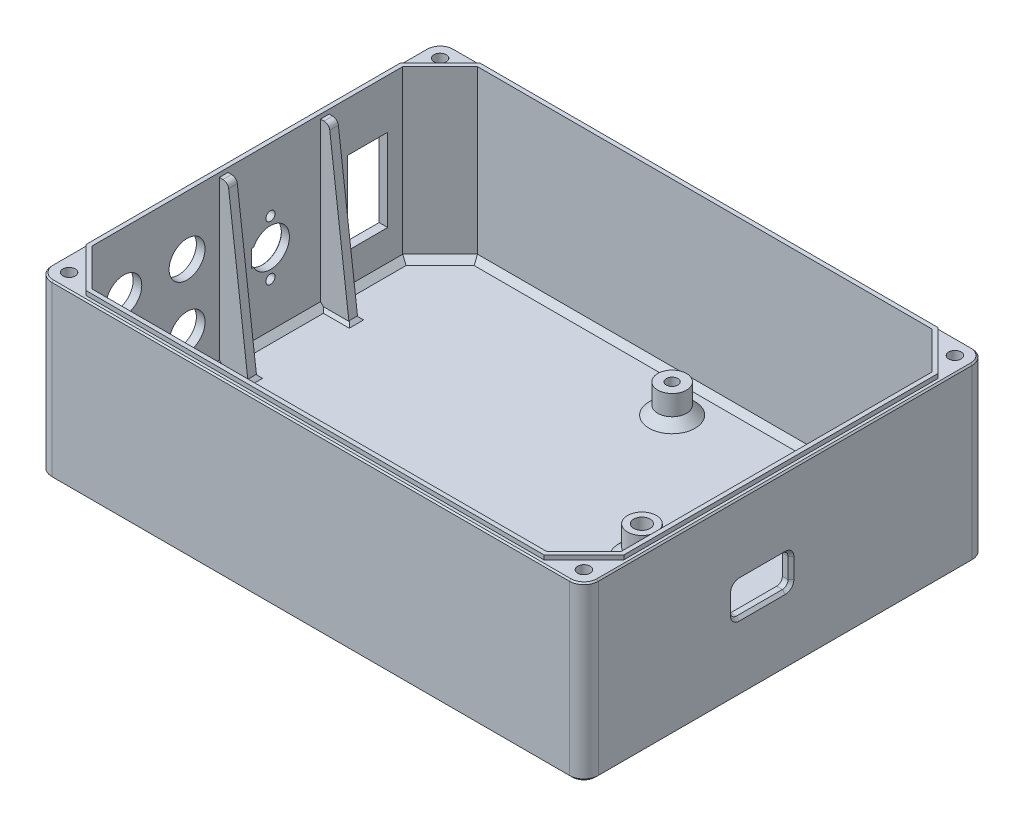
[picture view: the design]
ISO-10303-21;
HEADER;
FILE_DESCRIPTION(('STEP AP214'),'2;1');
FILE_NAME('part.step','',(''),(''),'','','');
FILE_SCHEMA(('AUTOMOTIVE_DESIGN { 1 0 10303 214 1 1 1 1 }'));
ENDSEC;
DATA;
#1=APPLICATION_CONTEXT('core data for automotive mechanical design processes');
#2=APPLICATION_PROTOCOL_DEFINITION('international standard','automotive_design',2000,#1);
#3=PRODUCT_CONTEXT('',#1,'mechanical');
#4=PRODUCT('Part','Part','',(#3));
#5=PRODUCT_RELATED_PRODUCT_CATEGORY('part','',(#4));
#6=PRODUCT_DEFINITION_FORMATION('','',#4);
#7=PRODUCT_DEFINITION_CONTEXT('part definition',#1,'design');
#8=PRODUCT_DEFINITION('design','',#6,#7);
#9=PRODUCT_DEFINITION_SHAPE('','',#8);
#10=(LENGTH_UNIT() NAMED_UNIT(*) SI_UNIT(.MILLI.,.METRE.));
#11=(NAMED_UNIT(*) PLANE_ANGLE_UNIT() SI_UNIT($,.RADIAN.));
#12=(NAMED_UNIT(*) SI_UNIT($,.STERADIAN.) SOLID_ANGLE_UNIT());
#13=UNCERTAINTY_MEASURE_WITH_UNIT(LENGTH_MEASURE(1.E-05),#10,'distance_accuracy_value','');
#14=(GEOMETRIC_REPRESENTATION_CONTEXT(3) GLOBAL_UNCERTAINTY_ASSIGNED_CONTEXT((#13)) GLOBAL_UNIT_ASSIGNED_CONTEXT((#10,
#11,#12)) REPRESENTATION_CONTEXT('',''));
#15=CARTESIAN_POINT('',(0.,0.,0.));
#16=DIRECTION('',(0.,0.,1.));
#17=DIRECTION('',(1.,0.,0.));
#18=AXIS2_PLACEMENT_3D('',#15,#16,#17);
#19=CARTESIAN_POINT('',(0.,60.,0.));
#20=DIRECTION('',(0.,1.,0.));
#21=DIRECTION('',(0.,0.,1.));
#22=AXIS2_PLACEMENT_3D('',#19,#20,#21);
#23=PLANE('',#22);
#24=DIRECTION('',(-1.,0.,0.));
#25=VECTOR('',#24,1.);
#26=CARTESIAN_POINT('',(-82.,60.,-28.4080157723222));
#27=LINE('',#26,#25);
#28=CARTESIAN_POINT('',(-90.7694110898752,60.,-28.4080157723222));
#29=VERTEX_POINT('',#28);
#30=CARTESIAN_POINT('',(-92.,60.,-28.4080157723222));
#31=VERTEX_POINT('',#30);
#32=EDGE_CURVE('E831',#29,#31,#27,.T.);
#33=ORIENTED_EDGE('',*,*,#32,.T.);
#34=DIRECTION('',(0.,0.,1.));
#35=VECTOR('',#34,1.);
#36=CARTESIAN_POINT('',(-92.,60.,-54.));
#37=LINE('',#36,#35);
#38=CARTESIAN_POINT('',(-92.,60.,-25.4080157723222));
#39=VERTEX_POINT('',#38);
#40=EDGE_CURVE('E731',#31,#39,#37,.T.);
#41=ORIENTED_EDGE('',*,*,#40,.T.);
#42=DIRECTION('',(-1.,0.,0.));
#43=VECTOR('',#42,1.);
#44=CARTESIAN_POINT('',(-82.,60.,-25.4080157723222));
#45=LINE('',#44,#43);
#46=CARTESIAN_POINT('',(-90.7694110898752,60.,-25.4080157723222));
#47=VERTEX_POINT('',#46);
#48=EDGE_CURVE('E839',#47,#39,#45,.T.);
#49=ORIENTED_EDGE('',*,*,#48,.F.);
#50=DIRECTION('',(0.,0.,1.));
#51=VECTOR('',#50,1.);
#52=CARTESIAN_POINT('',(-90.7694110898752,60.,-28.4080157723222));
#53=LINE('',#52,#51);
#54=EDGE_CURVE('E1308',#47,#29,#53,.F.);
#55=ORIENTED_EDGE('',*,*,#54,.T.);
#56=EDGE_LOOP('',(#33,#41,#49,#55));
#57=FACE_BOUND('',#56,.T.);
#58=ADVANCED_FACE('F162',(#57),#23,.T.);
#59=DIRECTION('',(-1.,0.,0.));
#60=VECTOR('',#59,1.);
#61=CARTESIAN_POINT('',(-82.,60.,6.74685594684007));
#62=LINE('',#61,#60);
#63=CARTESIAN_POINT('',(-90.7694110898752,60.,6.74685594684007));
#64=VERTEX_POINT('',#63);
#65=CARTESIAN_POINT('',(-92.,60.,6.74685594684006));
#66=VERTEX_POINT('',#65);
#67=EDGE_CURVE('E819',#64,#66,#62,.T.);
#68=ORIENTED_EDGE('',*,*,#67,.T.);
#69=CARTESIAN_POINT('',(-92.,60.,9.74685594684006));
#70=VERTEX_POINT('',#69);
#71=EDGE_CURVE('E736',#66,#70,#37,.T.);
#72=ORIENTED_EDGE('',*,*,#71,.T.);
#73=DIRECTION('',(-1.,0.,0.));
#74=VECTOR('',#73,1.);
#75=CARTESIAN_POINT('',(-82.,60.,9.74685594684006));
#76=LINE('',#75,#74);
#77=CARTESIAN_POINT('',(-90.7694110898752,60.,9.74685594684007));
#78=VERTEX_POINT('',#77);
#79=EDGE_CURVE('E850',#78,#70,#76,.T.);
#80=ORIENTED_EDGE('',*,*,#79,.F.);
#81=DIRECTION('',(0.,0.,1.));
#82=VECTOR('',#81,1.);
#83=CARTESIAN_POINT('',(-90.7694110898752,60.,6.74685594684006));
#84=LINE('',#83,#82);
#85=EDGE_CURVE('E1304',#78,#64,#84,.F.);
#86=ORIENTED_EDGE('',*,*,#85,.T.);
#87=EDGE_LOOP('',(#68,#72,#80,#86));
#88=FACE_BOUND('',#87,.T.);
#89=ADVANCED_FACE('F1625',(#88),#23,.T.);
#90=CARTESIAN_POINT('',(-92.,60.,-70.));
#91=DIRECTION('',(1.,0.,0.));
#92=DIRECTION('',(0.,0.,-1.));
#93=AXIS2_PLACEMENT_3D('',#90,#91,#92);
#94=PLANE('',#93);
#95=DIRECTION('',(0.,-1.,0.));
#96=VECTOR('',#95,1.);
#97=CARTESIAN_POINT('',(-92.,60.,-34.7737095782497));
#98=LINE('',#97,#96);
#99=CARTESIAN_POINT('',(-92.,44.35,-34.7737095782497));
#100=VERTEX_POINT('',#99);
#101=CARTESIAN_POINT('',(-92.,15.65,-34.7737095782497));
#102=VERTEX_POINT('',#101);
#103=EDGE_CURVE('E950',#100,#102,#98,.T.);
#104=ORIENTED_EDGE('',*,*,#103,.F.);
#105=DIRECTION('',(0.,0.,1.));
#106=VECTOR('',#105,1.);
#107=CARTESIAN_POINT('',(-92.,44.35,-70.));
#108=LINE('',#107,#106);
#109=CARTESIAN_POINT('',(-92.,44.35,-48.7737095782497));
#110=VERTEX_POINT('',#109);
#111=EDGE_CURVE('E937',#110,#100,#108,.T.);
#112=ORIENTED_EDGE('',*,*,#111,.F.);
#113=DIRECTION('',(0.,1.,0.));
#114=VECTOR('',#113,1.);
#115=CARTESIAN_POINT('',(-92.,60.,-48.7737095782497));
#116=LINE('',#115,#114);
#117=CARTESIAN_POINT('',(-92.,15.65,-48.7737095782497));
#118=VERTEX_POINT('',#117);
#119=EDGE_CURVE('E945',#118,#110,#116,.T.);
#120=ORIENTED_EDGE('',*,*,#119,.F.);
#121=DIRECTION('',(0.,0.,-1.));
#122=VECTOR('',#121,1.);
#123=CARTESIAN_POINT('',(-92.,15.65,-70.));
#124=LINE('',#123,#122);
#125=EDGE_CURVE('E944',#102,#118,#124,.T.);
#126=ORIENTED_EDGE('',*,*,#125,.F.);
#127=EDGE_LOOP('',(#104,#112,#120,#126));
#128=FACE_BOUND('',#127,.T.);
#129=DIRECTION('',(0.,-1.,0.));
#130=VECTOR('',#129,1.);
#131=CARTESIAN_POINT('',(-92.,60.,-54.));
#132=LINE('',#131,#130);
#133=CARTESIAN_POINT('',(-92.,61.5,-54.));
#134=VERTEX_POINT('',#133);
#135=CARTESIAN_POINT('',(-92.,4.99999999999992,-54.));
#136=VERTEX_POINT('',#135);
#137=EDGE_CURVE('E698',#134,#136,#132,.T.);
#138=ORIENTED_EDGE('',*,*,#137,.F.);
#139=DIRECTION('',(0.,0.,1.));
#140=VECTOR('',#139,1.);
#141=CARTESIAN_POINT('',(-92.,61.5,-54.));
#142=LINE('',#141,#140);
#143=CARTESIAN_POINT('',(-92.,61.5,54.));
#144=VERTEX_POINT('',#143);
#145=EDGE_CURVE('E712',#134,#144,#142,.T.);
#146=ORIENTED_EDGE('',*,*,#145,.T.);
#147=DIRECTION('',(0.,-1.,0.));
#148=VECTOR('',#147,1.);
#149=CARTESIAN_POINT('',(-92.,60.,54.));
#150=LINE('',#149,#148);
#151=CARTESIAN_POINT('',(-92.,4.99999999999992,54.));
#152=VERTEX_POINT('',#151);
#153=EDGE_CURVE('E1052',#144,#152,#150,.T.);
#154=ORIENTED_EDGE('',*,*,#153,.T.);
#155=DIRECTION('',(0.,0.,-1.));
#156=VECTOR('',#155,1.);
#157=CARTESIAN_POINT('',(-92.,4.99999999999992,-54.));
#158=LINE('',#157,#156);
#159=CARTESIAN_POINT('',(-92.,4.99999999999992,34.0694365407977));
#160=VERTEX_POINT('',#159);
#161=EDGE_CURVE('E1155',#152,#160,#158,.T.);
#162=ORIENTED_EDGE('',*,*,#161,.T.);
#163=DIRECTION('',(0.,-1.,0.));
#164=VECTOR('',#163,1.);
#165=CARTESIAN_POINT('',(-92.,3.,34.0694365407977));
#166=LINE('',#165,#164);
#167=CARTESIAN_POINT('',(-92.,15.6591352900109,34.0694365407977));
#168=VERTEX_POINT('',#167);
#169=EDGE_CURVE('E817',#168,#160,#166,.T.);
#170=ORIENTED_EDGE('',*,*,#169,.F.);
#171=DIRECTION('',(0.,0.,1.));
#172=VECTOR('',#171,1.);
#173=CARTESIAN_POINT('',(-92.,15.6591352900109,34.0694365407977));
#174=LINE('',#173,#172);
#175=CARTESIAN_POINT('',(-92.,15.6591352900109,31.0694365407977));
#176=VERTEX_POINT('',#175);
#177=EDGE_CURVE('E823',#176,#168,#174,.T.);
#178=ORIENTED_EDGE('',*,*,#177,.F.);
#179=DIRECTION('',(0.,1.,0.));
#180=VECTOR('',#179,1.);
#181=CARTESIAN_POINT('',(-92.,3.,31.0694365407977));
#182=LINE('',#181,#180);
#183=CARTESIAN_POINT('',(-92.,4.99999999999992,31.0694365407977));
#184=VERTEX_POINT('',#183);
#185=EDGE_CURVE('E822',#184,#176,#182,.T.);
#186=ORIENTED_EDGE('',*,*,#185,.F.);
#187=CARTESIAN_POINT('',(-92.,4.99999999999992,9.74685594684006));
#188=VERTEX_POINT('',#187);
#189=EDGE_CURVE('E1151',#184,#188,#158,.T.);
#190=ORIENTED_EDGE('',*,*,#189,.T.);
#191=DIRECTION('',(0.,-1.,0.));
#192=VECTOR('',#191,1.);
#193=CARTESIAN_POINT('',(-92.,60.,9.74685594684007));
#194=LINE('',#193,#192);
#195=EDGE_CURVE('E836',#70,#188,#194,.T.);
#196=ORIENTED_EDGE('',*,*,#195,.F.);
#197=ORIENTED_EDGE('',*,*,#71,.F.);
#198=DIRECTION('',(0.,1.,0.));
#199=VECTOR('',#198,1.);
#200=CARTESIAN_POINT('',(-92.,60.,6.74685594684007));
#201=LINE('',#200,#199);
#202=CARTESIAN_POINT('',(-92.,4.99999999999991,6.74685594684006));
#203=VERTEX_POINT('',#202);
#204=EDGE_CURVE('E848',#203,#66,#201,.T.);
#205=ORIENTED_EDGE('',*,*,#204,.F.);
#206=CARTESIAN_POINT('',(-92.,4.99999999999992,-25.4080157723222));
#207=VERTEX_POINT('',#206);
#208=EDGE_CURVE('E3165',#203,#207,#158,.T.);
#209=ORIENTED_EDGE('',*,*,#208,.T.);
#210=DIRECTION('',(0.,-1.,0.));
#211=VECTOR('',#210,1.);
#212=CARTESIAN_POINT('',(-92.,3.,-25.4080157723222));
#213=LINE('',#212,#211);
#214=EDGE_CURVE('E825',#39,#207,#213,.T.);
#215=ORIENTED_EDGE('',*,*,#214,.F.);
#216=ORIENTED_EDGE('',*,*,#40,.F.);
#217=DIRECTION('',(0.,1.,0.));
#218=VECTOR('',#217,1.);
#219=CARTESIAN_POINT('',(-92.,3.,-28.4080157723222));
#220=LINE('',#219,#218);
#221=CARTESIAN_POINT('',(-92.,4.99999999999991,-28.4080157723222));
#222=VERTEX_POINT('',#221);
#223=EDGE_CURVE('E837',#222,#31,#220,.T.);
#224=ORIENTED_EDGE('',*,*,#223,.F.);
#225=EDGE_CURVE('E1152',#222,#136,#158,.T.);
#226=ORIENTED_EDGE('',*,*,#225,.T.);
#227=EDGE_LOOP('',(#138,#146,#154,#162,#170,#178,#186,#190,#196,#197,#205,#209,#215,#216,#224,#226));
#228=FACE_BOUND('',#227,.T.);
#229=CARTESIAN_POINT('',(-92.,30.,-7.99999999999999));
#230=DIRECTION('',(1.,0.,0.));
#231=DIRECTION('',(0.,0.,-1.));
#232=AXIS2_PLACEMENT_3D('',#229,#230,#231);
#233=CIRCLE('',#232,6.6);
#234=CARTESIAN_POINT('',(-92.,27.,-2.12122461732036));
#235=VERTEX_POINT('',#234);
#236=CARTESIAN_POINT('',(-92.,33.,-2.12122461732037));
#237=VERTEX_POINT('',#236);
#238=EDGE_CURVE('E929',#235,#237,#233,.T.);
#239=ORIENTED_EDGE('',*,*,#238,.F.);
#240=DIRECTION('',(0.,0.,-1.));
#241=VECTOR('',#240,1.);
#242=CARTESIAN_POINT('',(-92.,27.,-70.));
#243=LINE('',#242,#241);
#244=CARTESIAN_POINT('',(-92.,27.,-1.4));
#245=VERTEX_POINT('',#244);
#246=EDGE_CURVE('E925',#245,#235,#243,.T.);
#247=ORIENTED_EDGE('',*,*,#246,.F.);
#248=DIRECTION('',(0.,-1.,0.));
#249=VECTOR('',#248,1.);
#250=CARTESIAN_POINT('',(-92.,60.,-1.4));
#251=LINE('',#250,#249);
#252=CARTESIAN_POINT('',(-92.,33.,-1.39999999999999));
#253=VERTEX_POINT('',#252);
#254=EDGE_CURVE('E921',#253,#245,#251,.T.);
#255=ORIENTED_EDGE('',*,*,#254,.F.);
#256=DIRECTION('',(0.,0.,1.));
#257=VECTOR('',#256,1.);
#258=CARTESIAN_POINT('',(-92.,33.,-70.));
#259=LINE('',#258,#257);
#260=EDGE_CURVE('E930',#237,#253,#259,.T.);
#261=ORIENTED_EDGE('',*,*,#260,.F.);
#262=EDGE_LOOP('',(#239,#247,#255,#261));
#263=FACE_BOUND('',#262,.T.);
#264=CARTESIAN_POINT('',(-92.,39.5,-7.99999999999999));
#265=DIRECTION('',(1.,0.,0.));
#266=DIRECTION('',(0.,0.,-1.));
#267=AXIS2_PLACEMENT_3D('',#264,#265,#266);
#268=CIRCLE('',#267,1.6);
#269=CARTESIAN_POINT('',(-92.,39.5,-9.59999999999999));
#270=VERTEX_POINT('',#269);
#271=EDGE_CURVE('E935',#270,#270,#268,.T.);
#272=ORIENTED_EDGE('',*,*,#271,.F.);
#273=EDGE_LOOP('',(#272));
#274=FACE_BOUND('',#273,.T.);
#275=CARTESIAN_POINT('',(-92.,20.5,-7.99999999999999));
#276=DIRECTION('',(1.,0.,0.));
#277=DIRECTION('',(0.,0.,-1.));
#278=AXIS2_PLACEMENT_3D('',#275,#276,#277);
#279=CIRCLE('',#278,1.6);
#280=CARTESIAN_POINT('',(-92.,20.5,-9.59999999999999));
#281=VERTEX_POINT('',#280);
#282=EDGE_CURVE('E940',#281,#281,#279,.T.);
#283=ORIENTED_EDGE('',*,*,#282,.F.);
#284=EDGE_LOOP('',(#283));
#285=FACE_BOUND('',#284,.T.);
#286=CARTESIAN_POINT('',(-92.,41.,43.));
#287=DIRECTION('',(1.,0.,0.));
#288=DIRECTION('',(0.,0.,-1.));
#289=AXIS2_PLACEMENT_3D('',#286,#287,#288);
#290=CIRCLE('',#289,6.25000000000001);
#291=CARTESIAN_POINT('',(-92.,41.,36.75));
#292=VERTEX_POINT('',#291);
#293=EDGE_CURVE('E933',#292,#292,#290,.T.);
#294=ORIENTED_EDGE('',*,*,#293,.F.);
#295=EDGE_LOOP('',(#294));
#296=FACE_BOUND('',#295,.T.);
#297=CARTESIAN_POINT('',(-92.,41.,21.));
#298=DIRECTION('',(1.,0.,0.));
#299=DIRECTION('',(0.,0.,-1.));
#300=AXIS2_PLACEMENT_3D('',#297,#298,#299);
#301=CIRCLE('',#300,6.25);
#302=CARTESIAN_POINT('',(-92.,41.,14.75));
#303=VERTEX_POINT('',#302);
#304=EDGE_CURVE('E920',#303,#303,#301,.T.);
#305=ORIENTED_EDGE('',*,*,#304,.F.);
#306=EDGE_LOOP('',(#305));
#307=FACE_BOUND('',#306,.T.);
#308=CARTESIAN_POINT('',(-92.,19.,21.));
#309=DIRECTION('',(1.,0.,0.));
#310=DIRECTION('',(0.,0.,-1.));
#311=AXIS2_PLACEMENT_3D('',#308,#309,#310);
#312=CIRCLE('',#311,6.25);
#313=CARTESIAN_POINT('',(-92.,19.,14.75));
#314=VERTEX_POINT('',#313);
#315=EDGE_CURVE('E918',#314,#314,#312,.T.);
#316=ORIENTED_EDGE('',*,*,#315,.F.);
#317=EDGE_LOOP('',(#316));
#318=FACE_BOUND('',#317,.T.);
#319=CARTESIAN_POINT('',(-92.,19.,43.));
#320=DIRECTION('',(1.,0.,0.));
#321=DIRECTION('',(0.,0.,-1.));
#322=AXIS2_PLACEMENT_3D('',#319,#320,#321);
#323=CIRCLE('',#322,6.25000000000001);
#324=CARTESIAN_POINT('',(-92.,19.,36.75));
#325=VERTEX_POINT('',#324);
#326=EDGE_CURVE('E869',#325,#325,#323,.T.);
#327=ORIENTED_EDGE('',*,*,#326,.F.);
#328=EDGE_LOOP('',(#327));
#329=FACE_BOUND('',#328,.T.);
#330=ADVANCED_FACE('F1629',(#128,#228,#263,#274,#285,#296,#307,#318,#329),#94,.T.);
#331=CARTESIAN_POINT('',(0.,3.,0.));
#332=DIRECTION('',(0.,1.,0.));
#333=DIRECTION('',(0.,0.,1.));
#334=AXIS2_PLACEMENT_3D('',#331,#332,#333);
#335=PLANE('',#334);
#336=CARTESIAN_POINT('',(76.2703566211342,3.,55.5833883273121));
#337=DIRECTION('',(0.,1.,0.));
#338=DIRECTION('',(0.,0.,1.));
#339=AXIS2_PLACEMENT_3D('',#336,#337,#338);
#340=CIRCLE('',#339,7.99999999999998);
#341=CARTESIAN_POINT('',(76.2703566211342,3.,63.5833883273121));
#342=VERTEX_POINT('',#341);
#343=EDGE_CURVE('E1273',#342,#342,#340,.F.);
#344=ORIENTED_EDGE('',*,*,#343,.T.);
#345=EDGE_LOOP('',(#344));
#346=FACE_BOUND('',#345,.T.);
#347=CARTESIAN_POINT('',(1.27035662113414,3.,55.5833883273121));
#348=DIRECTION('',(0.,1.,0.));
#349=DIRECTION('',(0.,0.,1.));
#350=AXIS2_PLACEMENT_3D('',#347,#348,#349);
#351=CIRCLE('',#350,7.99999999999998);
#352=CARTESIAN_POINT('',(1.27035662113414,3.,63.5833883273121));
#353=VERTEX_POINT('',#352);
#354=EDGE_CURVE('E1275',#353,#353,#351,.F.);
#355=ORIENTED_EDGE('',*,*,#354,.T.);
#356=EDGE_LOOP('',(#355));
#357=FACE_BOUND('',#356,.T.);
#358=CARTESIAN_POINT('',(76.2703566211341,3.,-54.4166116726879));
#359=DIRECTION('',(0.,1.,0.));
#360=DIRECTION('',(0.,0.,1.));
#361=AXIS2_PLACEMENT_3D('',#358,#359,#360);
#362=CIRCLE('',#361,7.99999999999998);
#363=CARTESIAN_POINT('',(76.2703566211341,3.,-46.4166116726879));
#364=VERTEX_POINT('',#363);
#365=EDGE_CURVE('E1270',#364,#364,#362,.F.);
#366=ORIENTED_EDGE('',*,*,#365,.T.);
#367=EDGE_LOOP('',(#366));
#368=FACE_BOUND('',#367,.T.);
#369=CARTESIAN_POINT('',(38.7703566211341,3.,-6.41661167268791));
#370=DIRECTION('',(0.,1.,0.));
#371=DIRECTION('',(0.,0.,1.));
#372=AXIS2_PLACEMENT_3D('',#369,#370,#371);
#373=CIRCLE('',#372,7.99999999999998);
#374=CARTESIAN_POINT('',(38.7703566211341,3.,1.58338832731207));
#375=VERTEX_POINT('',#374);
#376=EDGE_CURVE('E1268',#375,#375,#373,.F.);
#377=ORIENTED_EDGE('',*,*,#376,.T.);
#378=EDGE_LOOP('',(#377));
#379=FACE_BOUND('',#378,.T.);
#380=CARTESIAN_POINT('',(1.27035662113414,3.,-54.4166116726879));
#381=DIRECTION('',(0.,1.,0.));
#382=DIRECTION('',(0.,0.,1.));
#383=AXIS2_PLACEMENT_3D('',#380,#381,#382);
#384=CIRCLE('',#383,7.99999999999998);
#385=CARTESIAN_POINT('',(1.27035662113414,3.,-46.4166116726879));
#386=VERTEX_POINT('',#385);
#387=EDGE_CURVE('E1265',#386,#386,#384,.F.);
#388=ORIENTED_EDGE('',*,*,#387,.T.);
#389=EDGE_LOOP('',(#388));
#390=FACE_BOUND('',#389,.T.);
#391=DIRECTION('',(0.,0.,1.));
#392=VECTOR('',#391,1.);
#393=CARTESIAN_POINT('',(-90.,3.,54.));
#394=LINE('',#393,#392);
#395=CARTESIAN_POINT('',(-90.,3.,-53.1715728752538));
#396=VERTEX_POINT('',#395);
#397=CARTESIAN_POINT('',(-90.,3.,-29.4080157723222));
#398=VERTEX_POINT('',#397);
#399=EDGE_CURVE('E1142',#396,#398,#394,.T.);
#400=ORIENTED_EDGE('',*,*,#399,.T.);
#401=DIRECTION('',(1.,0.,0.));
#402=VECTOR('',#401,1.);
#403=CARTESIAN_POINT('',(0.,3.,-29.4080157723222));
#404=LINE('',#403,#402);
#405=CARTESIAN_POINT('',(-81.,3.,-29.4080157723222));
#406=VERTEX_POINT('',#405);
#407=EDGE_CURVE('E1338',#398,#406,#404,.T.);
#408=ORIENTED_EDGE('',*,*,#407,.T.);
#409=DIRECTION('',(0.,0.,1.));
#410=VECTOR('',#409,1.);
#411=CARTESIAN_POINT('',(-81.,3.,0.));
#412=LINE('',#411,#410);
#413=CARTESIAN_POINT('',(-81.,3.,-24.4080157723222));
#414=VERTEX_POINT('',#413);
#415=EDGE_CURVE('E1336',#406,#414,#412,.T.);
#416=ORIENTED_EDGE('',*,*,#415,.T.);
#417=DIRECTION('',(-1.,0.,0.));
#418=VECTOR('',#417,1.);
#419=CARTESIAN_POINT('',(0.,3.,-24.4080157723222));
#420=LINE('',#419,#418);
#421=CARTESIAN_POINT('',(-90.,3.,-24.4080157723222));
#422=VERTEX_POINT('',#421);
#423=EDGE_CURVE('E1333',#414,#422,#420,.T.);
#424=ORIENTED_EDGE('',*,*,#423,.T.);
#425=CARTESIAN_POINT('',(-90.,3.,5.74685594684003));
#426=VERTEX_POINT('',#425);
#427=EDGE_CURVE('E1150',#422,#426,#394,.T.);
#428=ORIENTED_EDGE('',*,*,#427,.T.);
#429=DIRECTION('',(1.,0.,0.));
#430=VECTOR('',#429,1.);
#431=CARTESIAN_POINT('',(0.,3.,5.74685594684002));
#432=LINE('',#431,#430);
#433=CARTESIAN_POINT('',(-81.,3.,5.74685594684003));
#434=VERTEX_POINT('',#433);
#435=EDGE_CURVE('E1329',#426,#434,#432,.T.);
#436=ORIENTED_EDGE('',*,*,#435,.T.);
#437=DIRECTION('',(0.,0.,1.));
#438=VECTOR('',#437,1.);
#439=CARTESIAN_POINT('',(-81.,3.,0.));
#440=LINE('',#439,#438);
#441=CARTESIAN_POINT('',(-81.,3.,10.7468559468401));
#442=VERTEX_POINT('',#441);
#443=EDGE_CURVE('E1327',#434,#442,#440,.T.);
#444=ORIENTED_EDGE('',*,*,#443,.T.);
#445=DIRECTION('',(-1.,0.,0.));
#446=VECTOR('',#445,1.);
#447=CARTESIAN_POINT('',(0.,3.,10.7468559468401));
#448=LINE('',#447,#446);
#449=CARTESIAN_POINT('',(-90.,3.,10.7468559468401));
#450=VERTEX_POINT('',#449);
#451=EDGE_CURVE('E1335',#442,#450,#448,.T.);
#452=ORIENTED_EDGE('',*,*,#451,.T.);
#453=CARTESIAN_POINT('',(-90.,3.,30.0694365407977));
#454=VERTEX_POINT('',#453);
#455=EDGE_CURVE('E1149',#450,#454,#394,.T.);
#456=ORIENTED_EDGE('',*,*,#455,.T.);
#457=DIRECTION('',(1.,0.,0.));
#458=VECTOR('',#457,1.);
#459=CARTESIAN_POINT('',(0.,3.,30.0694365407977));
#460=LINE('',#459,#458);
#461=CARTESIAN_POINT('',(-81.,3.,30.0694365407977));
#462=VERTEX_POINT('',#461);
#463=EDGE_CURVE('E1326',#454,#462,#460,.T.);
#464=ORIENTED_EDGE('',*,*,#463,.T.);
#465=DIRECTION('',(0.,0.,1.));
#466=VECTOR('',#465,1.);
#467=CARTESIAN_POINT('',(-81.,3.,0.));
#468=LINE('',#467,#466);
#469=CARTESIAN_POINT('',(-81.,3.,35.0694365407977));
#470=VERTEX_POINT('',#469);
#471=EDGE_CURVE('E1322',#462,#470,#468,.T.);
#472=ORIENTED_EDGE('',*,*,#471,.T.);
#473=DIRECTION('',(-1.,0.,0.));
#474=VECTOR('',#473,1.);
#475=CARTESIAN_POINT('',(0.,3.,35.0694365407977));
#476=LINE('',#475,#474);
#477=CARTESIAN_POINT('',(-90.,3.,35.0694365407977));
#478=VERTEX_POINT('',#477);
#479=EDGE_CURVE('E1325',#470,#478,#476,.T.);
#480=ORIENTED_EDGE('',*,*,#479,.T.);
#481=CARTESIAN_POINT('',(-90.,3.,53.1715728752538));
#482=VERTEX_POINT('',#481);
#483=EDGE_CURVE('E1144',#478,#482,#394,.T.);
#484=ORIENTED_EDGE('',*,*,#483,.T.);
#485=DIRECTION('',(0.707106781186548,0.,0.707106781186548));
#486=VECTOR('',#485,1.);
#487=CARTESIAN_POINT('',(-71.5857864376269,3.,71.5857864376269));
#488=LINE('',#487,#486);
#489=CARTESIAN_POINT('',(-78.1715728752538,3.,65.));
#490=VERTEX_POINT('',#489);
#491=EDGE_CURVE('E1147',#482,#490,#488,.T.);
#492=ORIENTED_EDGE('',*,*,#491,.T.);
#493=DIRECTION('',(1.,0.,0.));
#494=VECTOR('',#493,1.);
#495=CARTESIAN_POINT('',(79.,3.,65.));
#496=LINE('',#495,#494);
#497=CARTESIAN_POINT('',(78.1715728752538,3.,65.));
#498=VERTEX_POINT('',#497);
#499=EDGE_CURVE('E1134',#490,#498,#496,.T.);
#500=ORIENTED_EDGE('',*,*,#499,.T.);
#501=DIRECTION('',(0.707106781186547,0.,-0.707106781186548));
#502=VECTOR('',#501,1.);
#503=CARTESIAN_POINT('',(71.585786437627,3.,71.5857864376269));
#504=LINE('',#503,#502);
#505=CARTESIAN_POINT('',(90.0000000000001,3.,53.1715728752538));
#506=VERTEX_POINT('',#505);
#507=EDGE_CURVE('E1135',#498,#506,#504,.T.);
#508=ORIENTED_EDGE('',*,*,#507,.T.);
#509=DIRECTION('',(0.,0.,-1.));
#510=VECTOR('',#509,1.);
#511=CARTESIAN_POINT('',(90.,3.,-54.));
#512=LINE('',#511,#510);
#513=CARTESIAN_POINT('',(90.,3.,-53.1715728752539));
#514=VERTEX_POINT('',#513);
#515=EDGE_CURVE('E1126',#506,#514,#512,.T.);
#516=ORIENTED_EDGE('',*,*,#515,.T.);
#517=DIRECTION('',(-0.707106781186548,0.,-0.707106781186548));
#518=VECTOR('',#517,1.);
#519=CARTESIAN_POINT('',(71.585786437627,3.,-71.585786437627));
#520=LINE('',#519,#518);
#521=CARTESIAN_POINT('',(78.1715728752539,3.,-65.));
#522=VERTEX_POINT('',#521);
#523=EDGE_CURVE('E1139',#514,#522,#520,.T.);
#524=ORIENTED_EDGE('',*,*,#523,.T.);
#525=DIRECTION('',(-1.,0.,0.));
#526=VECTOR('',#525,1.);
#527=CARTESIAN_POINT('',(-79.0000000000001,3.,-65.));
#528=LINE('',#527,#526);
#529=CARTESIAN_POINT('',(-78.1715728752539,3.,-65.));
#530=VERTEX_POINT('',#529);
#531=EDGE_CURVE('E1140',#522,#530,#528,.T.);
#532=ORIENTED_EDGE('',*,*,#531,.T.);
#533=DIRECTION('',(-0.707106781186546,0.,0.707106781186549));
#534=VECTOR('',#533,1.);
#535=CARTESIAN_POINT('',(-71.5857864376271,3.,-71.5857864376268));
#536=LINE('',#535,#534);
#537=EDGE_CURVE('E1137',#530,#396,#536,.T.);
#538=ORIENTED_EDGE('',*,*,#537,.T.);
#539=EDGE_LOOP('',(#400,#408,#416,#424,#428,#436,#444,#452,#456,#464,#472,#480,#484,#492,#500,
#508,#516,#524,#532,#538));
#540=FACE_BOUND('',#539,.T.);
#541=ADVANCED_FACE('F1789',(#346,#357,#368,#379,#390,#540),#335,.T.);
#542=CARTESIAN_POINT('',(-90.,3.,0.));
#543=DIRECTION('',(0.707106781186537,0.707106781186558,0.));
#544=DIRECTION('',(0.,0.,-1.));
#545=AXIS2_PLACEMENT_3D('',#542,#543,#544);
#546=PLANE('',#545);
#547=ORIENTED_EDGE('',*,*,#483,.F.);
#548=DIRECTION('',(0.577350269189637,-0.57735026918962,0.577350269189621));
#549=VECTOR('',#548,1.);
#550=CARTESIAN_POINT('',(-59.9999999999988,-27.0000000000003,65.069436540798));
#551=LINE('',#550,#549);
#552=CARTESIAN_POINT('',(-91.,4.,34.0694365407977));
#553=VERTEX_POINT('',#552);
#554=EDGE_CURVE('E1363',#478,#553,#551,.F.);
#555=ORIENTED_EDGE('',*,*,#554,.T.);
#556=DIRECTION('',(-0.707106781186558,0.707106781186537,0.));
#557=VECTOR('',#556,1.);
#558=CARTESIAN_POINT('',(-90.,3.,34.0694365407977));
#559=LINE('',#558,#557);
#560=EDGE_CURVE('E1260',#160,#553,#559,.F.);
#561=ORIENTED_EDGE('',*,*,#560,.F.);
#562=ORIENTED_EDGE('',*,*,#161,.F.);
#563=DIRECTION('',(-0.678598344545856,0.678598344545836,0.281084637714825));
#564=VECTOR('',#563,1.);
#565=CARTESIAN_POINT('',(-92.,4.99999999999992,54.));
#566=LINE('',#565,#564);
#567=EDGE_CURVE('E1000',#482,#152,#566,.T.);
#568=ORIENTED_EDGE('',*,*,#567,.F.);
#569=EDGE_LOOP('',(#547,#555,#561,#562,#568));
#570=FACE_BOUND('',#569,.T.);
#571=ADVANCED_FACE('F1794',(#570),#546,.T.);
#572=ORIENTED_EDGE('',*,*,#455,.F.);
#573=DIRECTION('',(0.577350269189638,-0.577350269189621,0.577350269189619));
#574=VECTOR('',#573,1.);
#575=CARTESIAN_POINT('',(-59.9999999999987,-27.0000000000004,40.7468559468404));
#576=LINE('',#575,#574);
#577=CARTESIAN_POINT('',(-91.0000000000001,4.00000000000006,9.74685594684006));
#578=VERTEX_POINT('',#577);
#579=EDGE_CURVE('E1352',#450,#578,#576,.F.);
#580=ORIENTED_EDGE('',*,*,#579,.T.);
#581=DIRECTION('',(-0.707106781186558,0.707106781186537,0.));
#582=VECTOR('',#581,1.);
#583=CARTESIAN_POINT('',(-90.,3.,9.74685594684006));
#584=LINE('',#583,#582);
#585=EDGE_CURVE('E1250',#188,#578,#584,.F.);
#586=ORIENTED_EDGE('',*,*,#585,.F.);
#587=ORIENTED_EDGE('',*,*,#189,.F.);
#588=DIRECTION('',(0.707106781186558,-0.707106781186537,0.));
#589=VECTOR('',#588,1.);
#590=CARTESIAN_POINT('',(-90.,3.,31.0694365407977));
#591=LINE('',#590,#589);
#592=CARTESIAN_POINT('',(-91.0000000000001,4.00000000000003,31.0694365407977));
#593=VERTEX_POINT('',#592);
#594=EDGE_CURVE('E1254',#593,#184,#591,.F.);
#595=ORIENTED_EDGE('',*,*,#594,.F.);
#596=DIRECTION('',(-0.577350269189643,0.577350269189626,0.577350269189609));
#597=VECTOR('',#596,1.);
#598=CARTESIAN_POINT('',(-87.9999999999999,0.999999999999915,28.0694365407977));
#599=LINE('',#598,#597);
#600=EDGE_CURVE('E1346',#593,#454,#599,.F.);
#601=ORIENTED_EDGE('',*,*,#600,.T.);
#602=EDGE_LOOP('',(#572,#580,#586,#587,#595,#601));
#603=FACE_BOUND('',#602,.T.);
#604=ADVANCED_FACE('F1799',(#603),#546,.T.);
#605=ORIENTED_EDGE('',*,*,#427,.F.);
#606=DIRECTION('',(0.577350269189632,-0.577350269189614,0.577350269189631));
#607=VECTOR('',#606,1.);
#608=CARTESIAN_POINT('',(-59.9999999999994,-26.9999999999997,5.59198422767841));
#609=LINE('',#608,#607);
#610=CARTESIAN_POINT('',(-91.,4.,-25.4080157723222));
#611=VERTEX_POINT('',#610);
#612=EDGE_CURVE('E1341',#422,#611,#609,.F.);
#613=ORIENTED_EDGE('',*,*,#612,.T.);
#614=DIRECTION('',(-0.707106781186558,0.707106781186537,0.));
#615=VECTOR('',#614,1.);
#616=CARTESIAN_POINT('',(-90.,3.,-25.4080157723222));
#617=LINE('',#616,#615);
#618=EDGE_CURVE('E1255',#207,#611,#617,.F.);
#619=ORIENTED_EDGE('',*,*,#618,.F.);
#620=ORIENTED_EDGE('',*,*,#208,.F.);
#621=DIRECTION('',(0.707106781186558,-0.707106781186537,0.));
#622=VECTOR('',#621,1.);
#623=CARTESIAN_POINT('',(-90.,3.,6.74685594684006));
#624=LINE('',#623,#622);
#625=CARTESIAN_POINT('',(-91.0000000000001,4.00000000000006,6.74685594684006));
#626=VERTEX_POINT('',#625);
#627=EDGE_CURVE('E1223',#626,#203,#624,.F.);
#628=ORIENTED_EDGE('',*,*,#627,.F.);
#629=DIRECTION('',(-0.577350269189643,0.577350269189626,0.577350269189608));
#630=VECTOR('',#629,1.);
#631=CARTESIAN_POINT('',(-87.9999999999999,0.999999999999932,3.74685594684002));
#632=LINE('',#631,#630);
#633=EDGE_CURVE('E1342',#626,#426,#632,.F.);
#634=ORIENTED_EDGE('',*,*,#633,.T.);
#635=EDGE_LOOP('',(#605,#613,#619,#620,#628,#634));
#636=FACE_BOUND('',#635,.T.);
#637=ADVANCED_FACE('F2279',(#636),#546,.T.);
#638=DIRECTION('',(0.707106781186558,-0.707106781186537,0.));
#639=VECTOR('',#638,1.);
#640=CARTESIAN_POINT('',(-90.,3.,-28.4080157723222));
#641=LINE('',#640,#639);
#642=CARTESIAN_POINT('',(-91.0000000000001,4.00000000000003,-28.4080157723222));
#643=VERTEX_POINT('',#642);
#644=EDGE_CURVE('E1249',#643,#222,#641,.F.);
#645=ORIENTED_EDGE('',*,*,#644,.F.);
#646=DIRECTION('',(-0.577350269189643,0.577350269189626,0.577350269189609));
#647=VECTOR('',#646,1.);
#648=CARTESIAN_POINT('',(-87.9999999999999,0.999999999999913,-31.4080157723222));
#649=LINE('',#648,#647);
#650=EDGE_CURVE('E1319',#643,#398,#649,.F.);
#651=ORIENTED_EDGE('',*,*,#650,.T.);
#652=ORIENTED_EDGE('',*,*,#399,.F.);
#653=DIRECTION('',(-0.678598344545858,0.678598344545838,-0.281084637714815));
#654=VECTOR('',#653,1.);
#655=CARTESIAN_POINT('',(-79.8578643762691,-7.14213562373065,-48.9705627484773));
#656=LINE('',#655,#654);
#657=EDGE_CURVE('E1171',#396,#136,#656,.T.);
#658=ORIENTED_EDGE('',*,*,#657,.T.);
#659=ORIENTED_EDGE('',*,*,#225,.F.);
#660=EDGE_LOOP('',(#645,#651,#652,#658,#659));
#661=FACE_BOUND('',#660,.T.);
#662=ADVANCED_FACE('F1778',(#661),#546,.T.);
#663=CARTESIAN_POINT('',(92.,60.,-70.));
#664=DIRECTION('',(-1.,0.,0.));
#665=DIRECTION('',(0.,0.,1.));
#666=AXIS2_PLACEMENT_3D('',#663,#664,#665);
#667=PLANE('',#666);
#668=DIRECTION('',(0.,-1.,0.));
#669=VECTOR('',#668,1.);
#670=CARTESIAN_POINT('',(92.,60.,-54.));
#671=LINE('',#670,#669);
#672=CARTESIAN_POINT('',(92.,61.5,-54.));
#673=VERTEX_POINT('',#672);
#674=CARTESIAN_POINT('',(92.,4.99999999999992,-54.));
#675=VERTEX_POINT('',#674);
#676=EDGE_CURVE('E1049',#673,#675,#671,.T.);
#677=ORIENTED_EDGE('',*,*,#676,.T.);
#678=DIRECTION('',(0.,0.,1.));
#679=VECTOR('',#678,1.);
#680=CARTESIAN_POINT('',(92.,4.99999999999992,54.));
#681=LINE('',#680,#679);
#682=CARTESIAN_POINT('',(92.,4.99999999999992,54.));
#683=VERTEX_POINT('',#682);
#684=EDGE_CURVE('E1162',#675,#683,#681,.T.);
#685=ORIENTED_EDGE('',*,*,#684,.T.);
#686=DIRECTION('',(0.,-1.,0.));
#687=VECTOR('',#686,1.);
#688=CARTESIAN_POINT('',(92.,60.,54.));
#689=LINE('',#688,#687);
#690=CARTESIAN_POINT('',(92.,61.5,54.));
#691=VERTEX_POINT('',#690);
#692=EDGE_CURVE('E1058',#691,#683,#689,.T.);
#693=ORIENTED_EDGE('',*,*,#692,.F.);
#694=DIRECTION('',(0.,0.,-1.));
#695=VECTOR('',#694,1.);
#696=CARTESIAN_POINT('',(92.,61.5,54.));
#697=LINE('',#696,#695);
#698=EDGE_CURVE('E727',#691,#673,#697,.T.);
#699=ORIENTED_EDGE('',*,*,#698,.T.);
#700=EDGE_LOOP('',(#677,#685,#693,#699));
#701=FACE_BOUND('',#700,.T.);
#702=DIRECTION('',(0.,0.,1.));
#703=VECTOR('',#702,1.);
#704=CARTESIAN_POINT('',(92.,35.,-70.));
#705=LINE('',#704,#703);
#706=CARTESIAN_POINT('',(92.,35.,-0.0168663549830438));
#707=VERTEX_POINT('',#706);
#708=CARTESIAN_POINT('',(92.,35.,15.9831336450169));
#709=VERTEX_POINT('',#708);
#710=EDGE_CURVE('E993',#707,#709,#705,.T.);
#711=ORIENTED_EDGE('',*,*,#710,.T.);
#712=CARTESIAN_POINT('',(92.,33.,15.9831336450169));
#713=DIRECTION('',(-1.,0.,0.));
#714=DIRECTION('',(0.,0.,1.));
#715=AXIS2_PLACEMENT_3D('',#712,#713,#714);
#716=CIRCLE('',#715,2.);
#717=CARTESIAN_POINT('',(92.,33.,17.9831336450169));
#718=VERTEX_POINT('',#717);
#719=EDGE_CURVE('E995',#709,#718,#716,.F.);
#720=ORIENTED_EDGE('',*,*,#719,.T.);
#721=DIRECTION('',(0.,-1.,0.));
#722=VECTOR('',#721,1.);
#723=CARTESIAN_POINT('',(92.,60.0000000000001,17.9831336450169));
#724=LINE('',#723,#722);
#725=CARTESIAN_POINT('',(92.,26.,17.9831336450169));
#726=VERTEX_POINT('',#725);
#727=EDGE_CURVE('E974',#718,#726,#724,.T.);
#728=ORIENTED_EDGE('',*,*,#727,.T.);
#729=CARTESIAN_POINT('',(92.,26.,15.9831336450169));
#730=DIRECTION('',(-1.,0.,0.));
#731=DIRECTION('',(0.,0.,1.));
#732=AXIS2_PLACEMENT_3D('',#729,#730,#731);
#733=CIRCLE('',#732,2.00000000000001);
#734=CARTESIAN_POINT('',(92.,24.,15.9831336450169));
#735=VERTEX_POINT('',#734);
#736=EDGE_CURVE('E977',#726,#735,#733,.F.);
#737=ORIENTED_EDGE('',*,*,#736,.T.);
#738=DIRECTION('',(0.,0.,-1.));
#739=VECTOR('',#738,1.);
#740=CARTESIAN_POINT('',(92.,24.,-70.));
#741=LINE('',#740,#739);
#742=CARTESIAN_POINT('',(92.,24.,-0.0168663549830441));
#743=VERTEX_POINT('',#742);
#744=EDGE_CURVE('E979',#735,#743,#741,.T.);
#745=ORIENTED_EDGE('',*,*,#744,.T.);
#746=CARTESIAN_POINT('',(92.,26.,-0.0168663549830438));
#747=DIRECTION('',(-1.,0.,0.));
#748=DIRECTION('',(0.,0.,1.));
#749=AXIS2_PLACEMENT_3D('',#746,#747,#748);
#750=CIRCLE('',#749,2.);
#751=CARTESIAN_POINT('',(92.,26.,-2.01686635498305));
#752=VERTEX_POINT('',#751);
#753=EDGE_CURVE('E985',#743,#752,#750,.F.);
#754=ORIENTED_EDGE('',*,*,#753,.T.);
#755=DIRECTION('',(0.,1.,0.));
#756=VECTOR('',#755,1.);
#757=CARTESIAN_POINT('',(92.,60.,-2.01686635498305));
#758=LINE('',#757,#756);
#759=CARTESIAN_POINT('',(92.,33.,-2.01686635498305));
#760=VERTEX_POINT('',#759);
#761=EDGE_CURVE('E983',#752,#760,#758,.T.);
#762=ORIENTED_EDGE('',*,*,#761,.T.);
#763=CARTESIAN_POINT('',(92.,33.,-0.0168663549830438));
#764=DIRECTION('',(-1.,0.,0.));
#765=DIRECTION('',(0.,0.,1.));
#766=AXIS2_PLACEMENT_3D('',#763,#764,#765);
#767=CIRCLE('',#766,2.);
#768=EDGE_CURVE('E990',#760,#707,#767,.F.);
#769=ORIENTED_EDGE('',*,*,#768,.T.);
#770=EDGE_LOOP('',(#711,#720,#728,#737,#745,#754,#762,#769));
#771=FACE_BOUND('',#770,.T.);
#772=ADVANCED_FACE('F1774',(#701,#771),#667,.T.);
#773=CARTESIAN_POINT('',(95.,60.,-70.));
#774=DIRECTION('',(-1.,0.,0.));
#775=DIRECTION('',(0.,0.,1.));
#776=AXIS2_PLACEMENT_3D('',#773,#774,#775);
#777=PLANE('',#776);
#778=CARTESIAN_POINT('',(95.,26.,15.9831336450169));
#779=DIRECTION('',(-1.,0.,0.));
#780=DIRECTION('',(0.,0.,1.));
#781=AXIS2_PLACEMENT_3D('',#778,#779,#780);
#782=CIRCLE('',#781,3.00000000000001);
#783=CARTESIAN_POINT('',(95.,23.,15.9831336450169));
#784=VERTEX_POINT('',#783);
#785=CARTESIAN_POINT('',(95.,26.,18.983133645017));
#786=VERTEX_POINT('',#785);
#787=EDGE_CURVE('E1414',#784,#786,#782,.T.);
#788=ORIENTED_EDGE('',*,*,#787,.T.);
#789=DIRECTION('',(0.,1.,0.));
#790=VECTOR('',#789,1.);
#791=CARTESIAN_POINT('',(95.,33.,18.9831336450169));
#792=LINE('',#791,#790);
#793=CARTESIAN_POINT('',(95.,33.,18.9831336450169));
#794=VERTEX_POINT('',#793);
#795=EDGE_CURVE('E1412',#786,#794,#792,.T.);
#796=ORIENTED_EDGE('',*,*,#795,.T.);
#797=CARTESIAN_POINT('',(95.,33.,15.9831336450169));
#798=DIRECTION('',(-1.,0.,0.));
#799=DIRECTION('',(0.,0.,1.));
#800=AXIS2_PLACEMENT_3D('',#797,#798,#799);
#801=CIRCLE('',#800,3.);
#802=CARTESIAN_POINT('',(95.,36.,15.9831336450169));
#803=VERTEX_POINT('',#802);
#804=EDGE_CURVE('E1415',#794,#803,#801,.T.);
#805=ORIENTED_EDGE('',*,*,#804,.T.);
#806=DIRECTION('',(0.,0.,-1.));
#807=VECTOR('',#806,1.);
#808=CARTESIAN_POINT('',(95.,36.,-0.0168663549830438));
#809=LINE('',#808,#807);
#810=CARTESIAN_POINT('',(95.,36.,-0.016866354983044));
#811=VERTEX_POINT('',#810);
#812=EDGE_CURVE('E1406',#803,#811,#809,.T.);
#813=ORIENTED_EDGE('',*,*,#812,.T.);
#814=CARTESIAN_POINT('',(95.,33.,-0.0168663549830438));
#815=DIRECTION('',(-1.,0.,0.));
#816=DIRECTION('',(0.,0.,1.));
#817=AXIS2_PLACEMENT_3D('',#814,#815,#816);
#818=CIRCLE('',#817,3.);
#819=CARTESIAN_POINT('',(95.,33.,-3.01686635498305));
#820=VERTEX_POINT('',#819);
#821=EDGE_CURVE('E1404',#811,#820,#818,.T.);
#822=ORIENTED_EDGE('',*,*,#821,.T.);
#823=DIRECTION('',(0.,-1.,0.));
#824=VECTOR('',#823,1.);
#825=CARTESIAN_POINT('',(95.,26.,-3.01686635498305));
#826=LINE('',#825,#824);
#827=CARTESIAN_POINT('',(95.,26.,-3.01686635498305));
#828=VERTEX_POINT('',#827);
#829=EDGE_CURVE('E1381',#820,#828,#826,.T.);
#830=ORIENTED_EDGE('',*,*,#829,.T.);
#831=CARTESIAN_POINT('',(95.,26.,-0.0168663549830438));
#832=DIRECTION('',(-1.,0.,0.));
#833=DIRECTION('',(0.,0.,1.));
#834=AXIS2_PLACEMENT_3D('',#831,#832,#833);
#835=CIRCLE('',#834,3.);
#836=CARTESIAN_POINT('',(95.,23.,-0.0168663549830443));
#837=VERTEX_POINT('',#836);
#838=EDGE_CURVE('E1402',#828,#837,#835,.T.);
#839=ORIENTED_EDGE('',*,*,#838,.T.);
#840=DIRECTION('',(0.,0.,1.));
#841=VECTOR('',#840,1.);
#842=CARTESIAN_POINT('',(95.,23.,15.9831336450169));
#843=LINE('',#842,#841);
#844=EDGE_CURVE('E1410',#837,#784,#843,.T.);
#845=ORIENTED_EDGE('',*,*,#844,.T.);
#846=EDGE_LOOP('',(#788,#796,#805,#813,#822,#830,#839,#845));
#847=FACE_BOUND('',#846,.T.);
#848=DIRECTION('',(0.,-1.,0.));
#849=VECTOR('',#848,1.);
#850=CARTESIAN_POINT('',(95.,60.,-65.));
#851=LINE('',#850,#849);
#852=CARTESIAN_POINT('',(95.,1.,-65.));
#853=VERTEX_POINT('',#852);
#854=CARTESIAN_POINT('',(95.,59.5,-65.));
#855=VERTEX_POINT('',#854);
#856=EDGE_CURVE('E1106',#853,#855,#851,.F.);
#857=ORIENTED_EDGE('',*,*,#856,.T.);
#858=DIRECTION('',(0.,0.,1.));
#859=VECTOR('',#858,1.);
#860=CARTESIAN_POINT('',(95.,59.5,65.));
#861=LINE('',#860,#859);
#862=CARTESIAN_POINT('',(95.,59.5,65.));
#863=VERTEX_POINT('',#862);
#864=EDGE_CURVE('E1527',#855,#863,#861,.T.);
#865=ORIENTED_EDGE('',*,*,#864,.T.);
#866=DIRECTION('',(0.,-1.,0.));
#867=VECTOR('',#866,1.);
#868=CARTESIAN_POINT('',(95.,60.,65.));
#869=LINE('',#868,#867);
#870=CARTESIAN_POINT('',(95.,1.,65.));
#871=VERTEX_POINT('',#870);
#872=EDGE_CURVE('E1110',#863,#871,#869,.T.);
#873=ORIENTED_EDGE('',*,*,#872,.T.);
#874=DIRECTION('',(0.,0.,-1.));
#875=VECTOR('',#874,1.);
#876=CARTESIAN_POINT('',(95.,1.,-70.));
#877=LINE('',#876,#875);
#878=EDGE_CURVE('E1212',#871,#853,#877,.T.);
#879=ORIENTED_EDGE('',*,*,#878,.T.);
#880=EDGE_LOOP('',(#857,#865,#873,#879));
#881=FACE_BOUND('',#880,.T.);
#882=ADVANCED_FACE('F1777',(#847,#881),#777,.F.);
#883=CARTESIAN_POINT('',(-95.,60.,-67.));
#884=DIRECTION('',(0.,0.,1.));
#885=DIRECTION('',(1.,0.,0.));
#886=AXIS2_PLACEMENT_3D('',#883,#884,#885);
#887=PLANE('',#886);
#888=DIRECTION('',(0.,-1.,0.));
#889=VECTOR('',#888,1.);
#890=CARTESIAN_POINT('',(-79.0000000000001,60.,-67.));
#891=LINE('',#890,#889);
#892=CARTESIAN_POINT('',(-79.0000000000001,61.5,-67.));
#893=VERTEX_POINT('',#892);
#894=CARTESIAN_POINT('',(-79.0000000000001,4.99999999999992,-67.));
#895=VERTEX_POINT('',#894);
#896=EDGE_CURVE('E690',#893,#895,#891,.T.);
#897=ORIENTED_EDGE('',*,*,#896,.T.);
#898=DIRECTION('',(1.,0.,0.));
#899=VECTOR('',#898,1.);
#900=CARTESIAN_POINT('',(79.,4.99999999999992,-67.));
#901=LINE('',#900,#899);
#902=CARTESIAN_POINT('',(79.,4.99999999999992,-67.));
#903=VERTEX_POINT('',#902);
#904=EDGE_CURVE('E1157',#895,#903,#901,.T.);
#905=ORIENTED_EDGE('',*,*,#904,.T.);
#906=DIRECTION('',(0.,-1.,0.));
#907=VECTOR('',#906,1.);
#908=CARTESIAN_POINT('',(79.,60.,-67.));
#909=LINE('',#908,#907);
#910=CARTESIAN_POINT('',(79.,61.5,-67.));
#911=VERTEX_POINT('',#910);
#912=EDGE_CURVE('E708',#911,#903,#909,.T.);
#913=ORIENTED_EDGE('',*,*,#912,.F.);
#914=DIRECTION('',(-1.,0.,0.));
#915=VECTOR('',#914,1.);
#916=CARTESIAN_POINT('',(79.,61.5,-67.));
#917=LINE('',#916,#915);
#918=EDGE_CURVE('E703',#911,#893,#917,.T.);
#919=ORIENTED_EDGE('',*,*,#918,.T.);
#920=EDGE_LOOP('',(#897,#905,#913,#919));
#921=FACE_BOUND('',#920,.T.);
#922=ADVANCED_FACE('F704',(#921),#887,.T.);
#923=CARTESIAN_POINT('',(-95.,60.,67.));
#924=DIRECTION('',(0.,0.,-1.));
#925=DIRECTION('',(-1.,0.,0.));
#926=AXIS2_PLACEMENT_3D('',#923,#924,#925);
#927=PLANE('',#926);
#928=DIRECTION('',(0.,-1.,0.));
#929=VECTOR('',#928,1.);
#930=CARTESIAN_POINT('',(79.,60.,67.));
#931=LINE('',#930,#929);
#932=CARTESIAN_POINT('',(79.,61.5,67.));
#933=VERTEX_POINT('',#932);
#934=CARTESIAN_POINT('',(79.,4.99999999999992,67.));
#935=VERTEX_POINT('',#934);
#936=EDGE_CURVE('E696',#933,#935,#931,.T.);
#937=ORIENTED_EDGE('',*,*,#936,.T.);
#938=DIRECTION('',(-1.,0.,0.));
#939=VECTOR('',#938,1.);
#940=CARTESIAN_POINT('',(-79.,4.99999999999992,67.));
#941=LINE('',#940,#939);
#942=CARTESIAN_POINT('',(-79.,4.99999999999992,67.));
#943=VERTEX_POINT('',#942);
#944=EDGE_CURVE('E1163',#935,#943,#941,.T.);
#945=ORIENTED_EDGE('',*,*,#944,.T.);
#946=DIRECTION('',(0.,-1.,0.));
#947=VECTOR('',#946,1.);
#948=CARTESIAN_POINT('',(-79.,60.,67.));
#949=LINE('',#948,#947);
#950=CARTESIAN_POINT('',(-79.,61.5,67.));
#951=VERTEX_POINT('',#950);
#952=EDGE_CURVE('E1050',#951,#943,#949,.T.);
#953=ORIENTED_EDGE('',*,*,#952,.F.);
#954=DIRECTION('',(1.,0.,0.));
#955=VECTOR('',#954,1.);
#956=CARTESIAN_POINT('',(79.,61.5,67.));
#957=LINE('',#956,#955);
#958=EDGE_CURVE('E725',#951,#933,#957,.T.);
#959=ORIENTED_EDGE('',*,*,#958,.T.);
#960=EDGE_LOOP('',(#937,#945,#953,#959));
#961=FACE_BOUND('',#960,.T.);
#962=ADVANCED_FACE('F1784',(#961),#927,.T.);
#963=CARTESIAN_POINT('',(-95.,60.,-70.));
#964=DIRECTION('',(0.,0.,1.));
#965=DIRECTION('',(1.,0.,0.));
#966=AXIS2_PLACEMENT_3D('',#963,#964,#965);
#967=PLANE('',#966);
#968=DIRECTION('',(0.,-1.,0.));
#969=VECTOR('',#968,1.);
#970=CARTESIAN_POINT('',(-90.,60.,-70.));
#971=LINE('',#970,#969);
#972=CARTESIAN_POINT('',(-90.,1.,-70.));
#973=VERTEX_POINT('',#972);
#974=CARTESIAN_POINT('',(-90.,59.5,-70.));
#975=VERTEX_POINT('',#974);
#976=EDGE_CURVE('E1103',#973,#975,#971,.F.);
#977=ORIENTED_EDGE('',*,*,#976,.T.);
#978=DIRECTION('',(1.,0.,0.));
#979=VECTOR('',#978,1.);
#980=CARTESIAN_POINT('',(90.,59.5,-70.));
#981=LINE('',#980,#979);
#982=CARTESIAN_POINT('',(90.,59.5,-70.));
#983=VERTEX_POINT('',#982);
#984=EDGE_CURVE('E1519',#975,#983,#981,.T.);
#985=ORIENTED_EDGE('',*,*,#984,.T.);
#986=DIRECTION('',(0.,-1.,0.));
#987=VECTOR('',#986,1.);
#988=CARTESIAN_POINT('',(90.,60.,-70.));
#989=LINE('',#988,#987);
#990=CARTESIAN_POINT('',(90.,1.,-70.));
#991=VERTEX_POINT('',#990);
#992=EDGE_CURVE('E1105',#983,#991,#989,.T.);
#993=ORIENTED_EDGE('',*,*,#992,.T.);
#994=DIRECTION('',(-1.,0.,0.));
#995=VECTOR('',#994,1.);
#996=CARTESIAN_POINT('',(-95.,1.,-70.));
#997=LINE('',#996,#995);
#998=EDGE_CURVE('E1170',#991,#973,#997,.T.);
#999=ORIENTED_EDGE('',*,*,#998,.T.);
#1000=EDGE_LOOP('',(#977,#985,#993,#999));
#1001=FACE_BOUND('',#1000,.T.);
#1002=ADVANCED_FACE('F1788',(#1001),#967,.F.);
#1003=CARTESIAN_POINT('',(-95.,60.,-70.));
#1004=DIRECTION('',(1.,0.,0.));
#1005=DIRECTION('',(0.,0.,-1.));
#1006=AXIS2_PLACEMENT_3D('',#1003,#1004,#1005);
#1007=PLANE('',#1006);
#1008=DIRECTION('',(0.,0.,-1.));
#1009=VECTOR('',#1008,1.);
#1010=CARTESIAN_POINT('',(-95.,44.35,-48.7737095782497));
#1011=LINE('',#1010,#1009);
#1012=CARTESIAN_POINT('',(-95.,44.35,-34.7737095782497));
#1013=VERTEX_POINT('',#1012);
#1014=CARTESIAN_POINT('',(-95.,44.35,-48.7737095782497));
#1015=VERTEX_POINT('',#1014);
#1016=EDGE_CURVE('E857',#1013,#1015,#1011,.T.);
#1017=ORIENTED_EDGE('',*,*,#1016,.F.);
#1018=DIRECTION('',(0.,1.,0.));
#1019=VECTOR('',#1018,1.);
#1020=CARTESIAN_POINT('',(-95.,44.35,-34.7737095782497));
#1021=LINE('',#1020,#1019);
#1022=CARTESIAN_POINT('',(-95.,15.65,-34.7737095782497));
#1023=VERTEX_POINT('',#1022);
#1024=EDGE_CURVE('E851',#1023,#1013,#1021,.T.);
#1025=ORIENTED_EDGE('',*,*,#1024,.F.);
#1026=DIRECTION('',(0.,0.,1.));
#1027=VECTOR('',#1026,1.);
#1028=CARTESIAN_POINT('',(-95.,15.65,-48.7737095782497));
#1029=LINE('',#1028,#1027);
#1030=CARTESIAN_POINT('',(-95.,15.65,-48.7737095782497));
#1031=VERTEX_POINT('',#1030);
#1032=EDGE_CURVE('E864',#1031,#1023,#1029,.T.);
#1033=ORIENTED_EDGE('',*,*,#1032,.F.);
#1034=DIRECTION('',(0.,-1.,0.));
#1035=VECTOR('',#1034,1.);
#1036=CARTESIAN_POINT('',(-95.,44.35,-48.7737095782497));
#1037=LINE('',#1036,#1035);
#1038=EDGE_CURVE('E863',#1015,#1031,#1037,.T.);
#1039=ORIENTED_EDGE('',*,*,#1038,.F.);
#1040=EDGE_LOOP('',(#1017,#1025,#1033,#1039));
#1041=FACE_BOUND('',#1040,.T.);
#1042=CARTESIAN_POINT('',(-95.,20.5,-7.99999999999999));
#1043=DIRECTION('',(-1.,0.,0.));
#1044=DIRECTION('',(0.,0.,1.));
#1045=AXIS2_PLACEMENT_3D('',#1042,#1043,#1044);
#1046=CIRCLE('',#1045,1.6);
#1047=CARTESIAN_POINT('',(-95.,20.5,-6.39999999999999));
#1048=VERTEX_POINT('',#1047);
#1049=EDGE_CURVE('E881',#1048,#1048,#1046,.T.);
#1050=ORIENTED_EDGE('',*,*,#1049,.F.);
#1051=EDGE_LOOP('',(#1050));
#1052=FACE_BOUND('',#1051,.T.);
#1053=CARTESIAN_POINT('',(-95.,39.5,-7.99999999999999));
#1054=DIRECTION('',(-1.,0.,0.));
#1055=DIRECTION('',(0.,0.,1.));
#1056=AXIS2_PLACEMENT_3D('',#1053,#1054,#1055);
#1057=CIRCLE('',#1056,1.6);
#1058=CARTESIAN_POINT('',(-95.,39.5,-6.39999999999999));
#1059=VERTEX_POINT('',#1058);
#1060=EDGE_CURVE('E882',#1059,#1059,#1057,.T.);
#1061=ORIENTED_EDGE('',*,*,#1060,.F.);
#1062=EDGE_LOOP('',(#1061));
#1063=FACE_BOUND('',#1062,.T.);
#1064=CARTESIAN_POINT('',(-95.,41.,43.));
#1065=DIRECTION('',(-1.,0.,0.));
#1066=DIRECTION('',(0.,0.,1.));
#1067=AXIS2_PLACEMENT_3D('',#1064,#1065,#1066);
#1068=CIRCLE('',#1067,6.25000000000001);
#1069=CARTESIAN_POINT('',(-95.,41.,49.25));
#1070=VERTEX_POINT('',#1069);
#1071=EDGE_CURVE('E880',#1070,#1070,#1068,.T.);
#1072=ORIENTED_EDGE('',*,*,#1071,.F.);
#1073=EDGE_LOOP('',(#1072));
#1074=FACE_BOUND('',#1073,.T.);
#1075=DIRECTION('',(0.,0.,1.));
#1076=VECTOR('',#1075,1.);
#1077=CARTESIAN_POINT('',(-95.,27.,-2.12122461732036));
#1078=LINE('',#1077,#1076);
#1079=CARTESIAN_POINT('',(-95.,27.,-1.89754147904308));
#1080=VERTEX_POINT('',#1079);
#1081=CARTESIAN_POINT('',(-95.,27.,-1.39999999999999));
#1082=VERTEX_POINT('',#1081);
#1083=EDGE_CURVE('E856',#1080,#1082,#1078,.T.);
#1084=ORIENTED_EDGE('',*,*,#1083,.F.);
#1085=CARTESIAN_POINT('',(-95.,30.,-7.99999999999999));
#1086=DIRECTION('',(1.,0.,0.));
#1087=DIRECTION('',(0.,0.,-1.));
#1088=AXIS2_PLACEMENT_3D('',#1085,#1086,#1087);
#1089=CIRCLE('',#1088,6.79999999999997);
#1090=CARTESIAN_POINT('',(-95.,33.,-1.89754147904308));
#1091=VERTEX_POINT('',#1090);
#1092=EDGE_CURVE('E1470',#1080,#1091,#1089,.T.);
#1093=ORIENTED_EDGE('',*,*,#1092,.T.);
#1094=DIRECTION('',(0.,0.,-1.));
#1095=VECTOR('',#1094,1.);
#1096=CARTESIAN_POINT('',(-95.,33.,-2.12122461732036));
#1097=LINE('',#1096,#1095);
#1098=CARTESIAN_POINT('',(-95.,33.,-1.39999999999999));
#1099=VERTEX_POINT('',#1098);
#1100=EDGE_CURVE('E900',#1099,#1091,#1097,.T.);
#1101=ORIENTED_EDGE('',*,*,#1100,.F.);
#1102=DIRECTION('',(0.,1.,0.));
#1103=VECTOR('',#1102,1.);
#1104=CARTESIAN_POINT('',(-95.,33.,-1.39999999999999));
#1105=LINE('',#1104,#1103);
#1106=EDGE_CURVE('E906',#1082,#1099,#1105,.T.);
#1107=ORIENTED_EDGE('',*,*,#1106,.F.);
#1108=EDGE_LOOP('',(#1084,#1093,#1101,#1107));
#1109=FACE_BOUND('',#1108,.T.);
#1110=CARTESIAN_POINT('',(-95.,41.,21.));
#1111=DIRECTION('',(-1.,0.,0.));
#1112=DIRECTION('',(0.,0.,1.));
#1113=AXIS2_PLACEMENT_3D('',#1110,#1111,#1112);
#1114=CIRCLE('',#1113,6.25);
#1115=CARTESIAN_POINT('',(-95.,41.,27.25));
#1116=VERTEX_POINT('',#1115);
#1117=EDGE_CURVE('E893',#1116,#1116,#1114,.T.);
#1118=ORIENTED_EDGE('',*,*,#1117,.F.);
#1119=EDGE_LOOP('',(#1118));
#1120=FACE_BOUND('',#1119,.T.);
#1121=CARTESIAN_POINT('',(-95.,19.,21.));
#1122=DIRECTION('',(-1.,0.,0.));
#1123=DIRECTION('',(0.,0.,1.));
#1124=AXIS2_PLACEMENT_3D('',#1121,#1122,#1123);
#1125=CIRCLE('',#1124,6.25);
#1126=CARTESIAN_POINT('',(-95.,19.,27.25));
#1127=VERTEX_POINT('',#1126);
#1128=EDGE_CURVE('E890',#1127,#1127,#1125,.T.);
#1129=ORIENTED_EDGE('',*,*,#1128,.F.);
#1130=EDGE_LOOP('',(#1129));
#1131=FACE_BOUND('',#1130,.T.);
#1132=CARTESIAN_POINT('',(-95.,19.,43.));
#1133=DIRECTION('',(-1.,0.,0.));
#1134=DIRECTION('',(0.,0.,1.));
#1135=AXIS2_PLACEMENT_3D('',#1132,#1133,#1134);
#1136=CIRCLE('',#1135,6.25000000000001);
#1137=CARTESIAN_POINT('',(-95.,19.,49.25));
#1138=VERTEX_POINT('',#1137);
#1139=EDGE_CURVE('E879',#1138,#1138,#1136,.T.);
#1140=ORIENTED_EDGE('',*,*,#1139,.F.);
#1141=EDGE_LOOP('',(#1140));
#1142=FACE_BOUND('',#1141,.T.);
#1143=DIRECTION('',(0.,-1.,0.));
#1144=VECTOR('',#1143,1.);
#1145=CARTESIAN_POINT('',(-95.,60.,65.));
#1146=LINE('',#1145,#1144);
#1147=CARTESIAN_POINT('',(-95.,1.,65.));
#1148=VERTEX_POINT('',#1147);
#1149=CARTESIAN_POINT('',(-95.,59.5,65.));
#1150=VERTEX_POINT('',#1149);
#1151=EDGE_CURVE('E1097',#1148,#1150,#1146,.F.);
#1152=ORIENTED_EDGE('',*,*,#1151,.T.);
#1153=DIRECTION('',(0.,0.,-1.));
#1154=VECTOR('',#1153,1.);
#1155=CARTESIAN_POINT('',(-95.,59.5,-65.));
#1156=LINE('',#1155,#1154);
#1157=CARTESIAN_POINT('',(-95.,59.5,-65.));
#1158=VERTEX_POINT('',#1157);
#1159=EDGE_CURVE('E1521',#1150,#1158,#1156,.T.);
#1160=ORIENTED_EDGE('',*,*,#1159,.T.);
#1161=DIRECTION('',(0.,-1.,0.));
#1162=VECTOR('',#1161,1.);
#1163=CARTESIAN_POINT('',(-95.,60.,-65.));
#1164=LINE('',#1163,#1162);
#1165=CARTESIAN_POINT('',(-95.,1.,-65.));
#1166=VERTEX_POINT('',#1165);
#1167=EDGE_CURVE('E1100',#1158,#1166,#1164,.T.);
#1168=ORIENTED_EDGE('',*,*,#1167,.T.);
#1169=DIRECTION('',(0.,0.,1.));
#1170=VECTOR('',#1169,1.);
#1171=CARTESIAN_POINT('',(-95.,1.,-70.));
#1172=LINE('',#1171,#1170);
#1173=EDGE_CURVE('E1215',#1166,#1148,#1172,.T.);
#1174=ORIENTED_EDGE('',*,*,#1173,.T.);
#1175=EDGE_LOOP('',(#1152,#1160,#1168,#1174));
#1176=FACE_BOUND('',#1175,.T.);
#1177=ADVANCED_FACE('F1567',(#1041,#1052,#1063,#1074,#1109,#1120,#1131,#1142,#1176),#1007,.F.);
#1178=CARTESIAN_POINT('',(-95.,60.,70.));
#1179=DIRECTION('',(0.,0.,-1.));
#1180=DIRECTION('',(-1.,0.,0.));
#1181=AXIS2_PLACEMENT_3D('',#1178,#1179,#1180);
#1182=PLANE('',#1181);
#1183=DIRECTION('',(0.,-1.,0.));
#1184=VECTOR('',#1183,1.);
#1185=CARTESIAN_POINT('',(90.,60.,70.));
#1186=LINE('',#1185,#1184);
#1187=CARTESIAN_POINT('',(90.,1.,70.));
#1188=VERTEX_POINT('',#1187);
#1189=CARTESIAN_POINT('',(90.,59.5,70.));
#1190=VERTEX_POINT('',#1189);
#1191=EDGE_CURVE('E1093',#1188,#1190,#1186,.F.);
#1192=ORIENTED_EDGE('',*,*,#1191,.T.);
#1193=DIRECTION('',(-1.,0.,0.));
#1194=VECTOR('',#1193,1.);
#1195=CARTESIAN_POINT('',(-90.,59.5,70.));
#1196=LINE('',#1195,#1194);
#1197=CARTESIAN_POINT('',(-90.,59.5,70.));
#1198=VERTEX_POINT('',#1197);
#1199=EDGE_CURVE('E13',#1190,#1198,#1196,.T.);
#1200=ORIENTED_EDGE('',*,*,#1199,.T.);
#1201=DIRECTION('',(0.,-1.,0.));
#1202=VECTOR('',#1201,1.);
#1203=CARTESIAN_POINT('',(-90.,60.,70.));
#1204=LINE('',#1203,#1202);
#1205=CARTESIAN_POINT('',(-90.,1.,70.));
#1206=VERTEX_POINT('',#1205);
#1207=EDGE_CURVE('E1094',#1198,#1206,#1204,.T.);
#1208=ORIENTED_EDGE('',*,*,#1207,.T.);
#1209=DIRECTION('',(1.,0.,0.));
#1210=VECTOR('',#1209,1.);
#1211=CARTESIAN_POINT('',(-95.,1.,70.));
#1212=LINE('',#1211,#1210);
#1213=EDGE_CURVE('E1224',#1206,#1188,#1212,.T.);
#1214=ORIENTED_EDGE('',*,*,#1213,.T.);
#1215=EDGE_LOOP('',(#1192,#1200,#1208,#1214));
#1216=FACE_BOUND('',#1215,.T.);
#1217=ADVANCED_FACE('F1633',(#1216),#1182,.F.);
#1218=CARTESIAN_POINT('',(90.,60.,-65.));
#1219=DIRECTION('',(0.,1.,0.));
#1220=DIRECTION('',(0.,0.,1.));
#1221=AXIS2_PLACEMENT_3D('',#1218,#1219,#1220);
#1222=CIRCLE('',#1221,4.5);
#1223=CARTESIAN_POINT('',(94.5,60.,-65.));
#1224=VERTEX_POINT('',#1223);
#1225=CARTESIAN_POINT('',(90.,60.,-69.5));
#1226=VERTEX_POINT('',#1225);
#1227=EDGE_CURVE('E1508',#1224,#1226,#1222,.T.);
#1228=ORIENTED_EDGE('',*,*,#1227,.T.);
#1229=DIRECTION('',(-1.,0.,0.));
#1230=VECTOR('',#1229,1.);
#1231=CARTESIAN_POINT('',(-90.,60.,-69.5));
#1232=LINE('',#1231,#1230);
#1233=CARTESIAN_POINT('',(-90.,60.,-69.5));
#1234=VERTEX_POINT('',#1233);
#1235=EDGE_CURVE('E1513',#1226,#1234,#1232,.T.);
#1236=ORIENTED_EDGE('',*,*,#1235,.T.);
#1237=CARTESIAN_POINT('',(-90.,60.,-65.));
#1238=DIRECTION('',(0.,1.,0.));
#1239=DIRECTION('',(0.,0.,1.));
#1240=AXIS2_PLACEMENT_3D('',#1237,#1238,#1239);
#1241=CIRCLE('',#1240,4.5);
#1242=CARTESIAN_POINT('',(-94.5,60.,-65.));
#1243=VERTEX_POINT('',#1242);
#1244=EDGE_CURVE('E1511',#1234,#1243,#1241,.T.);
#1245=ORIENTED_EDGE('',*,*,#1244,.T.);
#1246=DIRECTION('',(0.,0.,1.));
#1247=VECTOR('',#1246,1.);
#1248=CARTESIAN_POINT('',(-94.5,60.,65.));
#1249=LINE('',#1248,#1247);
#1250=CARTESIAN_POINT('',(-94.5,60.,65.));
#1251=VERTEX_POINT('',#1250);
#1252=EDGE_CURVE('E1506',#1243,#1251,#1249,.T.);
#1253=ORIENTED_EDGE('',*,*,#1252,.T.);
#1254=CARTESIAN_POINT('',(-90.,60.,65.));
#1255=DIRECTION('',(0.,1.,0.));
#1256=DIRECTION('',(0.,0.,1.));
#1257=AXIS2_PLACEMENT_3D('',#1254,#1255,#1256);
#1258=CIRCLE('',#1257,4.5);
#1259=CARTESIAN_POINT('',(-90.,60.,69.5));
#1260=VERTEX_POINT('',#1259);
#1261=EDGE_CURVE('E1504',#1251,#1260,#1258,.T.);
#1262=ORIENTED_EDGE('',*,*,#1261,.T.);
#1263=DIRECTION('',(1.,0.,0.));
#1264=VECTOR('',#1263,1.);
#1265=CARTESIAN_POINT('',(90.,60.,69.5));
#1266=LINE('',#1265,#1264);
#1267=CARTESIAN_POINT('',(90.,60.,69.5));
#1268=VERTEX_POINT('',#1267);
#1269=EDGE_CURVE('E1498',#1260,#1268,#1266,.T.);
#1270=ORIENTED_EDGE('',*,*,#1269,.T.);
#1271=CARTESIAN_POINT('',(90.,60.,65.));
#1272=DIRECTION('',(0.,1.,0.));
#1273=DIRECTION('',(0.,0.,1.));
#1274=AXIS2_PLACEMENT_3D('',#1271,#1272,#1273);
#1275=CIRCLE('',#1274,4.5);
#1276=CARTESIAN_POINT('',(94.5,60.,65.));
#1277=VERTEX_POINT('',#1276);
#1278=EDGE_CURVE('E1505',#1268,#1277,#1275,.T.);
#1279=ORIENTED_EDGE('',*,*,#1278,.T.);
#1280=DIRECTION('',(0.,0.,-1.));
#1281=VECTOR('',#1280,1.);
#1282=CARTESIAN_POINT('',(94.5,60.,-65.));
#1283=LINE('',#1282,#1281);
#1284=EDGE_CURVE('E1507',#1277,#1224,#1283,.T.);
#1285=ORIENTED_EDGE('',*,*,#1284,.T.);
#1286=EDGE_LOOP('',(#1228,#1236,#1245,#1253,#1262,#1270,#1279,#1285));
#1287=FACE_BOUND('',#1286,.T.);
#1288=DIRECTION('',(-0.707106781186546,0.,0.707106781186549));
#1289=VECTOR('',#1288,1.);
#1290=CARTESIAN_POINT('',(-93.5,60.,-54.6213203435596));
#1291=LINE('',#1290,#1289);
#1292=CARTESIAN_POINT('',(-79.6213203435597,60.,-68.5));
#1293=VERTEX_POINT('',#1292);
#1294=CARTESIAN_POINT('',(-93.5,60.,-54.6213203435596));
#1295=VERTEX_POINT('',#1294);
#1296=EDGE_CURVE('E734',#1293,#1295,#1291,.T.);
#1297=ORIENTED_EDGE('',*,*,#1296,.F.);
#1298=DIRECTION('',(-1.,0.,0.));
#1299=VECTOR('',#1298,1.);
#1300=CARTESIAN_POINT('',(79.6213203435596,60.,-68.5));
#1301=LINE('',#1300,#1299);
#1302=CARTESIAN_POINT('',(79.6213203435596,60.,-68.5));
#1303=VERTEX_POINT('',#1302);
#1304=EDGE_CURVE('E744',#1303,#1293,#1301,.T.);
#1305=ORIENTED_EDGE('',*,*,#1304,.F.);
#1306=DIRECTION('',(-0.707106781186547,0.,-0.707106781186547));
#1307=VECTOR('',#1306,1.);
#1308=CARTESIAN_POINT('',(79.6213203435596,60.,-68.5));
#1309=LINE('',#1308,#1307);
#1310=CARTESIAN_POINT('',(93.5,60.,-54.6213203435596));
#1311=VERTEX_POINT('',#1310);
#1312=EDGE_CURVE('E771',#1311,#1303,#1309,.T.);
#1313=ORIENTED_EDGE('',*,*,#1312,.F.);
#1314=DIRECTION('',(0.,0.,-1.));
#1315=VECTOR('',#1314,1.);
#1316=CARTESIAN_POINT('',(93.5,60.,54.6213203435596));
#1317=LINE('',#1316,#1315);
#1318=CARTESIAN_POINT('',(93.5,60.,54.6213203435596));
#1319=VERTEX_POINT('',#1318);
#1320=EDGE_CURVE('E772',#1319,#1311,#1317,.T.);
#1321=ORIENTED_EDGE('',*,*,#1320,.F.);
#1322=DIRECTION('',(0.707106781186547,0.,-0.707106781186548));
#1323=VECTOR('',#1322,1.);
#1324=CARTESIAN_POINT('',(93.5,60.,54.6213203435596));
#1325=LINE('',#1324,#1323);
#1326=CARTESIAN_POINT('',(79.6213203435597,60.,68.5));
#1327=VERTEX_POINT('',#1326);
#1328=EDGE_CURVE('E767',#1327,#1319,#1325,.T.);
#1329=ORIENTED_EDGE('',*,*,#1328,.F.);
#1330=DIRECTION('',(1.,0.,0.));
#1331=VECTOR('',#1330,1.);
#1332=CARTESIAN_POINT('',(79.6213203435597,60.,68.5));
#1333=LINE('',#1332,#1331);
#1334=CARTESIAN_POINT('',(-79.6213203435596,60.,68.5));
#1335=VERTEX_POINT('',#1334);
#1336=EDGE_CURVE('E762',#1335,#1327,#1333,.T.);
#1337=ORIENTED_EDGE('',*,*,#1336,.F.);
#1338=DIRECTION('',(0.707106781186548,0.,0.707106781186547));
#1339=VECTOR('',#1338,1.);
#1340=CARTESIAN_POINT('',(-79.6213203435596,60.,68.5));
#1341=LINE('',#1340,#1339);
#1342=CARTESIAN_POINT('',(-93.5,60.,54.6213203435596));
#1343=VERTEX_POINT('',#1342);
#1344=EDGE_CURVE('E761',#1343,#1335,#1341,.T.);
#1345=ORIENTED_EDGE('',*,*,#1344,.F.);
#1346=DIRECTION('',(0.,0.,1.));
#1347=VECTOR('',#1346,1.);
#1348=CARTESIAN_POINT('',(-93.5,60.,-54.6213203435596));
#1349=LINE('',#1348,#1347);
#1350=EDGE_CURVE('E759',#1295,#1343,#1349,.T.);
#1351=ORIENTED_EDGE('',*,*,#1350,.F.);
#1352=EDGE_LOOP('',(#1297,#1305,#1313,#1321,#1329,#1337,#1345,#1351));
#1353=FACE_BOUND('',#1352,.T.);
#1354=CARTESIAN_POINT('',(-89.5177669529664,60.,-64.5177669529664));
#1355=DIRECTION('',(0.,-1.,0.));
#1356=DIRECTION('',(0.,0.,-1.));
#1357=AXIS2_PLACEMENT_3D('',#1354,#1355,#1356);
#1358=CIRCLE('',#1357,2.15);
#1359=CARTESIAN_POINT('',(-89.5177669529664,60.,-66.6677669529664));
#1360=VERTEX_POINT('',#1359);
#1361=EDGE_CURVE('E1014',#1360,#1360,#1358,.T.);
#1362=ORIENTED_EDGE('',*,*,#1361,.T.);
#1363=EDGE_LOOP('',(#1362));
#1364=FACE_BOUND('',#1363,.T.);
#1365=CARTESIAN_POINT('',(89.5177669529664,60.,-64.5177669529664));
#1366=DIRECTION('',(0.,-1.,0.));
#1367=DIRECTION('',(0.,0.,-1.));
#1368=AXIS2_PLACEMENT_3D('',#1365,#1366,#1367);
#1369=CIRCLE('',#1368,2.15);
#1370=CARTESIAN_POINT('',(89.5177669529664,60.,-66.6677669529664));
#1371=VERTEX_POINT('',#1370);
#1372=EDGE_CURVE('E1006',#1371,#1371,#1369,.T.);
#1373=ORIENTED_EDGE('',*,*,#1372,.T.);
#1374=EDGE_LOOP('',(#1373));
#1375=FACE_BOUND('',#1374,.T.);
#1376=CARTESIAN_POINT('',(89.5177669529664,60.,64.5177669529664));
#1377=DIRECTION('',(0.,-1.,0.));
#1378=DIRECTION('',(0.,0.,-1.));
#1379=AXIS2_PLACEMENT_3D('',#1376,#1377,#1378);
#1380=CIRCLE('',#1379,2.15);
#1381=CARTESIAN_POINT('',(89.5177669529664,60.,62.3677669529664));
#1382=VERTEX_POINT('',#1381);
#1383=EDGE_CURVE('E1005',#1382,#1382,#1380,.T.);
#1384=ORIENTED_EDGE('',*,*,#1383,.T.);
#1385=EDGE_LOOP('',(#1384));
#1386=FACE_BOUND('',#1385,.T.);
#1387=CARTESIAN_POINT('',(-89.5177669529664,60.,64.5177669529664));
#1388=DIRECTION('',(0.,-1.,0.));
#1389=DIRECTION('',(0.,0.,-1.));
#1390=AXIS2_PLACEMENT_3D('',#1387,#1388,#1389);
#1391=CIRCLE('',#1390,2.15);
#1392=CARTESIAN_POINT('',(-89.5177669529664,60.,62.3677669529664));
#1393=VERTEX_POINT('',#1392);
#1394=EDGE_CURVE('E1018',#1393,#1393,#1391,.T.);
#1395=ORIENTED_EDGE('',*,*,#1394,.T.);
#1396=EDGE_LOOP('',(#1395));
#1397=FACE_BOUND('',#1396,.T.);
#1398=ADVANCED_FACE('F1624',(#1287,#1353,#1364,#1375,#1386,#1397),#23,.T.);
#1399=CARTESIAN_POINT('',(0.,0.,0.));
#1400=DIRECTION('',(0.,1.,0.));
#1401=DIRECTION('',(0.,0.,1.));
#1402=AXIS2_PLACEMENT_3D('',#1399,#1400,#1401);
#1403=PLANE('',#1402);
#1404=CARTESIAN_POINT('',(-90.,0.,-65.));
#1405=DIRECTION('',(0.,1.,0.));
#1406=DIRECTION('',(0.,0.,1.));
#1407=AXIS2_PLACEMENT_3D('',#1404,#1405,#1406);
#1408=CIRCLE('',#1407,4.);
#1409=CARTESIAN_POINT('',(-94.,0.,-65.));
#1410=VERTEX_POINT('',#1409);
#1411=CARTESIAN_POINT('',(-90.,0.,-69.));
#1412=VERTEX_POINT('',#1411);
#1413=EDGE_CURVE('E1205',#1410,#1412,#1408,.F.);
#1414=ORIENTED_EDGE('',*,*,#1413,.T.);
#1415=DIRECTION('',(1.,0.,0.));
#1416=VECTOR('',#1415,1.);
#1417=CARTESIAN_POINT('',(0.,0.,-69.));
#1418=LINE('',#1417,#1416);
#1419=CARTESIAN_POINT('',(90.,0.,-69.));
#1420=VERTEX_POINT('',#1419);
#1421=EDGE_CURVE('E1204',#1412,#1420,#1418,.T.);
#1422=ORIENTED_EDGE('',*,*,#1421,.T.);
#1423=CARTESIAN_POINT('',(90.,0.,-65.));
#1424=DIRECTION('',(0.,1.,0.));
#1425=DIRECTION('',(0.,0.,1.));
#1426=AXIS2_PLACEMENT_3D('',#1423,#1424,#1425);
#1427=CIRCLE('',#1426,4.);
#1428=CARTESIAN_POINT('',(94.,0.,-65.));
#1429=VERTEX_POINT('',#1428);
#1430=EDGE_CURVE('E1198',#1420,#1429,#1427,.F.);
#1431=ORIENTED_EDGE('',*,*,#1430,.T.);
#1432=DIRECTION('',(0.,0.,1.));
#1433=VECTOR('',#1432,1.);
#1434=CARTESIAN_POINT('',(94.,0.,0.));
#1435=LINE('',#1434,#1433);
#1436=CARTESIAN_POINT('',(94.,0.,65.));
#1437=VERTEX_POINT('',#1436);
#1438=EDGE_CURVE('E1197',#1429,#1437,#1435,.T.);
#1439=ORIENTED_EDGE('',*,*,#1438,.T.);
#1440=CARTESIAN_POINT('',(90.,0.,65.));
#1441=DIRECTION('',(0.,1.,0.));
#1442=DIRECTION('',(0.,0.,1.));
#1443=AXIS2_PLACEMENT_3D('',#1440,#1441,#1442);
#1444=CIRCLE('',#1443,4.);
#1445=CARTESIAN_POINT('',(90.,0.,69.));
#1446=VERTEX_POINT('',#1445);
#1447=EDGE_CURVE('E1194',#1437,#1446,#1444,.F.);
#1448=ORIENTED_EDGE('',*,*,#1447,.T.);
#1449=DIRECTION('',(-1.,0.,0.));
#1450=VECTOR('',#1449,1.);
#1451=CARTESIAN_POINT('',(0.,0.,69.));
#1452=LINE('',#1451,#1450);
#1453=CARTESIAN_POINT('',(-90.,0.,69.));
#1454=VERTEX_POINT('',#1453);
#1455=EDGE_CURVE('E1187',#1446,#1454,#1452,.T.);
#1456=ORIENTED_EDGE('',*,*,#1455,.T.);
#1457=CARTESIAN_POINT('',(-90.,0.,65.));
#1458=DIRECTION('',(0.,1.,0.));
#1459=DIRECTION('',(0.,0.,1.));
#1460=AXIS2_PLACEMENT_3D('',#1457,#1458,#1459);
#1461=CIRCLE('',#1460,4.);
#1462=CARTESIAN_POINT('',(-94.,0.,65.));
#1463=VERTEX_POINT('',#1462);
#1464=EDGE_CURVE('E1195',#1454,#1463,#1461,.F.);
#1465=ORIENTED_EDGE('',*,*,#1464,.T.);
#1466=DIRECTION('',(0.,0.,-1.));
#1467=VECTOR('',#1466,1.);
#1468=CARTESIAN_POINT('',(-94.,0.,0.));
#1469=LINE('',#1468,#1467);
#1470=EDGE_CURVE('E1199',#1463,#1410,#1469,.T.);
#1471=ORIENTED_EDGE('',*,*,#1470,.T.);
#1472=EDGE_LOOP('',(#1414,#1422,#1431,#1439,#1448,#1456,#1465,#1471));
#1473=FACE_BOUND('',#1472,.T.);
#1474=CARTESIAN_POINT('',(-89.5177669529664,0.,-64.5177669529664));
#1475=DIRECTION('',(0.,-1.,0.));
#1476=DIRECTION('',(0.,0.,-1.));
#1477=AXIS2_PLACEMENT_3D('',#1474,#1475,#1476);
#1478=CIRCLE('',#1477,3.8);
#1479=CARTESIAN_POINT('',(-89.5177669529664,0.,-68.3177669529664));
#1480=VERTEX_POINT('',#1479);
#1481=EDGE_CURVE('E1033',#1480,#1480,#1478,.T.);
#1482=ORIENTED_EDGE('',*,*,#1481,.F.);
#1483=EDGE_LOOP('',(#1482));
#1484=FACE_BOUND('',#1483,.T.);
#1485=CARTESIAN_POINT('',(-89.5177669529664,0.,64.5177669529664));
#1486=DIRECTION('',(0.,-1.,0.));
#1487=DIRECTION('',(0.,0.,-1.));
#1488=AXIS2_PLACEMENT_3D('',#1485,#1486,#1487);
#1489=CIRCLE('',#1488,3.8);
#1490=CARTESIAN_POINT('',(-89.5177669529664,0.,60.7177669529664));
#1491=VERTEX_POINT('',#1490);
#1492=EDGE_CURVE('E1027',#1491,#1491,#1489,.T.);
#1493=ORIENTED_EDGE('',*,*,#1492,.F.);
#1494=EDGE_LOOP('',(#1493));
#1495=FACE_BOUND('',#1494,.T.);
#1496=CARTESIAN_POINT('',(89.5177669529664,0.,64.5177669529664));
#1497=DIRECTION('',(0.,-1.,0.));
#1498=DIRECTION('',(0.,0.,-1.));
#1499=AXIS2_PLACEMENT_3D('',#1496,#1497,#1498);
#1500=CIRCLE('',#1499,3.8);
#1501=CARTESIAN_POINT('',(89.5177669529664,0.,60.7177669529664));
#1502=VERTEX_POINT('',#1501);
#1503=EDGE_CURVE('E1030',#1502,#1502,#1500,.T.);
#1504=ORIENTED_EDGE('',*,*,#1503,.F.);
#1505=EDGE_LOOP('',(#1504));
#1506=FACE_BOUND('',#1505,.T.);
#1507=CARTESIAN_POINT('',(89.5177669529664,0.,-64.5177669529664));
#1508=DIRECTION('',(0.,-1.,0.));
#1509=DIRECTION('',(0.,0.,-1.));
#1510=AXIS2_PLACEMENT_3D('',#1507,#1508,#1509);
#1511=CIRCLE('',#1510,3.8);
#1512=CARTESIAN_POINT('',(89.5177669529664,0.,-68.3177669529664));
#1513=VERTEX_POINT('',#1512);
#1514=EDGE_CURVE('E1032',#1513,#1513,#1511,.T.);
#1515=ORIENTED_EDGE('',*,*,#1514,.F.);
#1516=EDGE_LOOP('',(#1515));
#1517=FACE_BOUND('',#1516,.T.);
#1518=ADVANCED_FACE('F1581',(#1473,#1484,#1495,#1506,#1517),#1403,.F.);
#1519=CARTESIAN_POINT('',(-90.,60.,65.));
#1520=DIRECTION('',(0.,-1.,0.));
#1521=DIRECTION('',(0.,0.,-1.));
#1522=AXIS2_PLACEMENT_3D('',#1519,#1520,#1521);
#1523=CYLINDRICAL_SURFACE('',#1522,5.);
#1524=ORIENTED_EDGE('',*,*,#1207,.F.);
#1525=CARTESIAN_POINT('',(-90.,59.5,65.));
#1526=DIRECTION('',(0.,1.,0.));
#1527=DIRECTION('',(0.,0.,1.));
#1528=AXIS2_PLACEMENT_3D('',#1525,#1526,#1527);
#1529=CIRCLE('',#1528,5.);
#1530=EDGE_CURVE('E1528',#1198,#1150,#1529,.F.);
#1531=ORIENTED_EDGE('',*,*,#1530,.T.);
#1532=ORIENTED_EDGE('',*,*,#1151,.F.);
#1533=CARTESIAN_POINT('',(-90.,1.,65.));
#1534=DIRECTION('',(0.,1.,0.));
#1535=DIRECTION('',(0.,0.,1.));
#1536=AXIS2_PLACEMENT_3D('',#1533,#1534,#1535);
#1537=CIRCLE('',#1536,5.);
#1538=EDGE_CURVE('E1219',#1148,#1206,#1537,.T.);
#1539=ORIENTED_EDGE('',*,*,#1538,.T.);
#1540=EDGE_LOOP('',(#1524,#1531,#1532,#1539));
#1541=FACE_BOUND('',#1540,.T.);
#1542=ADVANCED_FACE('F1562',(#1541),#1523,.T.);
#1543=CARTESIAN_POINT('',(-90.,60.,-65.));
#1544=DIRECTION('',(0.,-1.,0.));
#1545=DIRECTION('',(0.,0.,-1.));
#1546=AXIS2_PLACEMENT_3D('',#1543,#1544,#1545);
#1547=CYLINDRICAL_SURFACE('',#1546,5.);
#1548=ORIENTED_EDGE('',*,*,#1167,.F.);
#1549=CARTESIAN_POINT('',(-90.,59.5,-65.));
#1550=DIRECTION('',(0.,1.,0.));
#1551=DIRECTION('',(0.,0.,1.));
#1552=AXIS2_PLACEMENT_3D('',#1549,#1550,#1551);
#1553=CIRCLE('',#1552,5.);
#1554=EDGE_CURVE('E1516',#1158,#975,#1553,.F.);
#1555=ORIENTED_EDGE('',*,*,#1554,.T.);
#1556=ORIENTED_EDGE('',*,*,#976,.F.);
#1557=CARTESIAN_POINT('',(-90.,1.,-65.));
#1558=DIRECTION('',(0.,1.,0.));
#1559=DIRECTION('',(0.,0.,1.));
#1560=AXIS2_PLACEMENT_3D('',#1557,#1558,#1559);
#1561=CIRCLE('',#1560,5.);
#1562=EDGE_CURVE('E1210',#973,#1166,#1561,.T.);
#1563=ORIENTED_EDGE('',*,*,#1562,.T.);
#1564=EDGE_LOOP('',(#1548,#1555,#1556,#1563));
#1565=FACE_BOUND('',#1564,.T.);
#1566=ADVANCED_FACE('F2868',(#1565),#1547,.T.);
#1567=CARTESIAN_POINT('',(90.,60.,-65.));
#1568=DIRECTION('',(0.,-1.,0.));
#1569=DIRECTION('',(0.,0.,-1.));
#1570=AXIS2_PLACEMENT_3D('',#1567,#1568,#1569);
#1571=CYLINDRICAL_SURFACE('',#1570,5.);
#1572=ORIENTED_EDGE('',*,*,#992,.F.);
#1573=CARTESIAN_POINT('',(90.,59.5,-65.));
#1574=DIRECTION('',(0.,1.,0.));
#1575=DIRECTION('',(0.,0.,1.));
#1576=AXIS2_PLACEMENT_3D('',#1573,#1574,#1575);
#1577=CIRCLE('',#1576,5.);
#1578=EDGE_CURVE('E1525',#983,#855,#1577,.F.);
#1579=ORIENTED_EDGE('',*,*,#1578,.T.);
#1580=ORIENTED_EDGE('',*,*,#856,.F.);
#1581=CARTESIAN_POINT('',(90.,1.,-65.));
#1582=DIRECTION('',(0.,1.,0.));
#1583=DIRECTION('',(0.,0.,1.));
#1584=AXIS2_PLACEMENT_3D('',#1581,#1582,#1583);
#1585=CIRCLE('',#1584,5.);
#1586=EDGE_CURVE('E1208',#853,#991,#1585,.T.);
#1587=ORIENTED_EDGE('',*,*,#1586,.T.);
#1588=EDGE_LOOP('',(#1572,#1579,#1580,#1587));
#1589=FACE_BOUND('',#1588,.T.);
#1590=ADVANCED_FACE('F2860',(#1589),#1571,.T.);
#1591=CARTESIAN_POINT('',(90.,60.,65.));
#1592=DIRECTION('',(0.,-1.,0.));
#1593=DIRECTION('',(0.,0.,-1.));
#1594=AXIS2_PLACEMENT_3D('',#1591,#1592,#1593);
#1595=CYLINDRICAL_SURFACE('',#1594,5.);
#1596=ORIENTED_EDGE('',*,*,#872,.F.);
#1597=CARTESIAN_POINT('',(90.,59.5,65.));
#1598=DIRECTION('',(0.,1.,0.));
#1599=DIRECTION('',(0.,0.,1.));
#1600=AXIS2_PLACEMENT_3D('',#1597,#1598,#1599);
#1601=CIRCLE('',#1600,5.);
#1602=EDGE_CURVE('E173',#863,#1190,#1601,.F.);
#1603=ORIENTED_EDGE('',*,*,#1602,.T.);
#1604=ORIENTED_EDGE('',*,*,#1191,.F.);
#1605=CARTESIAN_POINT('',(90.,1.,65.));
#1606=DIRECTION('',(0.,1.,0.));
#1607=DIRECTION('',(0.,0.,1.));
#1608=AXIS2_PLACEMENT_3D('',#1605,#1606,#1607);
#1609=CIRCLE('',#1608,5.);
#1610=EDGE_CURVE('E1216',#1188,#871,#1609,.T.);
#1611=ORIENTED_EDGE('',*,*,#1610,.T.);
#1612=EDGE_LOOP('',(#1596,#1603,#1604,#1611));
#1613=FACE_BOUND('',#1612,.T.);
#1614=ADVANCED_FACE('F1769',(#1613),#1595,.T.);
#1615=CARTESIAN_POINT('',(38.7703566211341,13.,-6.41661167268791));
#1616=DIRECTION('',(0.,1.,0.));
#1617=DIRECTION('',(0.,0.,1.));
#1618=AXIS2_PLACEMENT_3D('',#1615,#1616,#1617);
#1619=PLANE('',#1618);
#1620=CARTESIAN_POINT('',(38.7703566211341,13.,-6.41661167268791));
#1621=DIRECTION('',(0.,1.,0.));
#1622=DIRECTION('',(0.,0.,1.));
#1623=AXIS2_PLACEMENT_3D('',#1620,#1621,#1622);
#1624=CIRCLE('',#1623,5.);
#1625=CARTESIAN_POINT('',(38.7703566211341,13.,-1.41661167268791));
#1626=VERTEX_POINT('',#1625);
#1627=EDGE_CURVE('E1087',#1626,#1626,#1624,.T.);
#1628=ORIENTED_EDGE('',*,*,#1627,.T.);
#1629=EDGE_LOOP('',(#1628));
#1630=FACE_BOUND('',#1629,.T.);
#1631=CARTESIAN_POINT('',(38.7703566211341,13.,-6.41661167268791));
#1632=DIRECTION('',(0.,1.,0.));
#1633=DIRECTION('',(0.,0.,1.));
#1634=AXIS2_PLACEMENT_3D('',#1631,#1632,#1633);
#1635=CIRCLE('',#1634,2.85);
#1636=CARTESIAN_POINT('',(38.7703566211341,13.,-3.56661167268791));
#1637=VERTEX_POINT('',#1636);
#1638=EDGE_CURVE('E1072',#1637,#1637,#1635,.T.);
#1639=ORIENTED_EDGE('',*,*,#1638,.F.);
#1640=EDGE_LOOP('',(#1639));
#1641=FACE_BOUND('',#1640,.T.);
#1642=ADVANCED_FACE('F1770',(#1630,#1641),#1619,.T.);
#1643=CARTESIAN_POINT('',(38.7703566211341,13.,-6.41661167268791));
#1644=DIRECTION('',(0.,-1.,0.));
#1645=DIRECTION('',(0.,0.,-1.));
#1646=AXIS2_PLACEMENT_3D('',#1643,#1644,#1645);
#1647=CYLINDRICAL_SURFACE('',#1646,5.);
#1648=CARTESIAN_POINT('',(38.7703566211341,6.00000000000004,-6.41661167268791));
#1649=DIRECTION('',(0.,1.,0.));
#1650=DIRECTION('',(0.,0.,1.));
#1651=AXIS2_PLACEMENT_3D('',#1648,#1649,#1650);
#1652=CIRCLE('',#1651,5.);
#1653=CARTESIAN_POINT('',(38.7703566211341,6.00000000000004,-1.41661167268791));
#1654=VERTEX_POINT('',#1653);
#1655=EDGE_CURVE('E1284',#1654,#1654,#1652,.T.);
#1656=ORIENTED_EDGE('',*,*,#1655,.T.);
#1657=EDGE_LOOP('',(#1656));
#1658=FACE_BOUND('',#1657,.T.);
#1659=ORIENTED_EDGE('',*,*,#1627,.F.);
#1660=EDGE_LOOP('',(#1659));
#1661=FACE_BOUND('',#1660,.T.);
#1662=ADVANCED_FACE('F1762',(#1658,#1661),#1647,.T.);
#1663=CARTESIAN_POINT('',(38.7703566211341,13.,-6.41661167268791));
#1664=DIRECTION('',(0.,-1.,0.));
#1665=DIRECTION('',(0.,0.,-1.));
#1666=AXIS2_PLACEMENT_3D('',#1663,#1664,#1665);
#1667=CYLINDRICAL_SURFACE('',#1666,2.85);
#1668=ORIENTED_EDGE('',*,*,#1638,.T.);
#1669=EDGE_LOOP('',(#1668));
#1670=FACE_BOUND('',#1669,.T.);
#1671=CARTESIAN_POINT('',(38.7703566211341,3.,-6.41661167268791));
#1672=DIRECTION('',(0.,1.,0.));
#1673=DIRECTION('',(0.,0.,1.));
#1674=AXIS2_PLACEMENT_3D('',#1671,#1672,#1673);
#1675=CIRCLE('',#1674,2.85);
#1676=CARTESIAN_POINT('',(38.7703566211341,3.,-3.56661167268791));
#1677=VERTEX_POINT('',#1676);
#1678=EDGE_CURVE('E1111',#1677,#1677,#1675,.F.);
#1679=ORIENTED_EDGE('',*,*,#1678,.T.);
#1680=EDGE_LOOP('',(#1679));
#1681=FACE_BOUND('',#1680,.T.);
#1682=ADVANCED_FACE('F1765',(#1670,#1681),#1667,.F.);
#1683=ORIENTED_EDGE('',*,*,#1678,.F.);
#1684=EDGE_LOOP('',(#1683));
#1685=FACE_BOUND('',#1684,.T.);
#1686=ADVANCED_FACE('F1717',(#1685),#335,.T.);
#1687=CARTESIAN_POINT('',(1.27035662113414,13.,-54.4166116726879));
#1688=DIRECTION('',(0.,1.,0.));
#1689=DIRECTION('',(0.,0.,1.));
#1690=AXIS2_PLACEMENT_3D('',#1687,#1688,#1689);
#1691=PLANE('',#1690);
#1692=CARTESIAN_POINT('',(1.27035662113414,13.,-54.4166116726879));
#1693=DIRECTION('',(0.,1.,0.));
#1694=DIRECTION('',(0.,0.,1.));
#1695=AXIS2_PLACEMENT_3D('',#1692,#1693,#1694);
#1696=CIRCLE('',#1695,4.99999999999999);
#1697=CARTESIAN_POINT('',(1.27035662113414,13.,-49.4166116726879));
#1698=VERTEX_POINT('',#1697);
#1699=EDGE_CURVE('E1063',#1698,#1698,#1696,.T.);
#1700=ORIENTED_EDGE('',*,*,#1699,.T.);
#1701=EDGE_LOOP('',(#1700));
#1702=FACE_BOUND('',#1701,.T.);
#1703=CARTESIAN_POINT('',(1.27035662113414,13.,-54.4166116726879));
#1704=DIRECTION('',(0.,1.,0.));
#1705=DIRECTION('',(0.,0.,1.));
#1706=AXIS2_PLACEMENT_3D('',#1703,#1704,#1705);
#1707=CIRCLE('',#1706,2.);
#1708=CARTESIAN_POINT('',(1.27035662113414,13.,-52.4166116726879));
#1709=VERTEX_POINT('',#1708);
#1710=EDGE_CURVE('E1069',#1709,#1709,#1707,.T.);
#1711=ORIENTED_EDGE('',*,*,#1710,.F.);
#1712=EDGE_LOOP('',(#1711));
#1713=FACE_BOUND('',#1712,.T.);
#1714=ADVANCED_FACE('F1713',(#1702,#1713),#1691,.T.);
#1715=CARTESIAN_POINT('',(1.27035662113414,13.,-54.4166116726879));
#1716=DIRECTION('',(0.,-1.,0.));
#1717=DIRECTION('',(0.,0.,-1.));
#1718=AXIS2_PLACEMENT_3D('',#1715,#1716,#1717);
#1719=CYLINDRICAL_SURFACE('',#1718,4.99999999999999);
#1720=CARTESIAN_POINT('',(1.27035662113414,6.00000000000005,-54.4166116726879));
#1721=DIRECTION('',(0.,1.,0.));
#1722=DIRECTION('',(0.,0.,1.));
#1723=AXIS2_PLACEMENT_3D('',#1720,#1721,#1722);
#1724=CIRCLE('',#1723,4.99999999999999);
#1725=CARTESIAN_POINT('',(1.27035662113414,6.00000000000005,-49.4166116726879));
#1726=VERTEX_POINT('',#1725);
#1727=EDGE_CURVE('E1286',#1726,#1726,#1724,.T.);
#1728=ORIENTED_EDGE('',*,*,#1727,.T.);
#1729=EDGE_LOOP('',(#1728));
#1730=FACE_BOUND('',#1729,.T.);
#1731=ORIENTED_EDGE('',*,*,#1699,.F.);
#1732=EDGE_LOOP('',(#1731));
#1733=FACE_BOUND('',#1732,.T.);
#1734=ADVANCED_FACE('F1708',(#1730,#1733),#1719,.T.);
#1735=CARTESIAN_POINT('',(1.27035662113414,13.,-54.4166116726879));
#1736=DIRECTION('',(0.,-1.,0.));
#1737=DIRECTION('',(0.,0.,-1.));
#1738=AXIS2_PLACEMENT_3D('',#1735,#1736,#1737);
#1739=CYLINDRICAL_SURFACE('',#1738,2.);
#1740=ORIENTED_EDGE('',*,*,#1710,.T.);
#1741=EDGE_LOOP('',(#1740));
#1742=FACE_BOUND('',#1741,.T.);
#1743=CARTESIAN_POINT('',(1.27035662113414,3.,-54.4166116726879));
#1744=DIRECTION('',(0.,1.,0.));
#1745=DIRECTION('',(0.,0.,1.));
#1746=AXIS2_PLACEMENT_3D('',#1743,#1744,#1745);
#1747=CIRCLE('',#1746,2.);
#1748=CARTESIAN_POINT('',(1.27035662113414,3.,-52.4166116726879));
#1749=VERTEX_POINT('',#1748);
#1750=EDGE_CURVE('E1112',#1749,#1749,#1747,.F.);
#1751=ORIENTED_EDGE('',*,*,#1750,.T.);
#1752=EDGE_LOOP('',(#1751));
#1753=FACE_BOUND('',#1752,.T.);
#1754=ADVANCED_FACE('F1715',(#1742,#1753),#1739,.F.);
#1755=ORIENTED_EDGE('',*,*,#1750,.F.);
#1756=EDGE_LOOP('',(#1755));
#1757=FACE_BOUND('',#1756,.T.);
#1758=ADVANCED_FACE('F1725',(#1757),#335,.T.);
#1759=CARTESIAN_POINT('',(76.2703566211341,13.,-54.4166116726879));
#1760=DIRECTION('',(0.,1.,0.));
#1761=DIRECTION('',(0.,0.,1.));
#1762=AXIS2_PLACEMENT_3D('',#1759,#1760,#1761);
#1763=PLANE('',#1762);
#1764=CARTESIAN_POINT('',(76.2703566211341,13.,-54.4166116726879));
#1765=DIRECTION('',(0.,1.,0.));
#1766=DIRECTION('',(0.,0.,1.));
#1767=AXIS2_PLACEMENT_3D('',#1764,#1765,#1766);
#1768=CIRCLE('',#1767,4.99999999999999);
#1769=CARTESIAN_POINT('',(76.2703566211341,13.,-49.4166116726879));
#1770=VERTEX_POINT('',#1769);
#1771=EDGE_CURVE('E1075',#1770,#1770,#1768,.T.);
#1772=ORIENTED_EDGE('',*,*,#1771,.T.);
#1773=EDGE_LOOP('',(#1772));
#1774=FACE_BOUND('',#1773,.T.);
#1775=CARTESIAN_POINT('',(76.2703566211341,13.,-54.4166116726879));
#1776=DIRECTION('',(0.,1.,0.));
#1777=DIRECTION('',(0.,0.,1.));
#1778=AXIS2_PLACEMENT_3D('',#1775,#1776,#1777);
#1779=CIRCLE('',#1778,2.);
#1780=CARTESIAN_POINT('',(76.2703566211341,13.,-52.4166116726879));
#1781=VERTEX_POINT('',#1780);
#1782=EDGE_CURVE('E1067',#1781,#1781,#1779,.T.);
#1783=ORIENTED_EDGE('',*,*,#1782,.F.);
#1784=EDGE_LOOP('',(#1783));
#1785=FACE_BOUND('',#1784,.T.);
#1786=ADVANCED_FACE('F1728',(#1774,#1785),#1763,.T.);
#1787=CARTESIAN_POINT('',(76.2703566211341,13.,-54.4166116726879));
#1788=DIRECTION('',(0.,-1.,0.));
#1789=DIRECTION('',(0.,0.,-1.));
#1790=AXIS2_PLACEMENT_3D('',#1787,#1788,#1789);
#1791=CYLINDRICAL_SURFACE('',#1790,4.99999999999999);
#1792=CARTESIAN_POINT('',(76.2703566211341,6.00000000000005,-54.4166116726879));
#1793=DIRECTION('',(0.,1.,0.));
#1794=DIRECTION('',(0.,0.,1.));
#1795=AXIS2_PLACEMENT_3D('',#1792,#1793,#1794);
#1796=CIRCLE('',#1795,4.99999999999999);
#1797=CARTESIAN_POINT('',(76.2703566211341,6.00000000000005,-49.4166116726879));
#1798=VERTEX_POINT('',#1797);
#1799=EDGE_CURVE('E1282',#1798,#1798,#1796,.T.);
#1800=ORIENTED_EDGE('',*,*,#1799,.T.);
#1801=EDGE_LOOP('',(#1800));
#1802=FACE_BOUND('',#1801,.T.);
#1803=ORIENTED_EDGE('',*,*,#1771,.F.);
#1804=EDGE_LOOP('',(#1803));
#1805=FACE_BOUND('',#1804,.T.);
#1806=ADVANCED_FACE('F1721',(#1802,#1805),#1791,.T.);
#1807=CARTESIAN_POINT('',(76.2703566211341,13.,-54.4166116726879));
#1808=DIRECTION('',(0.,-1.,0.));
#1809=DIRECTION('',(0.,0.,-1.));
#1810=AXIS2_PLACEMENT_3D('',#1807,#1808,#1809);
#1811=CYLINDRICAL_SURFACE('',#1810,2.);
#1812=ORIENTED_EDGE('',*,*,#1782,.T.);
#1813=EDGE_LOOP('',(#1812));
#1814=FACE_BOUND('',#1813,.T.);
#1815=CARTESIAN_POINT('',(76.2703566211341,3.,-54.4166116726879));
#1816=DIRECTION('',(0.,1.,0.));
#1817=DIRECTION('',(0.,0.,1.));
#1818=AXIS2_PLACEMENT_3D('',#1815,#1816,#1817);
#1819=CIRCLE('',#1818,2.);
#1820=CARTESIAN_POINT('',(76.2703566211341,3.,-52.4166116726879));
#1821=VERTEX_POINT('',#1820);
#1822=EDGE_CURVE('E1117',#1821,#1821,#1819,.F.);
#1823=ORIENTED_EDGE('',*,*,#1822,.T.);
#1824=EDGE_LOOP('',(#1823));
#1825=FACE_BOUND('',#1824,.T.);
#1826=ADVANCED_FACE('F1730',(#1814,#1825),#1811,.F.);
#1827=ORIENTED_EDGE('',*,*,#1822,.F.);
#1828=EDGE_LOOP('',(#1827));
#1829=FACE_BOUND('',#1828,.T.);
#1830=ADVANCED_FACE('F1733',(#1829),#335,.T.);
#1831=CARTESIAN_POINT('',(76.2703566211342,13.,55.5833883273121));
#1832=DIRECTION('',(0.,1.,0.));
#1833=DIRECTION('',(0.,0.,1.));
#1834=AXIS2_PLACEMENT_3D('',#1831,#1832,#1833);
#1835=PLANE('',#1834);
#1836=CARTESIAN_POINT('',(76.2703566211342,13.,55.5833883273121));
#1837=DIRECTION('',(0.,1.,0.));
#1838=DIRECTION('',(0.,0.,1.));
#1839=AXIS2_PLACEMENT_3D('',#1836,#1837,#1838);
#1840=CIRCLE('',#1839,4.99999999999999);
#1841=CARTESIAN_POINT('',(76.2703566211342,13.,60.5833883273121));
#1842=VERTEX_POINT('',#1841);
#1843=EDGE_CURVE('E1078',#1842,#1842,#1840,.T.);
#1844=ORIENTED_EDGE('',*,*,#1843,.T.);
#1845=EDGE_LOOP('',(#1844));
#1846=FACE_BOUND('',#1845,.T.);
#1847=CARTESIAN_POINT('',(76.2703566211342,13.,55.5833883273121));
#1848=DIRECTION('',(0.,1.,0.));
#1849=DIRECTION('',(0.,0.,1.));
#1850=AXIS2_PLACEMENT_3D('',#1847,#1848,#1849);
#1851=CIRCLE('',#1850,2.);
#1852=CARTESIAN_POINT('',(76.2703566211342,13.,57.5833883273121));
#1853=VERTEX_POINT('',#1852);
#1854=EDGE_CURVE('E1073',#1853,#1853,#1851,.T.);
#1855=ORIENTED_EDGE('',*,*,#1854,.F.);
#1856=EDGE_LOOP('',(#1855));
#1857=FACE_BOUND('',#1856,.T.);
#1858=ADVANCED_FACE('F1743',(#1846,#1857),#1835,.T.);
#1859=CARTESIAN_POINT('',(76.2703566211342,13.,55.5833883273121));
#1860=DIRECTION('',(0.,-1.,0.));
#1861=DIRECTION('',(0.,0.,-1.));
#1862=AXIS2_PLACEMENT_3D('',#1859,#1860,#1861);
#1863=CYLINDRICAL_SURFACE('',#1862,4.99999999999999);
#1864=CARTESIAN_POINT('',(76.2703566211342,6.00000000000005,55.5833883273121));
#1865=DIRECTION('',(0.,1.,0.));
#1866=DIRECTION('',(0.,0.,1.));
#1867=AXIS2_PLACEMENT_3D('',#1864,#1865,#1866);
#1868=CIRCLE('',#1867,4.99999999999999);
#1869=CARTESIAN_POINT('',(76.2703566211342,6.00000000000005,60.5833883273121));
#1870=VERTEX_POINT('',#1869);
#1871=EDGE_CURVE('E1258',#1870,#1870,#1868,.T.);
#1872=ORIENTED_EDGE('',*,*,#1871,.T.);
#1873=EDGE_LOOP('',(#1872));
#1874=FACE_BOUND('',#1873,.T.);
#1875=ORIENTED_EDGE('',*,*,#1843,.F.);
#1876=EDGE_LOOP('',(#1875));
#1877=FACE_BOUND('',#1876,.T.);
#1878=ADVANCED_FACE('F1736',(#1874,#1877),#1863,.T.);
#1879=CARTESIAN_POINT('',(76.2703566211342,13.,55.5833883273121));
#1880=DIRECTION('',(0.,-1.,0.));
#1881=DIRECTION('',(0.,0.,-1.));
#1882=AXIS2_PLACEMENT_3D('',#1879,#1880,#1881);
#1883=CYLINDRICAL_SURFACE('',#1882,2.);
#1884=ORIENTED_EDGE('',*,*,#1854,.T.);
#1885=EDGE_LOOP('',(#1884));
#1886=FACE_BOUND('',#1885,.T.);
#1887=CARTESIAN_POINT('',(76.2703566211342,3.,55.5833883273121));
#1888=DIRECTION('',(0.,1.,0.));
#1889=DIRECTION('',(0.,0.,1.));
#1890=AXIS2_PLACEMENT_3D('',#1887,#1888,#1889);
#1891=CIRCLE('',#1890,2.);
#1892=CARTESIAN_POINT('',(76.2703566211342,3.,57.5833883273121));
#1893=VERTEX_POINT('',#1892);
#1894=EDGE_CURVE('E1122',#1893,#1893,#1891,.F.);
#1895=ORIENTED_EDGE('',*,*,#1894,.T.);
#1896=EDGE_LOOP('',(#1895));
#1897=FACE_BOUND('',#1896,.T.);
#1898=ADVANCED_FACE('F1737',(#1886,#1897),#1883,.F.);
#1899=ORIENTED_EDGE('',*,*,#1894,.F.);
#1900=EDGE_LOOP('',(#1899));
#1901=FACE_BOUND('',#1900,.T.);
#1902=ADVANCED_FACE('F1749',(#1901),#335,.T.);
#1903=CARTESIAN_POINT('',(1.27035662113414,13.,55.5833883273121));
#1904=DIRECTION('',(0.,1.,0.));
#1905=DIRECTION('',(0.,0.,1.));
#1906=AXIS2_PLACEMENT_3D('',#1903,#1904,#1905);
#1907=PLANE('',#1906);
#1908=CARTESIAN_POINT('',(1.27035662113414,13.,55.5833883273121));
#1909=DIRECTION('',(0.,1.,0.));
#1910=DIRECTION('',(0.,0.,1.));
#1911=AXIS2_PLACEMENT_3D('',#1908,#1909,#1910);
#1912=CIRCLE('',#1911,4.99999999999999);
#1913=CARTESIAN_POINT('',(1.27035662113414,13.,60.5833883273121));
#1914=VERTEX_POINT('',#1913);
#1915=EDGE_CURVE('E1065',#1914,#1914,#1912,.T.);
#1916=ORIENTED_EDGE('',*,*,#1915,.T.);
#1917=EDGE_LOOP('',(#1916));
#1918=FACE_BOUND('',#1917,.T.);
#1919=CARTESIAN_POINT('',(1.27035662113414,13.,55.5833883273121));
#1920=DIRECTION('',(0.,1.,0.));
#1921=DIRECTION('',(0.,0.,1.));
#1922=AXIS2_PLACEMENT_3D('',#1919,#1920,#1921);
#1923=CIRCLE('',#1922,2.);
#1924=CARTESIAN_POINT('',(1.27035662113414,13.,57.5833883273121));
#1925=VERTEX_POINT('',#1924);
#1926=EDGE_CURVE('E1083',#1925,#1925,#1923,.T.);
#1927=ORIENTED_EDGE('',*,*,#1926,.F.);
#1928=EDGE_LOOP('',(#1927));
#1929=FACE_BOUND('',#1928,.T.);
#1930=ADVANCED_FACE('F1754',(#1918,#1929),#1907,.T.);
#1931=CARTESIAN_POINT('',(1.27035662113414,13.,55.5833883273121));
#1932=DIRECTION('',(0.,-1.,0.));
#1933=DIRECTION('',(0.,0.,-1.));
#1934=AXIS2_PLACEMENT_3D('',#1931,#1932,#1933);
#1935=CYLINDRICAL_SURFACE('',#1934,4.99999999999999);
#1936=CARTESIAN_POINT('',(1.27035662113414,6.00000000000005,55.5833883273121));
#1937=DIRECTION('',(0.,1.,0.));
#1938=DIRECTION('',(0.,0.,1.));
#1939=AXIS2_PLACEMENT_3D('',#1936,#1937,#1938);
#1940=CIRCLE('',#1939,4.99999999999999);
#1941=CARTESIAN_POINT('',(1.27035662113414,6.00000000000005,60.5833883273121));
#1942=VERTEX_POINT('',#1941);
#1943=EDGE_CURVE('E1278',#1942,#1942,#1940,.T.);
#1944=ORIENTED_EDGE('',*,*,#1943,.T.);
#1945=EDGE_LOOP('',(#1944));
#1946=FACE_BOUND('',#1945,.T.);
#1947=ORIENTED_EDGE('',*,*,#1915,.F.);
#1948=EDGE_LOOP('',(#1947));
#1949=FACE_BOUND('',#1948,.T.);
#1950=ADVANCED_FACE('F1748',(#1946,#1949),#1935,.T.);
#1951=CARTESIAN_POINT('',(1.27035662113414,13.,55.5833883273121));
#1952=DIRECTION('',(0.,-1.,0.));
#1953=DIRECTION('',(0.,0.,-1.));
#1954=AXIS2_PLACEMENT_3D('',#1951,#1952,#1953);
#1955=CYLINDRICAL_SURFACE('',#1954,2.);
#1956=ORIENTED_EDGE('',*,*,#1926,.T.);
#1957=EDGE_LOOP('',(#1956));
#1958=FACE_BOUND('',#1957,.T.);
#1959=CARTESIAN_POINT('',(1.27035662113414,3.,55.5833883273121));
#1960=DIRECTION('',(0.,1.,0.));
#1961=DIRECTION('',(0.,0.,1.));
#1962=AXIS2_PLACEMENT_3D('',#1959,#1960,#1961);
#1963=CIRCLE('',#1962,2.);
#1964=CARTESIAN_POINT('',(1.27035662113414,3.,57.5833883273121));
#1965=VERTEX_POINT('',#1964);
#1966=EDGE_CURVE('E1121',#1965,#1965,#1963,.F.);
#1967=ORIENTED_EDGE('',*,*,#1966,.T.);
#1968=EDGE_LOOP('',(#1967));
#1969=FACE_BOUND('',#1968,.T.);
#1970=ADVANCED_FACE('F1753',(#1958,#1969),#1955,.F.);
#1971=ORIENTED_EDGE('',*,*,#1966,.F.);
#1972=EDGE_LOOP('',(#1971));
#1973=FACE_BOUND('',#1972,.T.);
#1974=ADVANCED_FACE('F1709',(#1973),#335,.T.);
#1975=CARTESIAN_POINT('',(79.,60.,67.));
#1976=DIRECTION('',(0.707106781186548,0.,0.707106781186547));
#1977=DIRECTION('',(0.707106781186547,0.,-0.707106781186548));
#1978=AXIS2_PLACEMENT_3D('',#1975,#1976,#1977);
#1979=PLANE('',#1978);
#1980=ORIENTED_EDGE('',*,*,#692,.T.);
#1981=DIRECTION('',(-0.707106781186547,0.,0.707106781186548));
#1982=VECTOR('',#1981,1.);
#1983=CARTESIAN_POINT('',(79.,4.99999999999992,67.));
#1984=LINE('',#1983,#1982);
#1985=EDGE_CURVE('E1161',#683,#935,#1984,.T.);
#1986=ORIENTED_EDGE('',*,*,#1985,.T.);
#1987=ORIENTED_EDGE('',*,*,#936,.F.);
#1988=DIRECTION('',(0.707106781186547,0.,-0.707106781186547));
#1989=VECTOR('',#1988,1.);
#1990=CARTESIAN_POINT('',(92.,61.5,54.));
#1991=LINE('',#1990,#1989);
#1992=EDGE_CURVE('E724',#933,#691,#1991,.T.);
#1993=ORIENTED_EDGE('',*,*,#1992,.T.);
#1994=EDGE_LOOP('',(#1980,#1986,#1987,#1993));
#1995=FACE_BOUND('',#1994,.T.);
#1996=ADVANCED_FACE('F1701',(#1995),#1979,.F.);
#1997=CARTESIAN_POINT('',(79.,60.,-67.));
#1998=DIRECTION('',(0.707106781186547,0.,-0.707106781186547));
#1999=DIRECTION('',(-0.707106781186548,0.,-0.707106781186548));
#2000=AXIS2_PLACEMENT_3D('',#1997,#1998,#1999);
#2001=PLANE('',#2000);
#2002=ORIENTED_EDGE('',*,*,#912,.T.);
#2003=DIRECTION('',(0.707106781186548,0.,0.707106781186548));
#2004=VECTOR('',#2003,1.);
#2005=CARTESIAN_POINT('',(79.,4.99999999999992,-67.));
#2006=LINE('',#2005,#2004);
#2007=EDGE_CURVE('E1160',#903,#675,#2006,.T.);
#2008=ORIENTED_EDGE('',*,*,#2007,.T.);
#2009=ORIENTED_EDGE('',*,*,#676,.F.);
#2010=DIRECTION('',(-0.707106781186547,0.,-0.707106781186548));
#2011=VECTOR('',#2010,1.);
#2012=CARTESIAN_POINT('',(79.,61.5,-67.));
#2013=LINE('',#2012,#2011);
#2014=EDGE_CURVE('E732',#673,#911,#2013,.T.);
#2015=ORIENTED_EDGE('',*,*,#2014,.T.);
#2016=EDGE_LOOP('',(#2002,#2008,#2009,#2015));
#2017=FACE_BOUND('',#2016,.T.);
#2018=ADVANCED_FACE('F1698',(#2017),#2001,.F.);
#2019=CARTESIAN_POINT('',(-79.0000000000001,60.,-67.));
#2020=DIRECTION('',(-0.707106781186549,0.,-0.707106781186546));
#2021=DIRECTION('',(-0.707106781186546,0.,0.707106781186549));
#2022=AXIS2_PLACEMENT_3D('',#2019,#2020,#2021);
#2023=PLANE('',#2022);
#2024=ORIENTED_EDGE('',*,*,#137,.T.);
#2025=DIRECTION('',(0.707106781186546,0.,-0.707106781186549));
#2026=VECTOR('',#2025,1.);
#2027=CARTESIAN_POINT('',(-79.0000000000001,4.99999999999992,-67.));
#2028=LINE('',#2027,#2026);
#2029=EDGE_CURVE('E697',#136,#895,#2028,.T.);
#2030=ORIENTED_EDGE('',*,*,#2029,.T.);
#2031=ORIENTED_EDGE('',*,*,#896,.F.);
#2032=DIRECTION('',(-0.707106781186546,0.,0.707106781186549));
#2033=VECTOR('',#2032,1.);
#2034=CARTESIAN_POINT('',(-92.,61.5,-54.));
#2035=LINE('',#2034,#2033);
#2036=EDGE_CURVE('E692',#893,#134,#2035,.T.);
#2037=ORIENTED_EDGE('',*,*,#2036,.T.);
#2038=EDGE_LOOP('',(#2024,#2030,#2031,#2037));
#2039=FACE_BOUND('',#2038,.T.);
#2040=ADVANCED_FACE('F693',(#2039),#2023,.F.);
#2041=CARTESIAN_POINT('',(-92.,60.,54.));
#2042=DIRECTION('',(-0.707106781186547,0.,0.707106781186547));
#2043=DIRECTION('',(0.707106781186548,0.,0.707106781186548));
#2044=AXIS2_PLACEMENT_3D('',#2041,#2042,#2043);
#2045=PLANE('',#2044);
#2046=ORIENTED_EDGE('',*,*,#952,.T.);
#2047=DIRECTION('',(-0.707106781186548,0.,-0.707106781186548));
#2048=VECTOR('',#2047,1.);
#2049=CARTESIAN_POINT('',(-92.,4.99999999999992,54.));
#2050=LINE('',#2049,#2048);
#2051=EDGE_CURVE('E1130',#943,#152,#2050,.T.);
#2052=ORIENTED_EDGE('',*,*,#2051,.T.);
#2053=ORIENTED_EDGE('',*,*,#153,.F.);
#2054=DIRECTION('',(0.707106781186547,0.,0.707106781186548));
#2055=VECTOR('',#2054,1.);
#2056=CARTESIAN_POINT('',(-79.,61.5,67.));
#2057=LINE('',#2056,#2055);
#2058=EDGE_CURVE('E720',#144,#951,#2057,.T.);
#2059=ORIENTED_EDGE('',*,*,#2058,.T.);
#2060=EDGE_LOOP('',(#2046,#2052,#2053,#2059));
#2061=FACE_BOUND('',#2060,.T.);
#2062=ADVANCED_FACE('F1692',(#2061),#2045,.F.);
#2063=CARTESIAN_POINT('',(0.,45.5,0.));
#2064=DIRECTION('',(0.,1.,0.));
#2065=DIRECTION('',(0.,0.,1.));
#2066=AXIS2_PLACEMENT_3D('',#2063,#2064,#2065);
#2067=PLANE('',#2066);
#2068=CARTESIAN_POINT('',(89.5177669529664,45.5,-64.5177669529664));
#2069=DIRECTION('',(0.,-1.,0.));
#2070=DIRECTION('',(0.,0.,-1.));
#2071=AXIS2_PLACEMENT_3D('',#2068,#2069,#2070);
#2072=CIRCLE('',#2071,2.15);
#2073=CARTESIAN_POINT('',(89.5177669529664,45.5,-66.6677669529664));
#2074=VERTEX_POINT('',#2073);
#2075=EDGE_CURVE('E1001',#2074,#2074,#2072,.T.);
#2076=ORIENTED_EDGE('',*,*,#2075,.F.);
#2077=EDGE_LOOP('',(#2076));
#2078=FACE_BOUND('',#2077,.T.);
#2079=CARTESIAN_POINT('',(89.5177669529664,45.5,-64.5177669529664));
#2080=DIRECTION('',(0.,1.,0.));
#2081=DIRECTION('',(0.,0.,1.));
#2082=AXIS2_PLACEMENT_3D('',#2079,#2080,#2081);
#2083=CIRCLE('',#2082,3.8);
#2084=CARTESIAN_POINT('',(89.5177669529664,45.5,-60.7177669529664));
#2085=VERTEX_POINT('',#2084);
#2086=EDGE_CURVE('E1045',#2085,#2085,#2083,.F.);
#2087=ORIENTED_EDGE('',*,*,#2086,.T.);
#2088=EDGE_LOOP('',(#2087));
#2089=FACE_BOUND('',#2088,.T.);
#2090=ADVANCED_FACE('F1687',(#2078,#2089),#2067,.F.);
#2091=CARTESIAN_POINT('',(89.5177669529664,70.7480230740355,-64.5177669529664));
#2092=DIRECTION('',(0.,-1.,0.));
#2093=DIRECTION('',(0.,0.,-1.));
#2094=AXIS2_PLACEMENT_3D('',#2091,#2092,#2093);
#2095=CYLINDRICAL_SURFACE('',#2094,3.8);
#2096=ORIENTED_EDGE('',*,*,#1514,.T.);
#2097=EDGE_LOOP('',(#2096));
#2098=FACE_BOUND('',#2097,.T.);
#2099=ORIENTED_EDGE('',*,*,#2086,.F.);
#2100=EDGE_LOOP('',(#2099));
#2101=FACE_BOUND('',#2100,.T.);
#2102=ADVANCED_FACE('F1688',(#2098,#2101),#2095,.F.);
#2103=CARTESIAN_POINT('',(0.,45.5,0.));
#2104=DIRECTION('',(0.,1.,0.));
#2105=DIRECTION('',(0.,0.,1.));
#2106=AXIS2_PLACEMENT_3D('',#2103,#2104,#2105);
#2107=PLANE('',#2106);
#2108=CARTESIAN_POINT('',(89.5177669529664,45.5,64.5177669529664));
#2109=DIRECTION('',(0.,-1.,0.));
#2110=DIRECTION('',(0.,0.,-1.));
#2111=AXIS2_PLACEMENT_3D('',#2108,#2109,#2110);
#2112=CIRCLE('',#2111,2.15);
#2113=CARTESIAN_POINT('',(89.5177669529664,45.5,62.3677669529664));
#2114=VERTEX_POINT('',#2113);
#2115=EDGE_CURVE('E999',#2114,#2114,#2112,.T.);
#2116=ORIENTED_EDGE('',*,*,#2115,.F.);
#2117=EDGE_LOOP('',(#2116));
#2118=FACE_BOUND('',#2117,.T.);
#2119=CARTESIAN_POINT('',(89.5177669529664,45.5,64.5177669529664));
#2120=DIRECTION('',(0.,1.,0.));
#2121=DIRECTION('',(0.,0.,1.));
#2122=AXIS2_PLACEMENT_3D('',#2119,#2120,#2121);
#2123=CIRCLE('',#2122,3.8);
#2124=CARTESIAN_POINT('',(89.5177669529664,45.5,68.3177669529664));
#2125=VERTEX_POINT('',#2124);
#2126=EDGE_CURVE('E1022',#2125,#2125,#2123,.F.);
#2127=ORIENTED_EDGE('',*,*,#2126,.T.);
#2128=EDGE_LOOP('',(#2127));
#2129=FACE_BOUND('',#2128,.T.);
#2130=ADVANCED_FACE('F1689',(#2118,#2129),#2107,.F.);
#2131=CARTESIAN_POINT('',(89.5177669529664,70.7480230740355,64.5177669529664));
#2132=DIRECTION('',(0.,-1.,0.));
#2133=DIRECTION('',(0.,0.,-1.));
#2134=AXIS2_PLACEMENT_3D('',#2131,#2132,#2133);
#2135=CYLINDRICAL_SURFACE('',#2134,3.8);
#2136=ORIENTED_EDGE('',*,*,#1503,.T.);
#2137=EDGE_LOOP('',(#2136));
#2138=FACE_BOUND('',#2137,.T.);
#2139=ORIENTED_EDGE('',*,*,#2126,.F.);
#2140=EDGE_LOOP('',(#2139));
#2141=FACE_BOUND('',#2140,.T.);
#2142=ADVANCED_FACE('F1669',(#2138,#2141),#2135,.F.);
#2143=CARTESIAN_POINT('',(0.,45.5,0.));
#2144=DIRECTION('',(0.,1.,0.));
#2145=DIRECTION('',(0.,0.,1.));
#2146=AXIS2_PLACEMENT_3D('',#2143,#2144,#2145);
#2147=PLANE('',#2146);
#2148=CARTESIAN_POINT('',(-89.5177669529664,45.5,64.5177669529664));
#2149=DIRECTION('',(0.,-1.,0.));
#2150=DIRECTION('',(0.,0.,-1.));
#2151=AXIS2_PLACEMENT_3D('',#2148,#2149,#2150);
#2152=CIRCLE('',#2151,2.15);
#2153=CARTESIAN_POINT('',(-89.5177669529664,45.5,62.3677669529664));
#2154=VERTEX_POINT('',#2153);
#2155=EDGE_CURVE('E1002',#2154,#2154,#2152,.T.);
#2156=ORIENTED_EDGE('',*,*,#2155,.F.);
#2157=EDGE_LOOP('',(#2156));
#2158=FACE_BOUND('',#2157,.T.);
#2159=CARTESIAN_POINT('',(-89.5177669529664,45.5,64.5177669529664));
#2160=DIRECTION('',(0.,1.,0.));
#2161=DIRECTION('',(0.,0.,1.));
#2162=AXIS2_PLACEMENT_3D('',#2159,#2160,#2161);
#2163=CIRCLE('',#2162,3.8);
#2164=CARTESIAN_POINT('',(-89.5177669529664,45.5,68.3177669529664));
#2165=VERTEX_POINT('',#2164);
#2166=EDGE_CURVE('E1035',#2165,#2165,#2163,.F.);
#2167=ORIENTED_EDGE('',*,*,#2166,.T.);
#2168=EDGE_LOOP('',(#2167));
#2169=FACE_BOUND('',#2168,.T.);
#2170=ADVANCED_FACE('F1665',(#2158,#2169),#2147,.F.);
#2171=CARTESIAN_POINT('',(-89.5177669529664,70.7480230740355,64.5177669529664));
#2172=DIRECTION('',(0.,-1.,0.));
#2173=DIRECTION('',(0.,0.,-1.));
#2174=AXIS2_PLACEMENT_3D('',#2171,#2172,#2173);
#2175=CYLINDRICAL_SURFACE('',#2174,3.8);
#2176=ORIENTED_EDGE('',*,*,#1492,.T.);
#2177=EDGE_LOOP('',(#2176));
#2178=FACE_BOUND('',#2177,.T.);
#2179=ORIENTED_EDGE('',*,*,#2166,.F.);
#2180=EDGE_LOOP('',(#2179));
#2181=FACE_BOUND('',#2180,.T.);
#2182=ADVANCED_FACE('F1668',(#2178,#2181),#2175,.F.);
#2183=CARTESIAN_POINT('',(0.,45.5,0.));
#2184=DIRECTION('',(0.,1.,0.));
#2185=DIRECTION('',(0.,0.,1.));
#2186=AXIS2_PLACEMENT_3D('',#2183,#2184,#2185);
#2187=PLANE('',#2186);
#2188=CARTESIAN_POINT('',(-89.5177669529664,45.5,-64.5177669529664));
#2189=DIRECTION('',(0.,-1.,0.));
#2190=DIRECTION('',(0.,0.,-1.));
#2191=AXIS2_PLACEMENT_3D('',#2188,#2189,#2190);
#2192=CIRCLE('',#2191,2.15);
#2193=CARTESIAN_POINT('',(-89.5177669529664,45.5,-66.6677669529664));
#2194=VERTEX_POINT('',#2193);
#2195=EDGE_CURVE('E1013',#2194,#2194,#2192,.T.);
#2196=ORIENTED_EDGE('',*,*,#2195,.F.);
#2197=EDGE_LOOP('',(#2196));
#2198=FACE_BOUND('',#2197,.T.);
#2199=CARTESIAN_POINT('',(-89.5177669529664,45.5,-64.5177669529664));
#2200=DIRECTION('',(0.,1.,0.));
#2201=DIRECTION('',(0.,0.,1.));
#2202=AXIS2_PLACEMENT_3D('',#2199,#2200,#2201);
#2203=CIRCLE('',#2202,3.8);
#2204=CARTESIAN_POINT('',(-89.5177669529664,45.5,-60.7177669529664));
#2205=VERTEX_POINT('',#2204);
#2206=EDGE_CURVE('E1021',#2205,#2205,#2203,.F.);
#2207=ORIENTED_EDGE('',*,*,#2206,.T.);
#2208=EDGE_LOOP('',(#2207));
#2209=FACE_BOUND('',#2208,.T.);
#2210=ADVANCED_FACE('F1675',(#2198,#2209),#2187,.F.);
#2211=CARTESIAN_POINT('',(-89.5177669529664,70.7480230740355,-64.5177669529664));
#2212=DIRECTION('',(0.,-1.,0.));
#2213=DIRECTION('',(0.,0.,-1.));
#2214=AXIS2_PLACEMENT_3D('',#2211,#2212,#2213);
#2215=CYLINDRICAL_SURFACE('',#2214,3.8);
#2216=ORIENTED_EDGE('',*,*,#1481,.T.);
#2217=EDGE_LOOP('',(#2216));
#2218=FACE_BOUND('',#2217,.T.);
#2219=ORIENTED_EDGE('',*,*,#2206,.F.);
#2220=EDGE_LOOP('',(#2219));
#2221=FACE_BOUND('',#2220,.T.);
#2222=ADVANCED_FACE('F1659',(#2218,#2221),#2215,.F.);
#2223=CARTESIAN_POINT('',(-89.5177669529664,60.,64.5177669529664));
#2224=DIRECTION('',(0.,-1.,0.));
#2225=DIRECTION('',(0.,0.,-1.));
#2226=AXIS2_PLACEMENT_3D('',#2223,#2224,#2225);
#2227=CYLINDRICAL_SURFACE('',#2226,2.15);
#2228=ORIENTED_EDGE('',*,*,#1394,.F.);
#2229=EDGE_LOOP('',(#2228));
#2230=FACE_BOUND('',#2229,.T.);
#2231=ORIENTED_EDGE('',*,*,#2155,.T.);
#2232=EDGE_LOOP('',(#2231));
#2233=FACE_BOUND('',#2232,.T.);
#2234=ADVANCED_FACE('F1651',(#2230,#2233),#2227,.F.);
#2235=CARTESIAN_POINT('',(89.5177669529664,60.,64.5177669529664));
#2236=DIRECTION('',(0.,-1.,0.));
#2237=DIRECTION('',(0.,0.,-1.));
#2238=AXIS2_PLACEMENT_3D('',#2235,#2236,#2237);
#2239=CYLINDRICAL_SURFACE('',#2238,2.15);
#2240=ORIENTED_EDGE('',*,*,#1383,.F.);
#2241=EDGE_LOOP('',(#2240));
#2242=FACE_BOUND('',#2241,.T.);
#2243=ORIENTED_EDGE('',*,*,#2115,.T.);
#2244=EDGE_LOOP('',(#2243));
#2245=FACE_BOUND('',#2244,.T.);
#2246=ADVANCED_FACE('F1656',(#2242,#2245),#2239,.F.);
#2247=CARTESIAN_POINT('',(89.5177669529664,60.,-64.5177669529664));
#2248=DIRECTION('',(0.,-1.,0.));
#2249=DIRECTION('',(0.,0.,-1.));
#2250=AXIS2_PLACEMENT_3D('',#2247,#2248,#2249);
#2251=CYLINDRICAL_SURFACE('',#2250,2.15);
#2252=ORIENTED_EDGE('',*,*,#1372,.F.);
#2253=EDGE_LOOP('',(#2252));
#2254=FACE_BOUND('',#2253,.T.);
#2255=ORIENTED_EDGE('',*,*,#2075,.T.);
#2256=EDGE_LOOP('',(#2255));
#2257=FACE_BOUND('',#2256,.T.);
#2258=ADVANCED_FACE('F1899',(#2254,#2257),#2251,.F.);
#2259=CARTESIAN_POINT('',(-89.5177669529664,60.,-64.5177669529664));
#2260=DIRECTION('',(0.,-1.,0.));
#2261=DIRECTION('',(0.,0.,-1.));
#2262=AXIS2_PLACEMENT_3D('',#2259,#2260,#2261);
#2263=CYLINDRICAL_SURFACE('',#2262,2.15);
#2264=ORIENTED_EDGE('',*,*,#1361,.F.);
#2265=EDGE_LOOP('',(#2264));
#2266=FACE_BOUND('',#2265,.T.);
#2267=ORIENTED_EDGE('',*,*,#2195,.T.);
#2268=EDGE_LOOP('',(#2267));
#2269=FACE_BOUND('',#2268,.T.);
#2270=ADVANCED_FACE('F1906',(#2266,#2269),#2263,.F.);
#2271=CARTESIAN_POINT('',(79.,4.99999999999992,-67.));
#2272=DIRECTION('',(0.499999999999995,-0.707106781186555,-0.499999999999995));
#2273=DIRECTION('',(0.707106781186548,0.,0.707106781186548));
#2274=AXIS2_PLACEMENT_3D('',#2271,#2272,#2273);
#2275=PLANE('',#2274);
#2276=DIRECTION('',(0.281084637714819,0.678598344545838,-0.678598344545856));
#2277=VECTOR('',#2276,1.);
#2278=CARTESIAN_POINT('',(71.9953484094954,-11.9107248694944,-50.0892751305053));
#2279=LINE('',#2278,#2277);
#2280=EDGE_CURVE('E1184',#522,#903,#2279,.T.);
#2281=ORIENTED_EDGE('',*,*,#2280,.F.);
#2282=ORIENTED_EDGE('',*,*,#523,.F.);
#2283=DIRECTION('',(0.678598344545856,0.678598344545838,-0.281084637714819));
#2284=VECTOR('',#2283,1.);
#2285=CARTESIAN_POINT('',(88.4932221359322,1.49322213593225,-52.5474450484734));
#2286=LINE('',#2285,#2284);
#2287=EDGE_CURVE('E1020',#675,#514,#2286,.F.);
#2288=ORIENTED_EDGE('',*,*,#2287,.F.);
#2289=ORIENTED_EDGE('',*,*,#2007,.F.);
#2290=EDGE_LOOP('',(#2281,#2282,#2288,#2289));
#2291=FACE_BOUND('',#2290,.T.);
#2292=ADVANCED_FACE('F1918',(#2291),#2275,.F.);
#2293=CARTESIAN_POINT('',(90.,3.,0.));
#2294=DIRECTION('',(-0.707106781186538,0.707106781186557,0.));
#2295=DIRECTION('',(0.,0.,1.));
#2296=AXIS2_PLACEMENT_3D('',#2293,#2294,#2295);
#2297=PLANE('',#2296);
#2298=ORIENTED_EDGE('',*,*,#2287,.T.);
#2299=ORIENTED_EDGE('',*,*,#515,.F.);
#2300=DIRECTION('',(-0.678598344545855,-0.678598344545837,-0.281084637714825));
#2301=VECTOR('',#2300,1.);
#2302=CARTESIAN_POINT('',(88.4932221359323,1.49322213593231,52.5474450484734));
#2303=LINE('',#2302,#2301);
#2304=EDGE_CURVE('E1179',#683,#506,#2303,.T.);
#2305=ORIENTED_EDGE('',*,*,#2304,.F.);
#2306=ORIENTED_EDGE('',*,*,#684,.F.);
#2307=EDGE_LOOP('',(#2298,#2299,#2305,#2306));
#2308=FACE_BOUND('',#2307,.T.);
#2309=ADVANCED_FACE('F1927',(#2308),#2297,.T.);
#2310=CARTESIAN_POINT('',(0.,3.,-65.));
#2311=DIRECTION('',(0.,0.707106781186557,0.707106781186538));
#2312=DIRECTION('',(1.,0.,0.));
#2313=AXIS2_PLACEMENT_3D('',#2310,#2311,#2312);
#2314=PLANE('',#2313);
#2315=ORIENTED_EDGE('',*,*,#2280,.T.);
#2316=ORIENTED_EDGE('',*,*,#904,.F.);
#2317=DIRECTION('',(-0.28108463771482,0.678598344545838,-0.678598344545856));
#2318=VECTOR('',#2317,1.);
#2319=CARTESIAN_POINT('',(-79.0000000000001,4.99999999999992,-67.));
#2320=LINE('',#2319,#2318);
#2321=EDGE_CURVE('E1180',#530,#895,#2320,.T.);
#2322=ORIENTED_EDGE('',*,*,#2321,.F.);
#2323=ORIENTED_EDGE('',*,*,#531,.F.);
#2324=EDGE_LOOP('',(#2315,#2316,#2322,#2323));
#2325=FACE_BOUND('',#2324,.T.);
#2326=ADVANCED_FACE('F1940',(#2325),#2314,.T.);
#2327=CARTESIAN_POINT('',(79.,4.99999999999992,67.));
#2328=DIRECTION('',(0.499999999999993,-0.707106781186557,0.499999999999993));
#2329=DIRECTION('',(-0.707106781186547,0.,0.707106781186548));
#2330=AXIS2_PLACEMENT_3D('',#2327,#2328,#2329);
#2331=PLANE('',#2330);
#2332=ORIENTED_EDGE('',*,*,#2304,.T.);
#2333=ORIENTED_EDGE('',*,*,#507,.F.);
#2334=DIRECTION('',(-0.281084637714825,-0.678598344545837,-0.678598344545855));
#2335=VECTOR('',#2334,1.);
#2336=CARTESIAN_POINT('',(71.9953484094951,-11.9107248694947,50.089275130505));
#2337=LINE('',#2336,#2335);
#2338=EDGE_CURVE('E1172',#935,#498,#2337,.T.);
#2339=ORIENTED_EDGE('',*,*,#2338,.F.);
#2340=ORIENTED_EDGE('',*,*,#1985,.F.);
#2341=EDGE_LOOP('',(#2332,#2333,#2339,#2340));
#2342=FACE_BOUND('',#2341,.T.);
#2343=ADVANCED_FACE('F1949',(#2342),#2331,.F.);
#2344=CARTESIAN_POINT('',(-79.0000000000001,4.99999999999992,-67.));
#2345=DIRECTION('',(-0.499999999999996,-0.707106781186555,-0.499999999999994));
#2346=DIRECTION('',(0.707106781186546,0.,-0.707106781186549));
#2347=AXIS2_PLACEMENT_3D('',#2344,#2345,#2346);
#2348=PLANE('',#2347);
#2349=ORIENTED_EDGE('',*,*,#2321,.T.);
#2350=ORIENTED_EDGE('',*,*,#2029,.F.);
#2351=ORIENTED_EDGE('',*,*,#657,.F.);
#2352=ORIENTED_EDGE('',*,*,#537,.F.);
#2353=EDGE_LOOP('',(#2349,#2350,#2351,#2352));
#2354=FACE_BOUND('',#2353,.T.);
#2355=ADVANCED_FACE('F1964',(#2354),#2348,.F.);
#2356=CARTESIAN_POINT('',(0.,3.,65.));
#2357=DIRECTION('',(0.,0.707106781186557,-0.707106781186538));
#2358=DIRECTION('',(-1.,0.,0.));
#2359=AXIS2_PLACEMENT_3D('',#2356,#2357,#2358);
#2360=PLANE('',#2359);
#2361=ORIENTED_EDGE('',*,*,#2338,.T.);
#2362=ORIENTED_EDGE('',*,*,#499,.F.);
#2363=DIRECTION('',(0.281084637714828,-0.678598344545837,-0.678598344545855));
#2364=VECTOR('',#2363,1.);
#2365=CARTESIAN_POINT('',(-77.5474450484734,1.49322213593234,63.4932221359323));
#2366=LINE('',#2365,#2364);
#2367=EDGE_CURVE('E1167',#943,#490,#2366,.T.);
#2368=ORIENTED_EDGE('',*,*,#2367,.F.);
#2369=ORIENTED_EDGE('',*,*,#944,.F.);
#2370=EDGE_LOOP('',(#2361,#2362,#2368,#2369));
#2371=FACE_BOUND('',#2370,.T.);
#2372=ADVANCED_FACE('F1972',(#2371),#2360,.T.);
#2373=CARTESIAN_POINT('',(-92.,4.99999999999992,54.));
#2374=DIRECTION('',(-0.499999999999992,-0.707106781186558,0.499999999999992));
#2375=DIRECTION('',(-0.707106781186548,0.,-0.707106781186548));
#2376=AXIS2_PLACEMENT_3D('',#2373,#2374,#2375);
#2377=PLANE('',#2376);
#2378=ORIENTED_EDGE('',*,*,#2367,.T.);
#2379=ORIENTED_EDGE('',*,*,#491,.F.);
#2380=ORIENTED_EDGE('',*,*,#567,.T.);
#2381=ORIENTED_EDGE('',*,*,#2051,.F.);
#2382=EDGE_LOOP('',(#2378,#2379,#2380,#2381));
#2383=FACE_BOUND('',#2382,.T.);
#2384=ADVANCED_FACE('F1983',(#2383),#2377,.F.);
#2385=CARTESIAN_POINT('',(89.,33.,15.9831336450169));
#2386=DIRECTION('',(1.,0.,0.));
#2387=DIRECTION('',(0.,0.,-1.));
#2388=AXIS2_PLACEMENT_3D('',#2385,#2386,#2387);
#2389=CYLINDRICAL_SURFACE('',#2388,2.);
#2390=DIRECTION('',(1.,0.,0.));
#2391=VECTOR('',#2390,1.);
#2392=CARTESIAN_POINT('',(89.,35.,15.9831336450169));
#2393=LINE('',#2392,#2391);
#2394=CARTESIAN_POINT('',(94.,35.,15.9831336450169));
#2395=VERTEX_POINT('',#2394);
#2396=EDGE_CURVE('E966',#709,#2395,#2393,.T.);
#2397=ORIENTED_EDGE('',*,*,#2396,.T.);
#2398=CARTESIAN_POINT('',(94.,33.,15.9831336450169));
#2399=DIRECTION('',(-1.,0.,0.));
#2400=DIRECTION('',(0.,0.,1.));
#2401=AXIS2_PLACEMENT_3D('',#2398,#2399,#2400);
#2402=CIRCLE('',#2401,2.);
#2403=CARTESIAN_POINT('',(94.,33.,17.9831336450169));
#2404=VERTEX_POINT('',#2403);
#2405=EDGE_CURVE('E1422',#2395,#2404,#2402,.F.);
#2406=ORIENTED_EDGE('',*,*,#2405,.T.);
#2407=DIRECTION('',(1.,0.,0.));
#2408=VECTOR('',#2407,1.);
#2409=CARTESIAN_POINT('',(89.,33.,17.9831336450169));
#2410=LINE('',#2409,#2408);
#2411=EDGE_CURVE('E947',#718,#2404,#2410,.T.);
#2412=ORIENTED_EDGE('',*,*,#2411,.F.);
#2413=ORIENTED_EDGE('',*,*,#719,.F.);
#2414=EDGE_LOOP('',(#2397,#2406,#2412,#2413));
#2415=FACE_BOUND('',#2414,.T.);
#2416=ADVANCED_FACE('F1992',(#2415),#2389,.F.);
#2417=CARTESIAN_POINT('',(89.,35.,-0.0168663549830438));
#2418=DIRECTION('',(0.,-1.,0.));
#2419=DIRECTION('',(0.,0.,-1.));
#2420=AXIS2_PLACEMENT_3D('',#2417,#2418,#2419);
#2421=PLANE('',#2420);
#2422=DIRECTION('',(1.,0.,0.));
#2423=VECTOR('',#2422,1.);
#2424=CARTESIAN_POINT('',(89.,35.,-0.0168663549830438));
#2425=LINE('',#2424,#2423);
#2426=CARTESIAN_POINT('',(94.,35.,-0.0168663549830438));
#2427=VERTEX_POINT('',#2426);
#2428=EDGE_CURVE('E969',#707,#2427,#2425,.T.);
#2429=ORIENTED_EDGE('',*,*,#2428,.T.);
#2430=DIRECTION('',(0.,0.,1.));
#2431=VECTOR('',#2430,1.);
#2432=CARTESIAN_POINT('',(94.,35.,15.9831336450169));
#2433=LINE('',#2432,#2431);
#2434=EDGE_CURVE('E1423',#2427,#2395,#2433,.T.);
#2435=ORIENTED_EDGE('',*,*,#2434,.T.);
#2436=ORIENTED_EDGE('',*,*,#2396,.F.);
#2437=ORIENTED_EDGE('',*,*,#710,.F.);
#2438=EDGE_LOOP('',(#2429,#2435,#2436,#2437));
#2439=FACE_BOUND('',#2438,.T.);
#2440=ADVANCED_FACE('F2020',(#2439),#2421,.T.);
#2441=CARTESIAN_POINT('',(89.,33.,-0.0168663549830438));
#2442=DIRECTION('',(1.,0.,0.));
#2443=DIRECTION('',(0.,0.,-1.));
#2444=AXIS2_PLACEMENT_3D('',#2441,#2442,#2443);
#2445=CYLINDRICAL_SURFACE('',#2444,2.);
#2446=DIRECTION('',(1.,0.,0.));
#2447=VECTOR('',#2446,1.);
#2448=CARTESIAN_POINT('',(89.,33.,-2.01686635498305));
#2449=LINE('',#2448,#2447);
#2450=CARTESIAN_POINT('',(94.,33.,-2.01686635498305));
#2451=VERTEX_POINT('',#2450);
#2452=EDGE_CURVE('E963',#760,#2451,#2449,.T.);
#2453=ORIENTED_EDGE('',*,*,#2452,.T.);
#2454=CARTESIAN_POINT('',(94.,33.,-0.0168663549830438));
#2455=DIRECTION('',(-1.,0.,0.));
#2456=DIRECTION('',(0.,0.,1.));
#2457=AXIS2_PLACEMENT_3D('',#2454,#2455,#2456);
#2458=CIRCLE('',#2457,2.);
#2459=EDGE_CURVE('E1429',#2451,#2427,#2458,.F.);
#2460=ORIENTED_EDGE('',*,*,#2459,.T.);
#2461=ORIENTED_EDGE('',*,*,#2428,.F.);
#2462=ORIENTED_EDGE('',*,*,#768,.F.);
#2463=EDGE_LOOP('',(#2453,#2460,#2461,#2462));
#2464=FACE_BOUND('',#2463,.T.);
#2465=ADVANCED_FACE('F2026',(#2464),#2445,.F.);
#2466=CARTESIAN_POINT('',(89.,33.,-2.01686635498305));
#2467=DIRECTION('',(0.,0.,1.));
#2468=DIRECTION('',(1.,0.,0.));
#2469=AXIS2_PLACEMENT_3D('',#2466,#2467,#2468);
#2470=PLANE('',#2469);
#2471=DIRECTION('',(1.,0.,0.));
#2472=VECTOR('',#2471,1.);
#2473=CARTESIAN_POINT('',(89.,26.,-2.01686635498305));
#2474=LINE('',#2473,#2472);
#2475=CARTESIAN_POINT('',(94.,26.,-2.01686635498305));
#2476=VERTEX_POINT('',#2475);
#2477=EDGE_CURVE('E964',#752,#2476,#2474,.T.);
#2478=ORIENTED_EDGE('',*,*,#2477,.T.);
#2479=DIRECTION('',(0.,1.,0.));
#2480=VECTOR('',#2479,1.);
#2481=CARTESIAN_POINT('',(94.,33.,-2.01686635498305));
#2482=LINE('',#2481,#2480);
#2483=EDGE_CURVE('E1431',#2476,#2451,#2482,.T.);
#2484=ORIENTED_EDGE('',*,*,#2483,.T.);
#2485=ORIENTED_EDGE('',*,*,#2452,.F.);
#2486=ORIENTED_EDGE('',*,*,#761,.F.);
#2487=EDGE_LOOP('',(#2478,#2484,#2485,#2486));
#2488=FACE_BOUND('',#2487,.T.);
#2489=ADVANCED_FACE('F2037',(#2488),#2470,.T.);
#2490=CARTESIAN_POINT('',(89.,26.,-0.0168663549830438));
#2491=DIRECTION('',(1.,0.,0.));
#2492=DIRECTION('',(0.,0.,-1.));
#2493=AXIS2_PLACEMENT_3D('',#2490,#2491,#2492);
#2494=CYLINDRICAL_SURFACE('',#2493,2.);
#2495=DIRECTION('',(1.,0.,0.));
#2496=VECTOR('',#2495,1.);
#2497=CARTESIAN_POINT('',(89.,24.,-0.0168663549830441));
#2498=LINE('',#2497,#2496);
#2499=CARTESIAN_POINT('',(94.,24.,-0.0168663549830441));
#2500=VERTEX_POINT('',#2499);
#2501=EDGE_CURVE('E959',#743,#2500,#2498,.T.);
#2502=ORIENTED_EDGE('',*,*,#2501,.T.);
#2503=CARTESIAN_POINT('',(94.,26.,-0.0168663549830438));
#2504=DIRECTION('',(-1.,0.,0.));
#2505=DIRECTION('',(0.,0.,1.));
#2506=AXIS2_PLACEMENT_3D('',#2503,#2504,#2505);
#2507=CIRCLE('',#2506,2.);
#2508=EDGE_CURVE('E1432',#2500,#2476,#2507,.F.);
#2509=ORIENTED_EDGE('',*,*,#2508,.T.);
#2510=ORIENTED_EDGE('',*,*,#2477,.F.);
#2511=ORIENTED_EDGE('',*,*,#753,.F.);
#2512=EDGE_LOOP('',(#2502,#2509,#2510,#2511));
#2513=FACE_BOUND('',#2512,.T.);
#2514=ADVANCED_FACE('F2048',(#2513),#2494,.F.);
#2515=CARTESIAN_POINT('',(89.,24.,-0.0168663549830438));
#2516=DIRECTION('',(0.,1.,0.));
#2517=DIRECTION('',(0.,0.,1.));
#2518=AXIS2_PLACEMENT_3D('',#2515,#2516,#2517);
#2519=PLANE('',#2518);
#2520=DIRECTION('',(1.,0.,0.));
#2521=VECTOR('',#2520,1.);
#2522=CARTESIAN_POINT('',(89.,24.,15.9831336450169));
#2523=LINE('',#2522,#2521);
#2524=CARTESIAN_POINT('',(94.,24.,15.9831336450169));
#2525=VERTEX_POINT('',#2524);
#2526=EDGE_CURVE('E954',#735,#2525,#2523,.T.);
#2527=ORIENTED_EDGE('',*,*,#2526,.T.);
#2528=DIRECTION('',(0.,0.,-1.));
#2529=VECTOR('',#2528,1.);
#2530=CARTESIAN_POINT('',(94.,24.,-0.0168663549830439));
#2531=LINE('',#2530,#2529);
#2532=EDGE_CURVE('E1430',#2525,#2500,#2531,.T.);
#2533=ORIENTED_EDGE('',*,*,#2532,.T.);
#2534=ORIENTED_EDGE('',*,*,#2501,.F.);
#2535=ORIENTED_EDGE('',*,*,#744,.F.);
#2536=EDGE_LOOP('',(#2527,#2533,#2534,#2535));
#2537=FACE_BOUND('',#2536,.T.);
#2538=ADVANCED_FACE('F2059',(#2537),#2519,.T.);
#2539=CARTESIAN_POINT('',(89.,26.,15.9831336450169));
#2540=DIRECTION('',(1.,0.,0.));
#2541=DIRECTION('',(0.,0.,-1.));
#2542=AXIS2_PLACEMENT_3D('',#2539,#2540,#2541);
#2543=CYLINDRICAL_SURFACE('',#2542,2.00000000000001);
#2544=DIRECTION('',(1.,0.,0.));
#2545=VECTOR('',#2544,1.);
#2546=CARTESIAN_POINT('',(89.,26.,17.9831336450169));
#2547=LINE('',#2546,#2545);
#2548=CARTESIAN_POINT('',(94.,26.,17.9831336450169));
#2549=VERTEX_POINT('',#2548);
#2550=EDGE_CURVE('E955',#726,#2549,#2547,.T.);
#2551=ORIENTED_EDGE('',*,*,#2550,.T.);
#2552=CARTESIAN_POINT('',(94.,26.,15.9831336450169));
#2553=DIRECTION('',(-1.,0.,0.));
#2554=DIRECTION('',(0.,0.,1.));
#2555=AXIS2_PLACEMENT_3D('',#2552,#2553,#2554);
#2556=CIRCLE('',#2555,2.00000000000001);
#2557=EDGE_CURVE('E1424',#2549,#2525,#2556,.F.);
#2558=ORIENTED_EDGE('',*,*,#2557,.T.);
#2559=ORIENTED_EDGE('',*,*,#2526,.F.);
#2560=ORIENTED_EDGE('',*,*,#736,.F.);
#2561=EDGE_LOOP('',(#2551,#2558,#2559,#2560));
#2562=FACE_BOUND('',#2561,.T.);
#2563=ADVANCED_FACE('F2069',(#2562),#2543,.F.);
#2564=CARTESIAN_POINT('',(89.,33.,17.9831336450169));
#2565=DIRECTION('',(0.,0.,-1.));
#2566=DIRECTION('',(0.,1.,0.));
#2567=AXIS2_PLACEMENT_3D('',#2564,#2565,#2566);
#2568=PLANE('',#2567);
#2569=ORIENTED_EDGE('',*,*,#2411,.T.);
#2570=DIRECTION('',(0.,-1.,0.));
#2571=VECTOR('',#2570,1.);
#2572=CARTESIAN_POINT('',(94.,26.,17.983133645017));
#2573=LINE('',#2572,#2571);
#2574=EDGE_CURVE('E1417',#2404,#2549,#2573,.T.);
#2575=ORIENTED_EDGE('',*,*,#2574,.T.);
#2576=ORIENTED_EDGE('',*,*,#2550,.F.);
#2577=ORIENTED_EDGE('',*,*,#727,.F.);
#2578=EDGE_LOOP('',(#2569,#2575,#2576,#2577));
#2579=FACE_BOUND('',#2578,.T.);
#2580=ADVANCED_FACE('F2079',(#2579),#2568,.T.);
#2581=CARTESIAN_POINT('',(-89.,19.,43.));
#2582=DIRECTION('',(-1.,0.,0.));
#2583=DIRECTION('',(0.,0.,1.));
#2584=AXIS2_PLACEMENT_3D('',#2581,#2582,#2583);
#2585=CYLINDRICAL_SURFACE('',#2584,6.25000000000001);
#2586=ORIENTED_EDGE('',*,*,#326,.T.);
#2587=EDGE_LOOP('',(#2586));
#2588=FACE_BOUND('',#2587,.T.);
#2589=ORIENTED_EDGE('',*,*,#1139,.T.);
#2590=EDGE_LOOP('',(#2589));
#2591=FACE_BOUND('',#2590,.T.);
#2592=ADVANCED_FACE('F2087',(#2588,#2591),#2585,.F.);
#2593=CARTESIAN_POINT('',(-89.,19.,21.));
#2594=DIRECTION('',(-1.,0.,0.));
#2595=DIRECTION('',(0.,0.,1.));
#2596=AXIS2_PLACEMENT_3D('',#2593,#2594,#2595);
#2597=CYLINDRICAL_SURFACE('',#2596,6.25);
#2598=ORIENTED_EDGE('',*,*,#315,.T.);
#2599=EDGE_LOOP('',(#2598));
#2600=FACE_BOUND('',#2599,.T.);
#2601=ORIENTED_EDGE('',*,*,#1128,.T.);
#2602=EDGE_LOOP('',(#2601));
#2603=FACE_BOUND('',#2602,.T.);
#2604=ADVANCED_FACE('F2096',(#2600,#2603),#2597,.F.);
#2605=CARTESIAN_POINT('',(-89.,41.,21.));
#2606=DIRECTION('',(-1.,0.,0.));
#2607=DIRECTION('',(0.,0.,1.));
#2608=AXIS2_PLACEMENT_3D('',#2605,#2606,#2607);
#2609=CYLINDRICAL_SURFACE('',#2608,6.25);
#2610=ORIENTED_EDGE('',*,*,#304,.T.);
#2611=EDGE_LOOP('',(#2610));
#2612=FACE_BOUND('',#2611,.T.);
#2613=ORIENTED_EDGE('',*,*,#1117,.T.);
#2614=EDGE_LOOP('',(#2613));
#2615=FACE_BOUND('',#2614,.T.);
#2616=ADVANCED_FACE('F1494',(#2612,#2615),#2609,.F.);
#2617=CARTESIAN_POINT('',(-89.,30.,-7.99999999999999));
#2618=DIRECTION('',(-1.,0.,0.));
#2619=DIRECTION('',(0.,0.,1.));
#2620=AXIS2_PLACEMENT_3D('',#2617,#2618,#2619);
#2621=CYLINDRICAL_SURFACE('',#2620,6.6);
#2622=DIRECTION('',(-1.,0.,0.));
#2623=VECTOR('',#2622,1.);
#2624=CARTESIAN_POINT('',(-89.,33.,-2.12122461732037));
#2625=LINE('',#2624,#2623);
#2626=CARTESIAN_POINT('',(-94.8,33.,-2.12122461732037));
#2627=VERTEX_POINT('',#2626);
#2628=EDGE_CURVE('E903',#237,#2627,#2625,.T.);
#2629=ORIENTED_EDGE('',*,*,#2628,.T.);
#2630=CARTESIAN_POINT('',(-94.8,30.,-7.99999999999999));
#2631=DIRECTION('',(1.,0.,0.));
#2632=DIRECTION('',(0.,0.,-1.));
#2633=AXIS2_PLACEMENT_3D('',#2630,#2631,#2632);
#2634=CIRCLE('',#2633,6.6);
#2635=CARTESIAN_POINT('',(-94.8,27.,-2.12122461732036));
#2636=VERTEX_POINT('',#2635);
#2637=EDGE_CURVE('E1433',#2627,#2636,#2634,.F.);
#2638=ORIENTED_EDGE('',*,*,#2637,.T.);
#2639=DIRECTION('',(-1.,0.,0.));
#2640=VECTOR('',#2639,1.);
#2641=CARTESIAN_POINT('',(-89.,27.,-2.12122461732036));
#2642=LINE('',#2641,#2640);
#2643=EDGE_CURVE('E895',#235,#2636,#2642,.T.);
#2644=ORIENTED_EDGE('',*,*,#2643,.F.);
#2645=ORIENTED_EDGE('',*,*,#238,.T.);
#2646=EDGE_LOOP('',(#2629,#2638,#2644,#2645));
#2647=FACE_BOUND('',#2646,.T.);
#2648=ADVANCED_FACE('F1485',(#2647),#2621,.F.);
#2649=CARTESIAN_POINT('',(-89.,33.,-2.12122461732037));
#2650=DIRECTION('',(0.,1.,0.));
#2651=DIRECTION('',(0.,0.,1.));
#2652=AXIS2_PLACEMENT_3D('',#2649,#2650,#2651);
#2653=PLANE('',#2652);
#2654=ORIENTED_EDGE('',*,*,#1100,.T.);
#2655=CARTESIAN_POINT('',(-95.,33.,-1.89754147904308));
#2656=CARTESIAN_POINT('',(-94.9665973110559,33.,-1.93475998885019));
#2657=CARTESIAN_POINT('',(-94.933229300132,33.,-1.97200950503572));
#2658=CARTESIAN_POINT('',(-94.8665626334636,33.,-2.04657055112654));
#2659=CARTESIAN_POINT('',(-94.8332639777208,33.,-2.08388208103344));
#2660=CARTESIAN_POINT('',(-94.8,33.,-2.12122461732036));
#2661=B_SPLINE_CURVE_WITH_KNOTS('',3,(#2655,#2656,#2657,#2658,#2659,#2660),.UNSPECIFIED.,.F.,
.F.,(4,2,4),(0.,0.150028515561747,0.300057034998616),.UNSPECIFIED.);
#2662=EDGE_CURVE('E1495',#1091,#2627,#2661,.T.);
#2663=ORIENTED_EDGE('',*,*,#2662,.T.);
#2664=ORIENTED_EDGE('',*,*,#2628,.F.);
#2665=ORIENTED_EDGE('',*,*,#260,.T.);
#2666=DIRECTION('',(-1.,0.,0.));
#2667=VECTOR('',#2666,1.);
#2668=CARTESIAN_POINT('',(-89.,33.,-1.39999999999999));
#2669=LINE('',#2668,#2667);
#2670=EDGE_CURVE('E902',#253,#1099,#2669,.T.);
#2671=ORIENTED_EDGE('',*,*,#2670,.T.);
#2672=EDGE_LOOP('',(#2654,#2663,#2664,#2665,#2671));
#2673=FACE_BOUND('',#2672,.T.);
#2674=ADVANCED_FACE('F1489',(#2673),#2653,.F.);
#2675=CARTESIAN_POINT('',(-89.,33.,-1.39999999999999));
#2676=DIRECTION('',(0.,0.,1.));
#2677=DIRECTION('',(1.,0.,0.));
#2678=AXIS2_PLACEMENT_3D('',#2675,#2676,#2677);
#2679=PLANE('',#2678);
#2680=ORIENTED_EDGE('',*,*,#254,.T.);
#2681=DIRECTION('',(-1.,0.,0.));
#2682=VECTOR('',#2681,1.);
#2683=CARTESIAN_POINT('',(-89.,27.,-1.39999999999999));
#2684=LINE('',#2683,#2682);
#2685=EDGE_CURVE('E899',#245,#1082,#2684,.T.);
#2686=ORIENTED_EDGE('',*,*,#2685,.T.);
#2687=ORIENTED_EDGE('',*,*,#1106,.T.);
#2688=ORIENTED_EDGE('',*,*,#2670,.F.);
#2689=EDGE_LOOP('',(#2680,#2686,#2687,#2688));
#2690=FACE_BOUND('',#2689,.T.);
#2691=ADVANCED_FACE('F1479',(#2690),#2679,.F.);
#2692=CARTESIAN_POINT('',(-89.,27.,-2.12122461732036));
#2693=DIRECTION('',(0.,-1.,0.));
#2694=DIRECTION('',(0.,0.,-1.));
#2695=AXIS2_PLACEMENT_3D('',#2692,#2693,#2694);
#2696=PLANE('',#2695);
#2697=ORIENTED_EDGE('',*,*,#2643,.T.);
#2698=CARTESIAN_POINT('',(-94.8,27.,-2.12122461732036));
#2699=CARTESIAN_POINT('',(-94.8332639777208,27.,-2.08388208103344));
#2700=CARTESIAN_POINT('',(-94.8665626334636,27.,-2.04657055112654));
#2701=CARTESIAN_POINT('',(-94.933229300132,27.,-1.97200950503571));
#2702=CARTESIAN_POINT('',(-94.9665973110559,27.,-1.93475998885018));
#2703=CARTESIAN_POINT('',(-95.,27.,-1.89754147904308));
#2704=B_SPLINE_CURVE_WITH_KNOTS('',3,(#2698,#2699,#2700,#2701,#2702,#2703),.UNSPECIFIED.,.F.,
.F.,(4,2,4),(0.,0.15002851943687,0.30005703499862),.UNSPECIFIED.);
#2705=EDGE_CURVE('E1460',#2636,#1080,#2704,.T.);
#2706=ORIENTED_EDGE('',*,*,#2705,.T.);
#2707=ORIENTED_EDGE('',*,*,#1083,.T.);
#2708=ORIENTED_EDGE('',*,*,#2685,.F.);
#2709=ORIENTED_EDGE('',*,*,#246,.T.);
#2710=EDGE_LOOP('',(#2697,#2706,#2707,#2708,#2709));
#2711=FACE_BOUND('',#2710,.T.);
#2712=ADVANCED_FACE('F1472',(#2711),#2696,.F.);
#2713=CARTESIAN_POINT('',(-89.,41.,43.));
#2714=DIRECTION('',(-1.,0.,0.));
#2715=DIRECTION('',(0.,0.,1.));
#2716=AXIS2_PLACEMENT_3D('',#2713,#2714,#2715);
#2717=CYLINDRICAL_SURFACE('',#2716,6.25000000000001);
#2718=ORIENTED_EDGE('',*,*,#293,.T.);
#2719=EDGE_LOOP('',(#2718));
#2720=FACE_BOUND('',#2719,.T.);
#2721=ORIENTED_EDGE('',*,*,#1071,.T.);
#2722=EDGE_LOOP('',(#2721));
#2723=FACE_BOUND('',#2722,.T.);
#2724=ADVANCED_FACE('F1478',(#2720,#2723),#2717,.F.);
#2725=CARTESIAN_POINT('',(-89.,39.5,-7.99999999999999));
#2726=DIRECTION('',(-1.,0.,0.));
#2727=DIRECTION('',(0.,0.,1.));
#2728=AXIS2_PLACEMENT_3D('',#2725,#2726,#2727);
#2729=CYLINDRICAL_SURFACE('',#2728,1.6);
#2730=ORIENTED_EDGE('',*,*,#271,.T.);
#2731=EDGE_LOOP('',(#2730));
#2732=FACE_BOUND('',#2731,.T.);
#2733=ORIENTED_EDGE('',*,*,#1060,.T.);
#2734=EDGE_LOOP('',(#2733));
#2735=FACE_BOUND('',#2734,.T.);
#2736=ADVANCED_FACE('F2152',(#2732,#2735),#2729,.F.);
#2737=CARTESIAN_POINT('',(-89.,20.5,-7.99999999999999));
#2738=DIRECTION('',(-1.,0.,0.));
#2739=DIRECTION('',(0.,0.,1.));
#2740=AXIS2_PLACEMENT_3D('',#2737,#2738,#2739);
#2741=CYLINDRICAL_SURFACE('',#2740,1.6);
#2742=ORIENTED_EDGE('',*,*,#282,.T.);
#2743=EDGE_LOOP('',(#2742));
#2744=FACE_BOUND('',#2743,.T.);
#2745=ORIENTED_EDGE('',*,*,#1049,.T.);
#2746=EDGE_LOOP('',(#2745));
#2747=FACE_BOUND('',#2746,.T.);
#2748=ADVANCED_FACE('F2165',(#2744,#2747),#2741,.F.);
#2749=CARTESIAN_POINT('',(-89.,44.35,-34.7737095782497));
#2750=DIRECTION('',(0.,0.,1.));
#2751=DIRECTION('',(0.,-1.,0.));
#2752=AXIS2_PLACEMENT_3D('',#2749,#2750,#2751);
#2753=PLANE('',#2752);
#2754=ORIENTED_EDGE('',*,*,#103,.T.);
#2755=DIRECTION('',(-1.,0.,0.));
#2756=VECTOR('',#2755,1.);
#2757=CARTESIAN_POINT('',(-89.,15.65,-34.7737095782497));
#2758=LINE('',#2757,#2756);
#2759=EDGE_CURVE('E868',#102,#1023,#2758,.T.);
#2760=ORIENTED_EDGE('',*,*,#2759,.T.);
#2761=ORIENTED_EDGE('',*,*,#1024,.T.);
#2762=DIRECTION('',(-1.,0.,0.));
#2763=VECTOR('',#2762,1.);
#2764=CARTESIAN_POINT('',(-89.,44.35,-34.7737095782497));
#2765=LINE('',#2764,#2763);
#2766=EDGE_CURVE('E870',#100,#1013,#2765,.T.);
#2767=ORIENTED_EDGE('',*,*,#2766,.F.);
#2768=EDGE_LOOP('',(#2754,#2760,#2761,#2767));
#2769=FACE_BOUND('',#2768,.T.);
#2770=ADVANCED_FACE('F2174',(#2769),#2753,.F.);
#2771=CARTESIAN_POINT('',(-89.,15.65,-48.7737095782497));
#2772=DIRECTION('',(0.,-1.,0.));
#2773=DIRECTION('',(0.,0.,-1.));
#2774=AXIS2_PLACEMENT_3D('',#2771,#2772,#2773);
#2775=PLANE('',#2774);
#2776=ORIENTED_EDGE('',*,*,#125,.T.);
#2777=DIRECTION('',(-1.,0.,0.));
#2778=VECTOR('',#2777,1.);
#2779=CARTESIAN_POINT('',(-89.,15.65,-48.7737095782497));
#2780=LINE('',#2779,#2778);
#2781=EDGE_CURVE('E871',#118,#1031,#2780,.T.);
#2782=ORIENTED_EDGE('',*,*,#2781,.T.);
#2783=ORIENTED_EDGE('',*,*,#1032,.T.);
#2784=ORIENTED_EDGE('',*,*,#2759,.F.);
#2785=EDGE_LOOP('',(#2776,#2782,#2783,#2784));
#2786=FACE_BOUND('',#2785,.T.);
#2787=ADVANCED_FACE('F2181',(#2786),#2775,.F.);
#2788=CARTESIAN_POINT('',(-89.,44.35,-48.7737095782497));
#2789=DIRECTION('',(0.,0.,-1.));
#2790=DIRECTION('',(0.,1.,0.));
#2791=AXIS2_PLACEMENT_3D('',#2788,#2789,#2790);
#2792=PLANE('',#2791);
#2793=ORIENTED_EDGE('',*,*,#119,.T.);
#2794=DIRECTION('',(-1.,0.,0.));
#2795=VECTOR('',#2794,1.);
#2796=CARTESIAN_POINT('',(-89.,44.35,-48.7737095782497));
#2797=LINE('',#2796,#2795);
#2798=EDGE_CURVE('E873',#110,#1015,#2797,.T.);
#2799=ORIENTED_EDGE('',*,*,#2798,.T.);
#2800=ORIENTED_EDGE('',*,*,#1038,.T.);
#2801=ORIENTED_EDGE('',*,*,#2781,.F.);
#2802=EDGE_LOOP('',(#2793,#2799,#2800,#2801));
#2803=FACE_BOUND('',#2802,.T.);
#2804=ADVANCED_FACE('F2192',(#2803),#2792,.F.);
#2805=CARTESIAN_POINT('',(-89.,44.35,-48.7737095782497));
#2806=DIRECTION('',(0.,1.,0.));
#2807=DIRECTION('',(0.,0.,1.));
#2808=AXIS2_PLACEMENT_3D('',#2805,#2806,#2807);
#2809=PLANE('',#2808);
#2810=ORIENTED_EDGE('',*,*,#111,.T.);
#2811=ORIENTED_EDGE('',*,*,#2766,.T.);
#2812=ORIENTED_EDGE('',*,*,#1016,.T.);
#2813=ORIENTED_EDGE('',*,*,#2798,.F.);
#2814=EDGE_LOOP('',(#2810,#2811,#2812,#2813));
#2815=FACE_BOUND('',#2814,.T.);
#2816=ADVANCED_FACE('F2203',(#2815),#2809,.F.);
#2817=CARTESIAN_POINT('',(-95.,1.,70.));
#2818=DIRECTION('',(0.,0.707106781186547,-0.707106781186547));
#2819=DIRECTION('',(1.,0.,0.));
#2820=AXIS2_PLACEMENT_3D('',#2817,#2818,#2819);
#2821=PLANE('',#2820);
#2822=DIRECTION('',(0.,0.707106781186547,0.707106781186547));
#2823=VECTOR('',#2822,1.);
#2824=CARTESIAN_POINT('',(-90.,0.,69.));
#2825=LINE('',#2824,#2823);
#2826=EDGE_CURVE('E1241',#1454,#1206,#2825,.T.);
#2827=ORIENTED_EDGE('',*,*,#2826,.F.);
#2828=ORIENTED_EDGE('',*,*,#1455,.F.);
#2829=DIRECTION('',(0.,-0.707106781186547,-0.707106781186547));
#2830=VECTOR('',#2829,1.);
#2831=CARTESIAN_POINT('',(90.,1.,70.));
#2832=LINE('',#2831,#2830);
#2833=EDGE_CURVE('E886',#1188,#1446,#2832,.T.);
#2834=ORIENTED_EDGE('',*,*,#2833,.F.);
#2835=ORIENTED_EDGE('',*,*,#1213,.F.);
#2836=EDGE_LOOP('',(#2827,#2828,#2834,#2835));
#2837=FACE_BOUND('',#2836,.T.);
#2838=ADVANCED_FACE('F1607',(#2837),#2821,.F.);
#2839=CARTESIAN_POINT('',(90.,0.,65.));
#2840=DIRECTION('',(0.,1.,0.));
#2841=DIRECTION('',(0.,0.,1.));
#2842=AXIS2_PLACEMENT_3D('',#2839,#2840,#2841);
#2843=CONICAL_SURFACE('',#2842,4.,0.785398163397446);
#2844=ORIENTED_EDGE('',*,*,#2833,.T.);
#2845=ORIENTED_EDGE('',*,*,#1447,.F.);
#2846=DIRECTION('',(-0.707106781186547,-0.707106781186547,0.));
#2847=VECTOR('',#2846,1.);
#2848=CARTESIAN_POINT('',(95.,1.,65.));
#2849=LINE('',#2848,#2847);
#2850=EDGE_CURVE('E1236',#871,#1437,#2849,.T.);
#2851=ORIENTED_EDGE('',*,*,#2850,.F.);
#2852=ORIENTED_EDGE('',*,*,#1610,.F.);
#2853=EDGE_LOOP('',(#2844,#2845,#2851,#2852));
#2854=FACE_BOUND('',#2853,.T.);
#2855=ADVANCED_FACE('F1605',(#2854),#2843,.T.);
#2856=CARTESIAN_POINT('',(-90.,0.,65.));
#2857=DIRECTION('',(0.,1.,0.));
#2858=DIRECTION('',(0.,0.,1.));
#2859=AXIS2_PLACEMENT_3D('',#2856,#2857,#2858);
#2860=CONICAL_SURFACE('',#2859,4.,0.785398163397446);
#2861=ORIENTED_EDGE('',*,*,#2826,.T.);
#2862=ORIENTED_EDGE('',*,*,#1538,.F.);
#2863=DIRECTION('',(-0.707106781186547,0.707106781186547,0.));
#2864=VECTOR('',#2863,1.);
#2865=CARTESIAN_POINT('',(-94.,0.,65.));
#2866=LINE('',#2865,#2864);
#2867=EDGE_CURVE('E1234',#1463,#1148,#2866,.T.);
#2868=ORIENTED_EDGE('',*,*,#2867,.F.);
#2869=ORIENTED_EDGE('',*,*,#1464,.F.);
#2870=EDGE_LOOP('',(#2861,#2862,#2868,#2869));
#2871=FACE_BOUND('',#2870,.T.);
#2872=ADVANCED_FACE('F1613',(#2871),#2860,.T.);
#2873=CARTESIAN_POINT('',(95.,1.,-70.));
#2874=DIRECTION('',(-0.707106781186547,0.707106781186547,0.));
#2875=DIRECTION('',(0.,0.,-1.));
#2876=AXIS2_PLACEMENT_3D('',#2873,#2874,#2875);
#2877=PLANE('',#2876);
#2878=ORIENTED_EDGE('',*,*,#2850,.T.);
#2879=ORIENTED_EDGE('',*,*,#1438,.F.);
#2880=DIRECTION('',(-0.707106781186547,-0.707106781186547,0.));
#2881=VECTOR('',#2880,1.);
#2882=CARTESIAN_POINT('',(95.,1.,-65.));
#2883=LINE('',#2882,#2881);
#2884=EDGE_CURVE('E1232',#853,#1429,#2883,.T.);
#2885=ORIENTED_EDGE('',*,*,#2884,.F.);
#2886=ORIENTED_EDGE('',*,*,#878,.F.);
#2887=EDGE_LOOP('',(#2878,#2879,#2885,#2886));
#2888=FACE_BOUND('',#2887,.T.);
#2889=ADVANCED_FACE('F1600',(#2888),#2877,.F.);
#2890=CARTESIAN_POINT('',(-95.,1.,-70.));
#2891=DIRECTION('',(0.707106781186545,0.70710678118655,0.));
#2892=DIRECTION('',(0.,0.,1.));
#2893=AXIS2_PLACEMENT_3D('',#2890,#2891,#2892);
#2894=PLANE('',#2893);
#2895=ORIENTED_EDGE('',*,*,#2867,.T.);
#2896=ORIENTED_EDGE('',*,*,#1173,.F.);
#2897=DIRECTION('',(-0.707106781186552,0.707106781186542,0.));
#2898=VECTOR('',#2897,1.);
#2899=CARTESIAN_POINT('',(-94.,0.,-65.));
#2900=LINE('',#2899,#2898);
#2901=EDGE_CURVE('E1229',#1410,#1166,#2900,.T.);
#2902=ORIENTED_EDGE('',*,*,#2901,.F.);
#2903=ORIENTED_EDGE('',*,*,#1470,.F.);
#2904=EDGE_LOOP('',(#2895,#2896,#2902,#2903));
#2905=FACE_BOUND('',#2904,.T.);
#2906=ADVANCED_FACE('F1574',(#2905),#2894,.F.);
#2907=CARTESIAN_POINT('',(90.,0.,-65.));
#2908=DIRECTION('',(0.,1.,0.));
#2909=DIRECTION('',(0.,0.,1.));
#2910=AXIS2_PLACEMENT_3D('',#2907,#2908,#2909);
#2911=CONICAL_SURFACE('',#2910,4.,0.785398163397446);
#2912=ORIENTED_EDGE('',*,*,#2884,.T.);
#2913=ORIENTED_EDGE('',*,*,#1430,.F.);
#2914=DIRECTION('',(0.,-0.707106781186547,0.707106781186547));
#2915=VECTOR('',#2914,1.);
#2916=CARTESIAN_POINT('',(90.,1.,-70.));
#2917=LINE('',#2916,#2915);
#2918=EDGE_CURVE('E1230',#991,#1420,#2917,.T.);
#2919=ORIENTED_EDGE('',*,*,#2918,.F.);
#2920=ORIENTED_EDGE('',*,*,#1586,.F.);
#2921=EDGE_LOOP('',(#2912,#2913,#2919,#2920));
#2922=FACE_BOUND('',#2921,.T.);
#2923=ADVANCED_FACE('F1594',(#2922),#2911,.T.);
#2924=CARTESIAN_POINT('',(-90.,0.,-65.));
#2925=DIRECTION('',(0.,1.,0.));
#2926=DIRECTION('',(0.,0.,1.));
#2927=AXIS2_PLACEMENT_3D('',#2924,#2925,#2926);
#2928=CONICAL_SURFACE('',#2927,4.,0.785398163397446);
#2929=ORIENTED_EDGE('',*,*,#2901,.T.);
#2930=ORIENTED_EDGE('',*,*,#1562,.F.);
#2931=DIRECTION('',(0.,0.707106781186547,-0.707106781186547));
#2932=VECTOR('',#2931,1.);
#2933=CARTESIAN_POINT('',(-90.,0.,-69.));
#2934=LINE('',#2933,#2932);
#2935=EDGE_CURVE('E835',#1412,#973,#2934,.T.);
#2936=ORIENTED_EDGE('',*,*,#2935,.F.);
#2937=ORIENTED_EDGE('',*,*,#1413,.F.);
#2938=EDGE_LOOP('',(#2929,#2930,#2936,#2937));
#2939=FACE_BOUND('',#2938,.T.);
#2940=ADVANCED_FACE('F1579',(#2939),#2928,.T.);
#2941=CARTESIAN_POINT('',(-95.,1.,-70.));
#2942=DIRECTION('',(0.,0.707106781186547,0.707106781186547));
#2943=DIRECTION('',(-1.,0.,0.));
#2944=AXIS2_PLACEMENT_3D('',#2941,#2942,#2943);
#2945=PLANE('',#2944);
#2946=ORIENTED_EDGE('',*,*,#2918,.T.);
#2947=ORIENTED_EDGE('',*,*,#1421,.F.);
#2948=ORIENTED_EDGE('',*,*,#2935,.T.);
#2949=ORIENTED_EDGE('',*,*,#998,.F.);
#2950=EDGE_LOOP('',(#2946,#2947,#2948,#2949));
#2951=FACE_BOUND('',#2950,.T.);
#2952=ADVANCED_FACE('F1589',(#2951),#2945,.F.);
#2953=CARTESIAN_POINT('',(-82.,60.,9.74685594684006));
#2954=DIRECTION('',(0.,0.,-1.));
#2955=DIRECTION('',(-1.,0.,0.));
#2956=AXIS2_PLACEMENT_3D('',#2953,#2954,#2955);
#2957=PLANE('',#2956);
#2958=ORIENTED_EDGE('',*,*,#585,.T.);
#2959=DIRECTION('',(1.,0.,0.));
#2960=VECTOR('',#2959,1.);
#2961=CARTESIAN_POINT('',(-82.,4.00000000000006,9.74685594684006));
#2962=LINE('',#2961,#2960);
#2963=CARTESIAN_POINT('',(-82.,4.00000000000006,9.74685594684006));
#2964=VERTEX_POINT('',#2963);
#2965=EDGE_CURVE('E1353',#578,#2964,#2962,.T.);
#2966=ORIENTED_EDGE('',*,*,#2965,.T.);
#2967=DIRECTION('',(-0.707106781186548,0.707106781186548,0.));
#2968=VECTOR('',#2967,1.);
#2969=CARTESIAN_POINT('',(-110.,32.,9.74685594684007));
#2970=LINE('',#2969,#2968);
#2971=CARTESIAN_POINT('',(-82.14,4.13999999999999,9.74685594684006));
#2972=VERTEX_POINT('',#2971);
#2973=EDGE_CURVE('E1377',#2964,#2972,#2970,.T.);
#2974=ORIENTED_EDGE('',*,*,#2973,.T.);
#2975=DIRECTION('',(-0.121891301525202,0.992543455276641,0.));
#2976=VECTOR('',#2975,1.);
#2977=CARTESIAN_POINT('',(-88.8959975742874,59.1531231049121,9.74685594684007));
#2978=LINE('',#2977,#2976);
#2979=CARTESIAN_POINT('',(-88.784324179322,58.2437826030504,9.74685594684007));
#2980=VERTEX_POINT('',#2979);
#2981=EDGE_CURVE('E812',#2972,#2980,#2978,.T.);
#2982=ORIENTED_EDGE('',*,*,#2981,.T.);
#2983=CARTESIAN_POINT('',(-90.7694110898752,58.,9.74685594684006));
#2984=DIRECTION('',(0.,0.,-1.));
#2985=DIRECTION('',(-1.,0.,0.));
#2986=AXIS2_PLACEMENT_3D('',#2983,#2984,#2985);
#2987=CIRCLE('',#2986,2.);
#2988=EDGE_CURVE('E1314',#2980,#78,#2987,.F.);
#2989=ORIENTED_EDGE('',*,*,#2988,.T.);
#2990=ORIENTED_EDGE('',*,*,#79,.T.);
#2991=ORIENTED_EDGE('',*,*,#195,.T.);
#2992=EDGE_LOOP('',(#2958,#2966,#2974,#2982,#2989,#2990,#2991));
#2993=FACE_BOUND('',#2992,.T.);
#2994=ADVANCED_FACE('F2266',(#2993),#2957,.F.);
#2995=CARTESIAN_POINT('',(-82.,60.,6.74685594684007));
#2996=DIRECTION('',(0.,0.,1.));
#2997=DIRECTION('',(1.,0.,0.));
#2998=AXIS2_PLACEMENT_3D('',#2995,#2996,#2997);
#2999=PLANE('',#2998);
#3000=DIRECTION('',(0.121891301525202,-0.992543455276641,0.));
#3001=VECTOR('',#3000,1.);
#3002=CARTESIAN_POINT('',(-88.8959975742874,59.1531231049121,6.74685594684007));
#3003=LINE('',#3002,#3001);
#3004=CARTESIAN_POINT('',(-88.784324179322,58.2437826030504,6.74685594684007));
#3005=VERTEX_POINT('',#3004);
#3006=CARTESIAN_POINT('',(-82.14,4.13999999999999,6.74685594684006));
#3007=VERTEX_POINT('',#3006);
#3008=EDGE_CURVE('E811',#3005,#3007,#3003,.T.);
#3009=ORIENTED_EDGE('',*,*,#3008,.T.);
#3010=DIRECTION('',(0.707106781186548,-0.707106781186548,0.));
#3011=VECTOR('',#3010,1.);
#3012=CARTESIAN_POINT('',(-110.,32.,6.74685594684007));
#3013=LINE('',#3012,#3011);
#3014=CARTESIAN_POINT('',(-82.,4.00000000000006,6.74685594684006));
#3015=VERTEX_POINT('',#3014);
#3016=EDGE_CURVE('E1374',#3007,#3015,#3013,.T.);
#3017=ORIENTED_EDGE('',*,*,#3016,.T.);
#3018=DIRECTION('',(-1.,0.,0.));
#3019=VECTOR('',#3018,1.);
#3020=CARTESIAN_POINT('',(-82.,4.00000000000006,6.74685594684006));
#3021=LINE('',#3020,#3019);
#3022=EDGE_CURVE('E1351',#3015,#626,#3021,.T.);
#3023=ORIENTED_EDGE('',*,*,#3022,.T.);
#3024=ORIENTED_EDGE('',*,*,#627,.T.);
#3025=ORIENTED_EDGE('',*,*,#204,.T.);
#3026=ORIENTED_EDGE('',*,*,#67,.F.);
#3027=CARTESIAN_POINT('',(-90.7694110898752,58.,6.74685594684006));
#3028=DIRECTION('',(0.,0.,1.));
#3029=DIRECTION('',(1.,0.,0.));
#3030=AXIS2_PLACEMENT_3D('',#3027,#3028,#3029);
#3031=CIRCLE('',#3030,2.);
#3032=EDGE_CURVE('E1316',#64,#3005,#3031,.F.);
#3033=ORIENTED_EDGE('',*,*,#3032,.T.);
#3034=EDGE_LOOP('',(#3009,#3017,#3023,#3024,#3025,#3026,#3033));
#3035=FACE_BOUND('',#3034,.T.);
#3036=ADVANCED_FACE('F2331',(#3035),#2999,.F.);
#3037=CARTESIAN_POINT('',(-82.,3.,-25.4080157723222));
#3038=DIRECTION('',(0.,0.,-1.));
#3039=DIRECTION('',(-1.,0.,0.));
#3040=AXIS2_PLACEMENT_3D('',#3037,#3038,#3039);
#3041=PLANE('',#3040);
#3042=ORIENTED_EDGE('',*,*,#618,.T.);
#3043=DIRECTION('',(1.,0.,0.));
#3044=VECTOR('',#3043,1.);
#3045=CARTESIAN_POINT('',(-82.,4.,-25.4080157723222));
#3046=LINE('',#3045,#3044);
#3047=CARTESIAN_POINT('',(-82.,4.,-25.4080157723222));
#3048=VERTEX_POINT('',#3047);
#3049=EDGE_CURVE('E1350',#611,#3048,#3046,.T.);
#3050=ORIENTED_EDGE('',*,*,#3049,.T.);
#3051=DIRECTION('',(-0.707106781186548,0.707106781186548,0.));
#3052=VECTOR('',#3051,1.);
#3053=CARTESIAN_POINT('',(-81.5,3.5,-25.4080157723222));
#3054=LINE('',#3053,#3052);
#3055=CARTESIAN_POINT('',(-82.14,4.14,-25.4080157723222));
#3056=VERTEX_POINT('',#3055);
#3057=EDGE_CURVE('E1372',#3048,#3056,#3054,.T.);
#3058=ORIENTED_EDGE('',*,*,#3057,.T.);
#3059=DIRECTION('',(-0.121891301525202,0.992543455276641,0.));
#3060=VECTOR('',#3059,1.);
#3061=CARTESIAN_POINT('',(-82.,3.,-25.4080157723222));
#3062=LINE('',#3061,#3060);
#3063=CARTESIAN_POINT('',(-88.784324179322,58.2437826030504,-25.4080157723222));
#3064=VERTEX_POINT('',#3063);
#3065=EDGE_CURVE('E808',#3056,#3064,#3062,.T.);
#3066=ORIENTED_EDGE('',*,*,#3065,.T.);
#3067=CARTESIAN_POINT('',(-90.7694110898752,58.,-25.4080157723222));
#3068=DIRECTION('',(0.,0.,-1.));
#3069=DIRECTION('',(-1.,0.,0.));
#3070=AXIS2_PLACEMENT_3D('',#3067,#3068,#3069);
#3071=CIRCLE('',#3070,2.);
#3072=EDGE_CURVE('E1305',#3064,#47,#3071,.F.);
#3073=ORIENTED_EDGE('',*,*,#3072,.T.);
#3074=ORIENTED_EDGE('',*,*,#48,.T.);
#3075=ORIENTED_EDGE('',*,*,#214,.T.);
#3076=EDGE_LOOP('',(#3042,#3050,#3058,#3066,#3073,#3074,#3075));
#3077=FACE_BOUND('',#3076,.T.);
#3078=ADVANCED_FACE('F2342',(#3077),#3041,.F.);
#3079=CARTESIAN_POINT('',(-82.,3.,-28.4080157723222));
#3080=DIRECTION('',(0.,0.,1.));
#3081=DIRECTION('',(1.,0.,0.));
#3082=AXIS2_PLACEMENT_3D('',#3079,#3080,#3081);
#3083=PLANE('',#3082);
#3084=DIRECTION('',(-0.121891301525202,0.992543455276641,0.));
#3085=VECTOR('',#3084,1.);
#3086=CARTESIAN_POINT('',(-82.,3.,-28.4080157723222));
#3087=LINE('',#3086,#3085);
#3088=CARTESIAN_POINT('',(-82.14,4.14,-28.4080157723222));
#3089=VERTEX_POINT('',#3088);
#3090=CARTESIAN_POINT('',(-88.784324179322,58.2437826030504,-28.4080157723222));
#3091=VERTEX_POINT('',#3090);
#3092=EDGE_CURVE('E804',#3089,#3091,#3087,.T.);
#3093=ORIENTED_EDGE('',*,*,#3092,.F.);
#3094=DIRECTION('',(0.707106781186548,-0.707106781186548,0.));
#3095=VECTOR('',#3094,1.);
#3096=CARTESIAN_POINT('',(-81.5,3.5,-28.4080157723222));
#3097=LINE('',#3096,#3095);
#3098=CARTESIAN_POINT('',(-82.,4.00000000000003,-28.4080157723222));
#3099=VERTEX_POINT('',#3098);
#3100=EDGE_CURVE('E1367',#3089,#3099,#3097,.T.);
#3101=ORIENTED_EDGE('',*,*,#3100,.T.);
#3102=DIRECTION('',(-1.,0.,0.));
#3103=VECTOR('',#3102,1.);
#3104=CARTESIAN_POINT('',(-82.,4.00000000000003,-28.4080157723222));
#3105=LINE('',#3104,#3103);
#3106=EDGE_CURVE('E739',#3099,#643,#3105,.T.);
#3107=ORIENTED_EDGE('',*,*,#3106,.T.);
#3108=ORIENTED_EDGE('',*,*,#644,.T.);
#3109=ORIENTED_EDGE('',*,*,#223,.T.);
#3110=ORIENTED_EDGE('',*,*,#32,.F.);
#3111=CARTESIAN_POINT('',(-90.7694110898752,58.,-28.4080157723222));
#3112=DIRECTION('',(0.,0.,1.));
#3113=DIRECTION('',(1.,0.,0.));
#3114=AXIS2_PLACEMENT_3D('',#3111,#3112,#3113);
#3115=CIRCLE('',#3114,2.);
#3116=EDGE_CURVE('E1306',#29,#3091,#3115,.F.);
#3117=ORIENTED_EDGE('',*,*,#3116,.T.);
#3118=EDGE_LOOP('',(#3093,#3101,#3107,#3108,#3109,#3110,#3117));
#3119=FACE_BOUND('',#3118,.T.);
#3120=ADVANCED_FACE('F2353',(#3119),#3083,.F.);
#3121=CARTESIAN_POINT('',(-82.,3.,34.0694365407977));
#3122=DIRECTION('',(0.,0.,-1.));
#3123=DIRECTION('',(-1.,0.,0.));
#3124=AXIS2_PLACEMENT_3D('',#3121,#3122,#3123);
#3125=PLANE('',#3124);
#3126=ORIENTED_EDGE('',*,*,#560,.T.);
#3127=DIRECTION('',(1.,0.,0.));
#3128=VECTOR('',#3127,1.);
#3129=CARTESIAN_POINT('',(-82.,4.,34.0694365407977));
#3130=LINE('',#3129,#3128);
#3131=CARTESIAN_POINT('',(-82.,4.,34.0694365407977));
#3132=VERTEX_POINT('',#3131);
#3133=EDGE_CURVE('E1368',#553,#3132,#3130,.T.);
#3134=ORIENTED_EDGE('',*,*,#3133,.T.);
#3135=DIRECTION('',(-0.707106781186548,0.707106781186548,0.));
#3136=VECTOR('',#3135,1.);
#3137=CARTESIAN_POINT('',(-81.5,3.5,34.0694365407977));
#3138=LINE('',#3137,#3136);
#3139=CARTESIAN_POINT('',(-82.14,4.14,34.0694365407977));
#3140=VERTEX_POINT('',#3139);
#3141=EDGE_CURVE('E1383',#3132,#3140,#3138,.T.);
#3142=ORIENTED_EDGE('',*,*,#3141,.T.);
#3143=DIRECTION('',(0.121891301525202,-0.99254345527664,0.));
#3144=VECTOR('',#3143,1.);
#3145=CARTESIAN_POINT('',(-82.,3.,34.0694365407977));
#3146=LINE('',#3145,#3144);
#3147=CARTESIAN_POINT('',(-83.3389548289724,13.9029178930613,34.0694365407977));
#3148=VERTEX_POINT('',#3147);
#3149=EDGE_CURVE('E805',#3148,#3140,#3146,.T.);
#3150=ORIENTED_EDGE('',*,*,#3149,.F.);
#3151=CARTESIAN_POINT('',(-85.3240417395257,13.6591352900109,34.0694365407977));
#3152=DIRECTION('',(0.,0.,-1.));
#3153=DIRECTION('',(-1.,0.,0.));
#3154=AXIS2_PLACEMENT_3D('',#3151,#3152,#3153);
#3155=CIRCLE('',#3154,2.);
#3156=CARTESIAN_POINT('',(-85.3240417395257,15.6591352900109,34.0694365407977));
#3157=VERTEX_POINT('',#3156);
#3158=EDGE_CURVE('E1300',#3148,#3157,#3155,.F.);
#3159=ORIENTED_EDGE('',*,*,#3158,.T.);
#3160=DIRECTION('',(-1.,0.,0.));
#3161=VECTOR('',#3160,1.);
#3162=CARTESIAN_POINT('',(-82.,15.6591352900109,34.0694365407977));
#3163=LINE('',#3162,#3161);
#3164=EDGE_CURVE('E828',#3157,#168,#3163,.T.);
#3165=ORIENTED_EDGE('',*,*,#3164,.T.);
#3166=ORIENTED_EDGE('',*,*,#169,.T.);
#3167=EDGE_LOOP('',(#3126,#3134,#3142,#3150,#3159,#3165,#3166));
#3168=FACE_BOUND('',#3167,.T.);
#3169=ADVANCED_FACE('F2361',(#3168),#3125,.F.);
#3170=CARTESIAN_POINT('',(-82.,3.,31.0694365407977));
#3171=DIRECTION('',(0.,0.,1.));
#3172=DIRECTION('',(1.,0.,0.));
#3173=AXIS2_PLACEMENT_3D('',#3170,#3171,#3172);
#3174=PLANE('',#3173);
#3175=DIRECTION('',(0.121891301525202,-0.992543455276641,0.));
#3176=VECTOR('',#3175,1.);
#3177=CARTESIAN_POINT('',(-82.,3.,31.0694365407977));
#3178=LINE('',#3177,#3176);
#3179=CARTESIAN_POINT('',(-83.3389548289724,13.9029178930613,31.0694365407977));
#3180=VERTEX_POINT('',#3179);
#3181=CARTESIAN_POINT('',(-82.14,4.14,31.0694365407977));
#3182=VERTEX_POINT('',#3181);
#3183=EDGE_CURVE('E810',#3180,#3182,#3178,.T.);
#3184=ORIENTED_EDGE('',*,*,#3183,.T.);
#3185=DIRECTION('',(0.707106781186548,-0.707106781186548,0.));
#3186=VECTOR('',#3185,1.);
#3187=CARTESIAN_POINT('',(-81.5,3.5,31.0694365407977));
#3188=LINE('',#3187,#3186);
#3189=CARTESIAN_POINT('',(-82.,4.00000000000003,31.0694365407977));
#3190=VERTEX_POINT('',#3189);
#3191=EDGE_CURVE('E1378',#3182,#3190,#3188,.T.);
#3192=ORIENTED_EDGE('',*,*,#3191,.T.);
#3193=DIRECTION('',(-1.,0.,0.));
#3194=VECTOR('',#3193,1.);
#3195=CARTESIAN_POINT('',(-82.,4.00000000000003,31.0694365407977));
#3196=LINE('',#3195,#3194);
#3197=EDGE_CURVE('E1359',#3190,#593,#3196,.T.);
#3198=ORIENTED_EDGE('',*,*,#3197,.T.);
#3199=ORIENTED_EDGE('',*,*,#594,.T.);
#3200=ORIENTED_EDGE('',*,*,#185,.T.);
#3201=DIRECTION('',(-1.,0.,0.));
#3202=VECTOR('',#3201,1.);
#3203=CARTESIAN_POINT('',(-82.,15.6591352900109,31.0694365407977));
#3204=LINE('',#3203,#3202);
#3205=CARTESIAN_POINT('',(-85.3240417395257,15.6591352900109,31.0694365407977));
#3206=VERTEX_POINT('',#3205);
#3207=EDGE_CURVE('E826',#3206,#176,#3204,.T.);
#3208=ORIENTED_EDGE('',*,*,#3207,.F.);
#3209=CARTESIAN_POINT('',(-85.3240417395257,13.6591352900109,31.0694365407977));
#3210=DIRECTION('',(0.,0.,1.));
#3211=DIRECTION('',(1.,0.,0.));
#3212=AXIS2_PLACEMENT_3D('',#3209,#3210,#3211);
#3213=CIRCLE('',#3212,2.);
#3214=EDGE_CURVE('E1292',#3206,#3180,#3213,.F.);
#3215=ORIENTED_EDGE('',*,*,#3214,.T.);
#3216=EDGE_LOOP('',(#3184,#3192,#3198,#3199,#3200,#3208,#3215));
#3217=FACE_BOUND('',#3216,.T.);
#3218=ADVANCED_FACE('F2373',(#3217),#3174,.F.);
#3219=CARTESIAN_POINT('',(-82.,15.6591352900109,34.0694365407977));
#3220=DIRECTION('',(0.,-1.,0.));
#3221=DIRECTION('',(0.,0.,-1.));
#3222=AXIS2_PLACEMENT_3D('',#3219,#3220,#3221);
#3223=PLANE('',#3222);
#3224=ORIENTED_EDGE('',*,*,#3164,.F.);
#3225=DIRECTION('',(0.,0.,-1.));
#3226=VECTOR('',#3225,1.);
#3227=CARTESIAN_POINT('',(-85.3240417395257,15.6591352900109,34.0694365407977));
#3228=LINE('',#3227,#3226);
#3229=EDGE_CURVE('E1287',#3157,#3206,#3228,.T.);
#3230=ORIENTED_EDGE('',*,*,#3229,.T.);
#3231=ORIENTED_EDGE('',*,*,#3207,.T.);
#3232=ORIENTED_EDGE('',*,*,#177,.T.);
#3233=EDGE_LOOP('',(#3224,#3230,#3231,#3232));
#3234=FACE_BOUND('',#3233,.T.);
#3235=ADVANCED_FACE('F2384',(#3234),#3223,.F.);
#3236=CARTESIAN_POINT('',(-82.,3.,-85.8362318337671));
#3237=DIRECTION('',(-0.99254345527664,-0.121891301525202,0.));
#3238=DIRECTION('',(0.121891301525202,-0.992543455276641,0.));
#3239=AXIS2_PLACEMENT_3D('',#3236,#3237,#3238);
#3240=PLANE('',#3239);
#3241=ORIENTED_EDGE('',*,*,#3149,.T.);
#3242=DIRECTION('',(0.,0.,-1.));
#3243=VECTOR('',#3242,1.);
#3244=CARTESIAN_POINT('',(-82.14,4.14,-85.8362318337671));
#3245=LINE('',#3244,#3243);
#3246=EDGE_CURVE('E1361',#3140,#3182,#3245,.T.);
#3247=ORIENTED_EDGE('',*,*,#3246,.T.);
#3248=ORIENTED_EDGE('',*,*,#3183,.F.);
#3249=DIRECTION('',(0.,0.,-1.));
#3250=VECTOR('',#3249,1.);
#3251=CARTESIAN_POINT('',(-83.3389548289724,13.902917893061,-85.8362318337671));
#3252=LINE('',#3251,#3250);
#3253=EDGE_CURVE('E1291',#3180,#3148,#3252,.F.);
#3254=ORIENTED_EDGE('',*,*,#3253,.T.);
#3255=EDGE_LOOP('',(#3241,#3247,#3248,#3254));
#3256=FACE_BOUND('',#3255,.T.);
#3257=ADVANCED_FACE('F2395',(#3256),#3240,.F.);
#3258=ORIENTED_EDGE('',*,*,#3065,.F.);
#3259=DIRECTION('',(0.,0.,-1.));
#3260=VECTOR('',#3259,1.);
#3261=CARTESIAN_POINT('',(-82.14,4.14,-85.8362318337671));
#3262=LINE('',#3261,#3260);
#3263=EDGE_CURVE('E1343',#3056,#3089,#3262,.T.);
#3264=ORIENTED_EDGE('',*,*,#3263,.T.);
#3265=ORIENTED_EDGE('',*,*,#3092,.T.);
#3266=DIRECTION('',(0.,0.,1.));
#3267=VECTOR('',#3266,1.);
#3268=CARTESIAN_POINT('',(-88.784324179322,58.2437826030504,-25.4080157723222));
#3269=LINE('',#3268,#3267);
#3270=EDGE_CURVE('E1296',#3091,#3064,#3269,.T.);
#3271=ORIENTED_EDGE('',*,*,#3270,.T.);
#3272=EDGE_LOOP('',(#3258,#3264,#3265,#3271));
#3273=FACE_BOUND('',#3272,.T.);
#3274=ADVANCED_FACE('F2401',(#3273),#3240,.F.);
#3275=ORIENTED_EDGE('',*,*,#2981,.F.);
#3276=DIRECTION('',(0.,0.,-1.));
#3277=VECTOR('',#3276,1.);
#3278=CARTESIAN_POINT('',(-82.14,4.14,-85.8362318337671));
#3279=LINE('',#3278,#3277);
#3280=EDGE_CURVE('E1360',#2972,#3007,#3279,.T.);
#3281=ORIENTED_EDGE('',*,*,#3280,.T.);
#3282=ORIENTED_EDGE('',*,*,#3008,.F.);
#3283=DIRECTION('',(0.,0.,1.));
#3284=VECTOR('',#3283,1.);
#3285=CARTESIAN_POINT('',(-88.784324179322,58.2437826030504,9.74685594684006));
#3286=LINE('',#3285,#3284);
#3287=EDGE_CURVE('E1313',#3005,#2980,#3286,.T.);
#3288=ORIENTED_EDGE('',*,*,#3287,.T.);
#3289=EDGE_LOOP('',(#3275,#3281,#3282,#3288));
#3290=FACE_BOUND('',#3289,.T.);
#3291=ADVANCED_FACE('F2406',(#3290),#3240,.F.);
#3292=CARTESIAN_POINT('',(76.2703566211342,6.00000000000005,55.5833883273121));
#3293=DIRECTION('',(0.,-1.,0.));
#3294=DIRECTION('',(0.,0.,-1.));
#3295=AXIS2_PLACEMENT_3D('',#3292,#3293,#3294);
#3296=CONICAL_SURFACE('',#3295,4.99999999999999,0.785398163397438);
#3297=ORIENTED_EDGE('',*,*,#343,.F.);
#3298=EDGE_LOOP('',(#3297));
#3299=FACE_BOUND('',#3298,.T.);
#3300=ORIENTED_EDGE('',*,*,#1871,.F.);
#3301=EDGE_LOOP('',(#3300));
#3302=FACE_BOUND('',#3301,.T.);
#3303=ADVANCED_FACE('F2421',(#3299,#3302),#3296,.T.);
#3304=CARTESIAN_POINT('',(1.27035662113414,6.00000000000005,55.5833883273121));
#3305=DIRECTION('',(0.,-1.,0.));
#3306=DIRECTION('',(0.,0.,-1.));
#3307=AXIS2_PLACEMENT_3D('',#3304,#3305,#3306);
#3308=CONICAL_SURFACE('',#3307,4.99999999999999,0.785398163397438);
#3309=ORIENTED_EDGE('',*,*,#354,.F.);
#3310=EDGE_LOOP('',(#3309));
#3311=FACE_BOUND('',#3310,.T.);
#3312=ORIENTED_EDGE('',*,*,#1943,.F.);
#3313=EDGE_LOOP('',(#3312));
#3314=FACE_BOUND('',#3313,.T.);
#3315=ADVANCED_FACE('F2435',(#3311,#3314),#3308,.T.);
#3316=CARTESIAN_POINT('',(76.2703566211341,6.00000000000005,-54.4166116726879));
#3317=DIRECTION('',(0.,-1.,0.));
#3318=DIRECTION('',(0.,0.,-1.));
#3319=AXIS2_PLACEMENT_3D('',#3316,#3317,#3318);
#3320=CONICAL_SURFACE('',#3319,4.99999999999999,0.785398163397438);
#3321=ORIENTED_EDGE('',*,*,#365,.F.);
#3322=EDGE_LOOP('',(#3321));
#3323=FACE_BOUND('',#3322,.T.);
#3324=ORIENTED_EDGE('',*,*,#1799,.F.);
#3325=EDGE_LOOP('',(#3324));
#3326=FACE_BOUND('',#3325,.T.);
#3327=ADVANCED_FACE('F2442',(#3323,#3326),#3320,.T.);
#3328=CARTESIAN_POINT('',(38.7703566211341,6.00000000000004,-6.41661167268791));
#3329=DIRECTION('',(0.,-1.,0.));
#3330=DIRECTION('',(0.,0.,-1.));
#3331=AXIS2_PLACEMENT_3D('',#3328,#3329,#3330);
#3332=CONICAL_SURFACE('',#3331,5.,0.785398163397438);
#3333=ORIENTED_EDGE('',*,*,#376,.F.);
#3334=EDGE_LOOP('',(#3333));
#3335=FACE_BOUND('',#3334,.T.);
#3336=ORIENTED_EDGE('',*,*,#1655,.F.);
#3337=EDGE_LOOP('',(#3336));
#3338=FACE_BOUND('',#3337,.T.);
#3339=ADVANCED_FACE('F2453',(#3335,#3338),#3332,.T.);
#3340=CARTESIAN_POINT('',(1.27035662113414,6.00000000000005,-54.4166116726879));
#3341=DIRECTION('',(0.,-1.,0.));
#3342=DIRECTION('',(0.,0.,-1.));
#3343=AXIS2_PLACEMENT_3D('',#3340,#3341,#3342);
#3344=CONICAL_SURFACE('',#3343,4.99999999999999,0.785398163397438);
#3345=ORIENTED_EDGE('',*,*,#387,.F.);
#3346=EDGE_LOOP('',(#3345));
#3347=FACE_BOUND('',#3346,.T.);
#3348=ORIENTED_EDGE('',*,*,#1727,.F.);
#3349=EDGE_LOOP('',(#3348));
#3350=FACE_BOUND('',#3349,.T.);
#3351=ADVANCED_FACE('F2463',(#3347,#3350),#3344,.T.);
#3352=CARTESIAN_POINT('',(-85.3240417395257,13.6591352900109,34.0694365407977));
#3353=DIRECTION('',(0.,0.,-1.));
#3354=DIRECTION('',(0.,1.,0.));
#3355=AXIS2_PLACEMENT_3D('',#3352,#3353,#3354);
#3356=CYLINDRICAL_SURFACE('',#3355,2.);
#3357=ORIENTED_EDGE('',*,*,#3158,.F.);
#3358=ORIENTED_EDGE('',*,*,#3253,.F.);
#3359=ORIENTED_EDGE('',*,*,#3214,.F.);
#3360=ORIENTED_EDGE('',*,*,#3229,.F.);
#3361=EDGE_LOOP('',(#3357,#3358,#3359,#3360));
#3362=FACE_BOUND('',#3361,.T.);
#3363=ADVANCED_FACE('F2474',(#3362),#3356,.T.);
#3364=CARTESIAN_POINT('',(-90.7694110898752,58.,-85.8362318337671));
#3365=DIRECTION('',(0.,0.,-1.));
#3366=DIRECTION('',(-1.,0.,0.));
#3367=AXIS2_PLACEMENT_3D('',#3364,#3365,#3366);
#3368=CYLINDRICAL_SURFACE('',#3367,2.);
#3369=ORIENTED_EDGE('',*,*,#3116,.F.);
#3370=ORIENTED_EDGE('',*,*,#54,.F.);
#3371=ORIENTED_EDGE('',*,*,#3072,.F.);
#3372=ORIENTED_EDGE('',*,*,#3270,.F.);
#3373=EDGE_LOOP('',(#3369,#3370,#3371,#3372));
#3374=FACE_BOUND('',#3373,.T.);
#3375=ADVANCED_FACE('F2485',(#3374),#3368,.T.);
#3376=CARTESIAN_POINT('',(-90.7694110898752,58.,-85.8362318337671));
#3377=DIRECTION('',(0.,0.,-1.));
#3378=DIRECTION('',(-1.,0.,0.));
#3379=AXIS2_PLACEMENT_3D('',#3376,#3377,#3378);
#3380=CYLINDRICAL_SURFACE('',#3379,2.);
#3381=ORIENTED_EDGE('',*,*,#3032,.F.);
#3382=ORIENTED_EDGE('',*,*,#85,.F.);
#3383=ORIENTED_EDGE('',*,*,#2988,.F.);
#3384=ORIENTED_EDGE('',*,*,#3287,.F.);
#3385=EDGE_LOOP('',(#3381,#3382,#3383,#3384));
#3386=FACE_BOUND('',#3385,.T.);
#3387=ADVANCED_FACE('F2494',(#3386),#3380,.T.);
#3388=CARTESIAN_POINT('',(0.,61.5,0.));
#3389=DIRECTION('',(0.,-1.,0.));
#3390=DIRECTION('',(0.,0.,-1.));
#3391=AXIS2_PLACEMENT_3D('',#3388,#3389,#3390);
#3392=PLANE('',#3391);
#3393=DIRECTION('',(-0.707106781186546,0.,0.707106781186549));
#3394=VECTOR('',#3393,1.);
#3395=CARTESIAN_POINT('',(-93.5,61.5,-54.6213203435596));
#3396=LINE('',#3395,#3394);
#3397=CARTESIAN_POINT('',(-79.6213203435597,61.5,-68.5));
#3398=VERTEX_POINT('',#3397);
#3399=CARTESIAN_POINT('',(-93.5,61.5,-54.6213203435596));
#3400=VERTEX_POINT('',#3399);
#3401=EDGE_CURVE('E740',#3398,#3400,#3396,.T.);
#3402=ORIENTED_EDGE('',*,*,#3401,.T.);
#3403=DIRECTION('',(0.,0.,1.));
#3404=VECTOR('',#3403,1.);
#3405=CARTESIAN_POINT('',(-93.5,61.5,-54.6213203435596));
#3406=LINE('',#3405,#3404);
#3407=CARTESIAN_POINT('',(-93.5,61.5,54.6213203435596));
#3408=VERTEX_POINT('',#3407);
#3409=EDGE_CURVE('E743',#3400,#3408,#3406,.T.);
#3410=ORIENTED_EDGE('',*,*,#3409,.T.);
#3411=DIRECTION('',(0.707106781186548,0.,0.707106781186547));
#3412=VECTOR('',#3411,1.);
#3413=CARTESIAN_POINT('',(-79.6213203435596,61.5,68.5));
#3414=LINE('',#3413,#3412);
#3415=CARTESIAN_POINT('',(-79.6213203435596,61.5,68.5));
#3416=VERTEX_POINT('',#3415);
#3417=EDGE_CURVE('E745',#3408,#3416,#3414,.T.);
#3418=ORIENTED_EDGE('',*,*,#3417,.T.);
#3419=DIRECTION('',(1.,0.,0.));
#3420=VECTOR('',#3419,1.);
#3421=CARTESIAN_POINT('',(79.6213203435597,61.5,68.5));
#3422=LINE('',#3421,#3420);
#3423=CARTESIAN_POINT('',(79.6213203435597,61.5,68.5));
#3424=VERTEX_POINT('',#3423);
#3425=EDGE_CURVE('E747',#3416,#3424,#3422,.T.);
#3426=ORIENTED_EDGE('',*,*,#3425,.T.);
#3427=DIRECTION('',(0.707106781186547,0.,-0.707106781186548));
#3428=VECTOR('',#3427,1.);
#3429=CARTESIAN_POINT('',(93.5,61.5,54.6213203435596));
#3430=LINE('',#3429,#3428);
#3431=CARTESIAN_POINT('',(93.5,61.5,54.6213203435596));
#3432=VERTEX_POINT('',#3431);
#3433=EDGE_CURVE('E749',#3424,#3432,#3430,.T.);
#3434=ORIENTED_EDGE('',*,*,#3433,.T.);
#3435=DIRECTION('',(0.,0.,-1.));
#3436=VECTOR('',#3435,1.);
#3437=CARTESIAN_POINT('',(93.5,61.5,54.6213203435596));
#3438=LINE('',#3437,#3436);
#3439=CARTESIAN_POINT('',(93.5,61.5,-54.6213203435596));
#3440=VERTEX_POINT('',#3439);
#3441=EDGE_CURVE('E748',#3432,#3440,#3438,.T.);
#3442=ORIENTED_EDGE('',*,*,#3441,.T.);
#3443=DIRECTION('',(-0.707106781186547,0.,-0.707106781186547));
#3444=VECTOR('',#3443,1.);
#3445=CARTESIAN_POINT('',(79.6213203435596,61.5,-68.5));
#3446=LINE('',#3445,#3444);
#3447=CARTESIAN_POINT('',(79.6213203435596,61.5,-68.5));
#3448=VERTEX_POINT('',#3447);
#3449=EDGE_CURVE('E755',#3440,#3448,#3446,.T.);
#3450=ORIENTED_EDGE('',*,*,#3449,.T.);
#3451=DIRECTION('',(-1.,0.,0.));
#3452=VECTOR('',#3451,1.);
#3453=CARTESIAN_POINT('',(79.6213203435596,61.5,-68.5));
#3454=LINE('',#3453,#3452);
#3455=EDGE_CURVE('E754',#3448,#3398,#3454,.T.);
#3456=ORIENTED_EDGE('',*,*,#3455,.T.);
#3457=EDGE_LOOP('',(#3402,#3410,#3418,#3426,#3434,#3442,#3450,#3456));
#3458=FACE_BOUND('',#3457,.T.);
#3459=ORIENTED_EDGE('',*,*,#918,.F.);
#3460=ORIENTED_EDGE('',*,*,#2014,.F.);
#3461=ORIENTED_EDGE('',*,*,#698,.F.);
#3462=ORIENTED_EDGE('',*,*,#1992,.F.);
#3463=ORIENTED_EDGE('',*,*,#958,.F.);
#3464=ORIENTED_EDGE('',*,*,#2058,.F.);
#3465=ORIENTED_EDGE('',*,*,#145,.F.);
#3466=ORIENTED_EDGE('',*,*,#2036,.F.);
#3467=EDGE_LOOP('',(#3459,#3460,#3461,#3462,#3463,#3464,#3465,#3466));
#3468=FACE_BOUND('',#3467,.T.);
#3469=ADVANCED_FACE('F715',(#3458,#3468),#3392,.F.);
#3470=CARTESIAN_POINT('',(-93.5,61.5,-54.6213203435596));
#3471=DIRECTION('',(0.707106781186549,0.,0.707106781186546));
#3472=DIRECTION('',(0.707106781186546,0.,-0.707106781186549));
#3473=AXIS2_PLACEMENT_3D('',#3470,#3471,#3472);
#3474=PLANE('',#3473);
#3475=ORIENTED_EDGE('',*,*,#1296,.T.);
#3476=DIRECTION('',(0.,-1.,0.));
#3477=VECTOR('',#3476,1.);
#3478=CARTESIAN_POINT('',(-93.5,61.5,-54.6213203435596));
#3479=LINE('',#3478,#3477);
#3480=EDGE_CURVE('E797',#3400,#1295,#3479,.T.);
#3481=ORIENTED_EDGE('',*,*,#3480,.F.);
#3482=ORIENTED_EDGE('',*,*,#3401,.F.);
#3483=DIRECTION('',(0.,-1.,0.));
#3484=VECTOR('',#3483,1.);
#3485=CARTESIAN_POINT('',(-79.6213203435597,61.5,-68.5));
#3486=LINE('',#3485,#3484);
#3487=EDGE_CURVE('E757',#3398,#1293,#3486,.T.);
#3488=ORIENTED_EDGE('',*,*,#3487,.T.);
#3489=EDGE_LOOP('',(#3475,#3481,#3482,#3488));
#3490=FACE_BOUND('',#3489,.T.);
#3491=ADVANCED_FACE('F2553',(#3490),#3474,.F.);
#3492=CARTESIAN_POINT('',(-93.5,61.5,-54.6213203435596));
#3493=DIRECTION('',(1.,0.,0.));
#3494=DIRECTION('',(0.,0.,-1.));
#3495=AXIS2_PLACEMENT_3D('',#3492,#3493,#3494);
#3496=PLANE('',#3495);
#3497=ORIENTED_EDGE('',*,*,#1350,.T.);
#3498=DIRECTION('',(0.,-1.,0.));
#3499=VECTOR('',#3498,1.);
#3500=CARTESIAN_POINT('',(-93.5,61.5,54.6213203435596));
#3501=LINE('',#3500,#3499);
#3502=EDGE_CURVE('E796',#3408,#1343,#3501,.T.);
#3503=ORIENTED_EDGE('',*,*,#3502,.F.);
#3504=ORIENTED_EDGE('',*,*,#3409,.F.);
#3505=ORIENTED_EDGE('',*,*,#3480,.T.);
#3506=EDGE_LOOP('',(#3497,#3503,#3504,#3505));
#3507=FACE_BOUND('',#3506,.T.);
#3508=ADVANCED_FACE('F2565',(#3507),#3496,.F.);
#3509=CARTESIAN_POINT('',(-79.6213203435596,61.5,68.5));
#3510=DIRECTION('',(0.707106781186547,0.,-0.707106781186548));
#3511=DIRECTION('',(-0.707106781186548,0.,-0.707106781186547));
#3512=AXIS2_PLACEMENT_3D('',#3509,#3510,#3511);
#3513=PLANE('',#3512);
#3514=ORIENTED_EDGE('',*,*,#1344,.T.);
#3515=DIRECTION('',(0.,-1.,0.));
#3516=VECTOR('',#3515,1.);
#3517=CARTESIAN_POINT('',(-79.6213203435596,61.5,68.5));
#3518=LINE('',#3517,#3516);
#3519=EDGE_CURVE('E793',#3416,#1335,#3518,.T.);
#3520=ORIENTED_EDGE('',*,*,#3519,.F.);
#3521=ORIENTED_EDGE('',*,*,#3417,.F.);
#3522=ORIENTED_EDGE('',*,*,#3502,.T.);
#3523=EDGE_LOOP('',(#3514,#3520,#3521,#3522));
#3524=FACE_BOUND('',#3523,.T.);
#3525=ADVANCED_FACE('F2575',(#3524),#3513,.F.);
#3526=CARTESIAN_POINT('',(79.6213203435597,61.5,68.5));
#3527=DIRECTION('',(0.,0.,-1.));
#3528=DIRECTION('',(-1.,0.,0.));
#3529=AXIS2_PLACEMENT_3D('',#3526,#3527,#3528);
#3530=PLANE('',#3529);
#3531=ORIENTED_EDGE('',*,*,#1336,.T.);
#3532=DIRECTION('',(0.,-1.,0.));
#3533=VECTOR('',#3532,1.);
#3534=CARTESIAN_POINT('',(79.6213203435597,61.5,68.5));
#3535=LINE('',#3534,#3533);
#3536=EDGE_CURVE('E787',#3424,#1327,#3535,.T.);
#3537=ORIENTED_EDGE('',*,*,#3536,.F.);
#3538=ORIENTED_EDGE('',*,*,#3425,.F.);
#3539=ORIENTED_EDGE('',*,*,#3519,.T.);
#3540=EDGE_LOOP('',(#3531,#3537,#3538,#3539));
#3541=FACE_BOUND('',#3540,.T.);
#3542=ADVANCED_FACE('F2583',(#3541),#3530,.F.);
#3543=CARTESIAN_POINT('',(93.5,61.5,54.6213203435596));
#3544=DIRECTION('',(-0.707106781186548,0.,-0.707106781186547));
#3545=DIRECTION('',(-0.707106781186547,0.,0.707106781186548));
#3546=AXIS2_PLACEMENT_3D('',#3543,#3544,#3545);
#3547=PLANE('',#3546);
#3548=ORIENTED_EDGE('',*,*,#1328,.T.);
#3549=DIRECTION('',(0.,-1.,0.));
#3550=VECTOR('',#3549,1.);
#3551=CARTESIAN_POINT('',(93.5,61.5,54.6213203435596));
#3552=LINE('',#3551,#3550);
#3553=EDGE_CURVE('E790',#3432,#1319,#3552,.T.);
#3554=ORIENTED_EDGE('',*,*,#3553,.F.);
#3555=ORIENTED_EDGE('',*,*,#3433,.F.);
#3556=ORIENTED_EDGE('',*,*,#3536,.T.);
#3557=EDGE_LOOP('',(#3548,#3554,#3555,#3556));
#3558=FACE_BOUND('',#3557,.T.);
#3559=ADVANCED_FACE('F2587',(#3558),#3547,.F.);
#3560=CARTESIAN_POINT('',(93.5,61.5,54.6213203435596));
#3561=DIRECTION('',(-1.,0.,0.));
#3562=DIRECTION('',(0.,0.,1.));
#3563=AXIS2_PLACEMENT_3D('',#3560,#3561,#3562);
#3564=PLANE('',#3563);
#3565=ORIENTED_EDGE('',*,*,#1320,.T.);
#3566=DIRECTION('',(0.,-1.,0.));
#3567=VECTOR('',#3566,1.);
#3568=CARTESIAN_POINT('',(93.5,61.5,-54.6213203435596));
#3569=LINE('',#3568,#3567);
#3570=EDGE_CURVE('E785',#3440,#1311,#3569,.T.);
#3571=ORIENTED_EDGE('',*,*,#3570,.F.);
#3572=ORIENTED_EDGE('',*,*,#3441,.F.);
#3573=ORIENTED_EDGE('',*,*,#3553,.T.);
#3574=EDGE_LOOP('',(#3565,#3571,#3572,#3573));
#3575=FACE_BOUND('',#3574,.T.);
#3576=ADVANCED_FACE('F2597',(#3575),#3564,.F.);
#3577=CARTESIAN_POINT('',(79.6213203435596,61.5,-68.5));
#3578=DIRECTION('',(-0.707106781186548,0.,0.707106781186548));
#3579=DIRECTION('',(0.707106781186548,0.,0.707106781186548));
#3580=AXIS2_PLACEMENT_3D('',#3577,#3578,#3579);
#3581=PLANE('',#3580);
#3582=ORIENTED_EDGE('',*,*,#1312,.T.);
#3583=DIRECTION('',(0.,-1.,0.));
#3584=VECTOR('',#3583,1.);
#3585=CARTESIAN_POINT('',(79.6213203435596,61.5,-68.5));
#3586=LINE('',#3585,#3584);
#3587=EDGE_CURVE('E783',#3448,#1303,#3586,.T.);
#3588=ORIENTED_EDGE('',*,*,#3587,.F.);
#3589=ORIENTED_EDGE('',*,*,#3449,.F.);
#3590=ORIENTED_EDGE('',*,*,#3570,.T.);
#3591=EDGE_LOOP('',(#3582,#3588,#3589,#3590));
#3592=FACE_BOUND('',#3591,.T.);
#3593=ADVANCED_FACE('F2609',(#3592),#3581,.F.);
#3594=CARTESIAN_POINT('',(79.6213203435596,61.5,-68.5));
#3595=DIRECTION('',(0.,0.,1.));
#3596=DIRECTION('',(1.,0.,0.));
#3597=AXIS2_PLACEMENT_3D('',#3594,#3595,#3596);
#3598=PLANE('',#3597);
#3599=ORIENTED_EDGE('',*,*,#1304,.T.);
#3600=ORIENTED_EDGE('',*,*,#3487,.F.);
#3601=ORIENTED_EDGE('',*,*,#3455,.F.);
#3602=ORIENTED_EDGE('',*,*,#3587,.T.);
#3603=EDGE_LOOP('',(#3599,#3600,#3601,#3602));
#3604=FACE_BOUND('',#3603,.T.);
#3605=ADVANCED_FACE('F2619',(#3604),#3598,.F.);
#3606=CARTESIAN_POINT('',(0.,3.,-24.4080157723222));
#3607=DIRECTION('',(0.,-0.707106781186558,-0.707106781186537));
#3608=DIRECTION('',(-1.,0.,0.));
#3609=AXIS2_PLACEMENT_3D('',#3606,#3607,#3608);
#3610=PLANE('',#3609);
#3611=ORIENTED_EDGE('',*,*,#612,.F.);
#3612=ORIENTED_EDGE('',*,*,#423,.F.);
#3613=DIRECTION('',(-0.57735026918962,0.57735026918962,-0.577350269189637));
#3614=VECTOR('',#3613,1.);
#3615=CARTESIAN_POINT('',(-54.0000000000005,-23.9999999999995,2.59198422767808));
#3616=LINE('',#3615,#3614);
#3617=EDGE_CURVE('E709',#3048,#414,#3616,.F.);
#3618=ORIENTED_EDGE('',*,*,#3617,.F.);
#3619=ORIENTED_EDGE('',*,*,#3049,.F.);
#3620=EDGE_LOOP('',(#3611,#3612,#3618,#3619));
#3621=FACE_BOUND('',#3620,.T.);
#3622=ADVANCED_FACE('F2623',(#3621),#3610,.F.);
#3623=CARTESIAN_POINT('',(-82.14,4.14,-85.8362318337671));
#3624=DIRECTION('',(-0.707106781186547,-0.707106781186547,0.));
#3625=DIRECTION('',(0.,0.,-1.));
#3626=AXIS2_PLACEMENT_3D('',#3623,#3624,#3625);
#3627=PLANE('',#3626);
#3628=ORIENTED_EDGE('',*,*,#3617,.T.);
#3629=ORIENTED_EDGE('',*,*,#415,.F.);
#3630=DIRECTION('',(-0.577350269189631,0.577350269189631,0.577350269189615));
#3631=VECTOR('',#3630,1.);
#3632=CARTESIAN_POINT('',(-62.9505946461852,-15.0494053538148,-47.4574211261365));
#3633=LINE('',#3632,#3631);
#3634=EDGE_CURVE('E1385',#3099,#406,#3633,.F.);
#3635=ORIENTED_EDGE('',*,*,#3634,.F.);
#3636=ORIENTED_EDGE('',*,*,#3100,.F.);
#3637=ORIENTED_EDGE('',*,*,#3263,.F.);
#3638=ORIENTED_EDGE('',*,*,#3057,.F.);
#3639=EDGE_LOOP('',(#3628,#3629,#3635,#3636,#3637,#3638));
#3640=FACE_BOUND('',#3639,.T.);
#3641=ADVANCED_FACE('F2631',(#3640),#3627,.F.);
#3642=CARTESIAN_POINT('',(-82.,4.00000000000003,-28.4080157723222));
#3643=DIRECTION('',(0.,-0.707106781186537,0.707106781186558));
#3644=DIRECTION('',(-1.,0.,0.));
#3645=AXIS2_PLACEMENT_3D('',#3642,#3643,#3644);
#3646=PLANE('',#3645);
#3647=ORIENTED_EDGE('',*,*,#3634,.T.);
#3648=ORIENTED_EDGE('',*,*,#407,.F.);
#3649=ORIENTED_EDGE('',*,*,#650,.F.);
#3650=ORIENTED_EDGE('',*,*,#3106,.F.);
#3651=EDGE_LOOP('',(#3647,#3648,#3649,#3650));
#3652=FACE_BOUND('',#3651,.T.);
#3653=ADVANCED_FACE('F2644',(#3652),#3646,.F.);
#3654=CARTESIAN_POINT('',(-82.,4.00000000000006,6.74685594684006));
#3655=DIRECTION('',(0.,-0.707106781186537,0.707106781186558));
#3656=DIRECTION('',(-1.,0.,0.));
#3657=AXIS2_PLACEMENT_3D('',#3654,#3655,#3656);
#3658=PLANE('',#3657);
#3659=ORIENTED_EDGE('',*,*,#3022,.F.);
#3660=DIRECTION('',(-0.577350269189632,0.577350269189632,0.577350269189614));
#3661=VECTOR('',#3660,1.);
#3662=CARTESIAN_POINT('',(-51.2323040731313,-26.7676959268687,-24.0208399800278));
#3663=LINE('',#3662,#3661);
#3664=EDGE_CURVE('E1390',#434,#3015,#3663,.T.);
#3665=ORIENTED_EDGE('',*,*,#3664,.F.);
#3666=ORIENTED_EDGE('',*,*,#435,.F.);
#3667=ORIENTED_EDGE('',*,*,#633,.F.);
#3668=EDGE_LOOP('',(#3659,#3665,#3666,#3667));
#3669=FACE_BOUND('',#3668,.T.);
#3670=ADVANCED_FACE('F2652',(#3669),#3658,.F.);
#3671=CARTESIAN_POINT('',(-82.14,4.14,-85.8362318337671));
#3672=DIRECTION('',(-0.707106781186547,-0.707106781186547,0.));
#3673=DIRECTION('',(0.,0.,-1.));
#3674=AXIS2_PLACEMENT_3D('',#3671,#3672,#3673);
#3675=PLANE('',#3674);
#3676=ORIENTED_EDGE('',*,*,#3280,.F.);
#3677=ORIENTED_EDGE('',*,*,#2973,.F.);
#3678=DIRECTION('',(0.577350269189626,-0.577350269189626,0.577350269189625));
#3679=VECTOR('',#3678,1.);
#3680=CARTESIAN_POINT('',(-113.954362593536,35.9543625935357,-22.2075066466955));
#3681=LINE('',#3680,#3679);
#3682=EDGE_CURVE('E1387',#442,#2964,#3681,.F.);
#3683=ORIENTED_EDGE('',*,*,#3682,.F.);
#3684=ORIENTED_EDGE('',*,*,#443,.F.);
#3685=ORIENTED_EDGE('',*,*,#3664,.T.);
#3686=ORIENTED_EDGE('',*,*,#3016,.F.);
#3687=EDGE_LOOP('',(#3676,#3677,#3683,#3684,#3685,#3686));
#3688=FACE_BOUND('',#3687,.T.);
#3689=ADVANCED_FACE('F2659',(#3688),#3675,.F.);
#3690=CARTESIAN_POINT('',(0.,3.,10.7468559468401));
#3691=DIRECTION('',(0.,-0.707106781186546,-0.707106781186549));
#3692=DIRECTION('',(-1.,0.,0.));
#3693=AXIS2_PLACEMENT_3D('',#3690,#3691,#3692);
#3694=PLANE('',#3693);
#3695=ORIENTED_EDGE('',*,*,#3682,.T.);
#3696=ORIENTED_EDGE('',*,*,#2965,.F.);
#3697=ORIENTED_EDGE('',*,*,#579,.F.);
#3698=ORIENTED_EDGE('',*,*,#451,.F.);
#3699=EDGE_LOOP('',(#3695,#3696,#3697,#3698));
#3700=FACE_BOUND('',#3699,.T.);
#3701=ADVANCED_FACE('F2667',(#3700),#3694,.F.);
#3702=CARTESIAN_POINT('',(0.,3.,35.0694365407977));
#3703=DIRECTION('',(0.,-0.707106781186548,-0.707106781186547));
#3704=DIRECTION('',(-1.,0.,0.));
#3705=AXIS2_PLACEMENT_3D('',#3702,#3703,#3704);
#3706=PLANE('',#3705);
#3707=ORIENTED_EDGE('',*,*,#554,.F.);
#3708=ORIENTED_EDGE('',*,*,#479,.F.);
#3709=DIRECTION('',(-0.577350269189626,0.577350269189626,-0.577350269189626));
#3710=VECTOR('',#3709,1.);
#3711=CARTESIAN_POINT('',(-54.,-24.,62.0694365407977));
#3712=LINE('',#3711,#3710);
#3713=EDGE_CURVE('E1393',#3132,#470,#3712,.F.);
#3714=ORIENTED_EDGE('',*,*,#3713,.F.);
#3715=ORIENTED_EDGE('',*,*,#3133,.F.);
#3716=EDGE_LOOP('',(#3707,#3708,#3714,#3715));
#3717=FACE_BOUND('',#3716,.T.);
#3718=ADVANCED_FACE('F2677',(#3717),#3706,.F.);
#3719=CARTESIAN_POINT('',(-82.14,4.14,-85.8362318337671));
#3720=DIRECTION('',(-0.707106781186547,-0.707106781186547,0.));
#3721=DIRECTION('',(0.,0.,-1.));
#3722=AXIS2_PLACEMENT_3D('',#3719,#3720,#3721);
#3723=PLANE('',#3722);
#3724=ORIENTED_EDGE('',*,*,#3713,.T.);
#3725=ORIENTED_EDGE('',*,*,#471,.F.);
#3726=DIRECTION('',(-0.577350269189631,0.577350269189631,0.577350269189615));
#3727=VECTOR('',#3726,1.);
#3728=CARTESIAN_POINT('',(-43.1247772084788,-34.8752227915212,-7.80578625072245));
#3729=LINE('',#3728,#3727);
#3730=EDGE_CURVE('E1396',#3190,#462,#3729,.F.);
#3731=ORIENTED_EDGE('',*,*,#3730,.F.);
#3732=ORIENTED_EDGE('',*,*,#3191,.F.);
#3733=ORIENTED_EDGE('',*,*,#3246,.F.);
#3734=ORIENTED_EDGE('',*,*,#3141,.F.);
#3735=EDGE_LOOP('',(#3724,#3725,#3731,#3732,#3733,#3734));
#3736=FACE_BOUND('',#3735,.T.);
#3737=ADVANCED_FACE('F2686',(#3736),#3723,.F.);
#3738=CARTESIAN_POINT('',(-82.,4.00000000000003,31.0694365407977));
#3739=DIRECTION('',(0.,-0.707106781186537,0.707106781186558));
#3740=DIRECTION('',(-1.,0.,0.));
#3741=AXIS2_PLACEMENT_3D('',#3738,#3739,#3740);
#3742=PLANE('',#3741);
#3743=ORIENTED_EDGE('',*,*,#3730,.T.);
#3744=ORIENTED_EDGE('',*,*,#463,.F.);
#3745=ORIENTED_EDGE('',*,*,#600,.F.);
#3746=ORIENTED_EDGE('',*,*,#3197,.F.);
#3747=EDGE_LOOP('',(#3743,#3744,#3745,#3746));
#3748=FACE_BOUND('',#3747,.T.);
#3749=ADVANCED_FACE('F2697',(#3748),#3742,.F.);
#3750=CARTESIAN_POINT('',(95.,60.,-3.01686635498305));
#3751=DIRECTION('',(0.707106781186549,0.,0.707106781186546));
#3752=DIRECTION('',(0.,1.,0.));
#3753=AXIS2_PLACEMENT_3D('',#3750,#3751,#3752);
#3754=PLANE('',#3753);
#3755=DIRECTION('',(0.707106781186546,0.,-0.707106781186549));
#3756=VECTOR('',#3755,1.);
#3757=CARTESIAN_POINT('',(94.,33.,-2.01686635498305));
#3758=LINE('',#3757,#3756);
#3759=EDGE_CURVE('E1455',#2451,#820,#3758,.T.);
#3760=ORIENTED_EDGE('',*,*,#3759,.F.);
#3761=ORIENTED_EDGE('',*,*,#2483,.F.);
#3762=DIRECTION('',(-0.707106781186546,0.,0.707106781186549));
#3763=VECTOR('',#3762,1.);
#3764=CARTESIAN_POINT('',(95.,26.,-3.01686635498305));
#3765=LINE('',#3764,#3763);
#3766=EDGE_CURVE('E1397',#828,#2476,#3765,.T.);
#3767=ORIENTED_EDGE('',*,*,#3766,.F.);
#3768=ORIENTED_EDGE('',*,*,#829,.F.);
#3769=EDGE_LOOP('',(#3760,#3761,#3767,#3768));
#3770=FACE_BOUND('',#3769,.T.);
#3771=ADVANCED_FACE('F2704',(#3770),#3754,.T.);
#3772=CARTESIAN_POINT('',(95.,26.,-0.0168663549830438));
#3773=DIRECTION('',(1.,0.,0.));
#3774=DIRECTION('',(0.,0.,-1.));
#3775=AXIS2_PLACEMENT_3D('',#3772,#3773,#3774);
#3776=CONICAL_SURFACE('',#3775,3.,0.785398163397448);
#3777=ORIENTED_EDGE('',*,*,#3766,.T.);
#3778=ORIENTED_EDGE('',*,*,#2508,.F.);
#3779=DIRECTION('',(-0.707106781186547,0.707106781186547,0.));
#3780=VECTOR('',#3779,1.);
#3781=CARTESIAN_POINT('',(95.,23.,-0.0168663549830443));
#3782=LINE('',#3781,#3780);
#3783=EDGE_CURVE('E1446',#837,#2500,#3782,.T.);
#3784=ORIENTED_EDGE('',*,*,#3783,.F.);
#3785=ORIENTED_EDGE('',*,*,#838,.F.);
#3786=EDGE_LOOP('',(#3777,#3778,#3784,#3785));
#3787=FACE_BOUND('',#3786,.T.);
#3788=ADVANCED_FACE('F2711',(#3787),#3776,.F.);
#3789=CARTESIAN_POINT('',(95.,33.,-0.0168663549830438));
#3790=DIRECTION('',(1.,0.,0.));
#3791=DIRECTION('',(0.,0.,-1.));
#3792=AXIS2_PLACEMENT_3D('',#3789,#3790,#3791);
#3793=CONICAL_SURFACE('',#3792,3.,0.785398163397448);
#3794=ORIENTED_EDGE('',*,*,#3759,.T.);
#3795=ORIENTED_EDGE('',*,*,#821,.F.);
#3796=DIRECTION('',(0.707106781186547,0.707106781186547,0.));
#3797=VECTOR('',#3796,1.);
#3798=CARTESIAN_POINT('',(94.,35.,-0.0168663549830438));
#3799=LINE('',#3798,#3797);
#3800=EDGE_CURVE('E1447',#2427,#811,#3799,.T.);
#3801=ORIENTED_EDGE('',*,*,#3800,.F.);
#3802=ORIENTED_EDGE('',*,*,#2459,.F.);
#3803=EDGE_LOOP('',(#3794,#3795,#3801,#3802));
#3804=FACE_BOUND('',#3803,.T.);
#3805=ADVANCED_FACE('F2716',(#3804),#3793,.F.);
#3806=CARTESIAN_POINT('',(95.,23.,-70.));
#3807=DIRECTION('',(0.707106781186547,0.707106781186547,0.));
#3808=DIRECTION('',(0.,0.,-1.));
#3809=AXIS2_PLACEMENT_3D('',#3806,#3807,#3808);
#3810=PLANE('',#3809);
#3811=ORIENTED_EDGE('',*,*,#3783,.T.);
#3812=ORIENTED_EDGE('',*,*,#2532,.F.);
#3813=DIRECTION('',(-0.707106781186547,0.707106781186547,0.));
#3814=VECTOR('',#3813,1.);
#3815=CARTESIAN_POINT('',(95.,23.,15.9831336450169));
#3816=LINE('',#3815,#3814);
#3817=EDGE_CURVE('E1442',#784,#2525,#3816,.T.);
#3818=ORIENTED_EDGE('',*,*,#3817,.F.);
#3819=ORIENTED_EDGE('',*,*,#844,.F.);
#3820=EDGE_LOOP('',(#3811,#3812,#3818,#3819));
#3821=FACE_BOUND('',#3820,.T.);
#3822=ADVANCED_FACE('F2729',(#3821),#3810,.T.);
#3823=CARTESIAN_POINT('',(95.,36.,-70.));
#3824=DIRECTION('',(0.707106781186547,-0.707106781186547,0.));
#3825=DIRECTION('',(0.,0.,1.));
#3826=AXIS2_PLACEMENT_3D('',#3823,#3824,#3825);
#3827=PLANE('',#3826);
#3828=ORIENTED_EDGE('',*,*,#3800,.T.);
#3829=ORIENTED_EDGE('',*,*,#812,.F.);
#3830=DIRECTION('',(0.707106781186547,0.707106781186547,0.));
#3831=VECTOR('',#3830,1.);
#3832=CARTESIAN_POINT('',(94.,35.,15.9831336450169));
#3833=LINE('',#3832,#3831);
#3834=EDGE_CURVE('E1437',#2395,#803,#3833,.T.);
#3835=ORIENTED_EDGE('',*,*,#3834,.F.);
#3836=ORIENTED_EDGE('',*,*,#2434,.F.);
#3837=EDGE_LOOP('',(#3828,#3829,#3835,#3836));
#3838=FACE_BOUND('',#3837,.T.);
#3839=ADVANCED_FACE('F2736',(#3838),#3827,.T.);
#3840=CARTESIAN_POINT('',(95.,26.,15.9831336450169));
#3841=DIRECTION('',(1.,0.,0.));
#3842=DIRECTION('',(0.,0.,-1.));
#3843=AXIS2_PLACEMENT_3D('',#3840,#3841,#3842);
#3844=CONICAL_SURFACE('',#3843,3.00000000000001,0.785398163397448);
#3845=ORIENTED_EDGE('',*,*,#3817,.T.);
#3846=ORIENTED_EDGE('',*,*,#2557,.F.);
#3847=DIRECTION('',(-0.707106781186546,0.,-0.707106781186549));
#3848=VECTOR('',#3847,1.);
#3849=CARTESIAN_POINT('',(95.,26.,18.983133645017));
#3850=LINE('',#3849,#3848);
#3851=EDGE_CURVE('E1440',#786,#2549,#3850,.T.);
#3852=ORIENTED_EDGE('',*,*,#3851,.F.);
#3853=ORIENTED_EDGE('',*,*,#787,.F.);
#3854=EDGE_LOOP('',(#3845,#3846,#3852,#3853));
#3855=FACE_BOUND('',#3854,.T.);
#3856=ADVANCED_FACE('F2750',(#3855),#3844,.F.);
#3857=CARTESIAN_POINT('',(95.,33.,15.9831336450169));
#3858=DIRECTION('',(1.,0.,0.));
#3859=DIRECTION('',(0.,0.,-1.));
#3860=AXIS2_PLACEMENT_3D('',#3857,#3858,#3859);
#3861=CONICAL_SURFACE('',#3860,3.,0.785398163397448);
#3862=ORIENTED_EDGE('',*,*,#3834,.T.);
#3863=ORIENTED_EDGE('',*,*,#804,.F.);
#3864=DIRECTION('',(0.707106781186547,0.,0.707106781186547));
#3865=VECTOR('',#3864,1.);
#3866=CARTESIAN_POINT('',(94.,33.,17.9831336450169));
#3867=LINE('',#3866,#3865);
#3868=EDGE_CURVE('E1439',#2404,#794,#3867,.T.);
#3869=ORIENTED_EDGE('',*,*,#3868,.F.);
#3870=ORIENTED_EDGE('',*,*,#2405,.F.);
#3871=EDGE_LOOP('',(#3862,#3863,#3869,#3870));
#3872=FACE_BOUND('',#3871,.T.);
#3873=ADVANCED_FACE('F2757',(#3872),#3861,.F.);
#3874=CARTESIAN_POINT('',(95.,60.0000000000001,18.9831336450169));
#3875=DIRECTION('',(0.707106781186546,0.,-0.707106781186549));
#3876=DIRECTION('',(0.,-1.,0.));
#3877=AXIS2_PLACEMENT_3D('',#3874,#3875,#3876);
#3878=PLANE('',#3877);
#3879=ORIENTED_EDGE('',*,*,#3851,.T.);
#3880=ORIENTED_EDGE('',*,*,#2574,.F.);
#3881=ORIENTED_EDGE('',*,*,#3868,.T.);
#3882=ORIENTED_EDGE('',*,*,#795,.F.);
#3883=EDGE_LOOP('',(#3879,#3880,#3881,#3882));
#3884=FACE_BOUND('',#3883,.T.);
#3885=ADVANCED_FACE('F2762',(#3884),#3878,.T.);
#3886=CARTESIAN_POINT('',(-94.8,30.,-7.99999999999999));
#3887=DIRECTION('',(-1.,0.,0.));
#3888=DIRECTION('',(0.,0.,1.));
#3889=AXIS2_PLACEMENT_3D('',#3886,#3887,#3888);
#3890=CONICAL_SURFACE('',#3889,6.6,0.78539816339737);
#3891=ORIENTED_EDGE('',*,*,#2662,.F.);
#3892=ORIENTED_EDGE('',*,*,#1092,.F.);
#3893=ORIENTED_EDGE('',*,*,#2705,.F.);
#3894=ORIENTED_EDGE('',*,*,#2637,.F.);
#3895=EDGE_LOOP('',(#3891,#3892,#3893,#3894));
#3896=FACE_BOUND('',#3895,.T.);
#3897=ADVANCED_FACE('F1469',(#3896),#3890,.F.);
#3898=CARTESIAN_POINT('',(0.,60.,69.5));
#3899=DIRECTION('',(0.,0.707106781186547,0.707106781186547));
#3900=DIRECTION('',(-1.,0.,0.));
#3901=AXIS2_PLACEMENT_3D('',#3898,#3899,#3900);
#3902=PLANE('',#3901);
#3903=DIRECTION('',(0.,0.707106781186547,-0.707106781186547));
#3904=VECTOR('',#3903,1.);
#3905=CARTESIAN_POINT('',(-90.,59.5,70.));
#3906=LINE('',#3905,#3904);
#3907=EDGE_CURVE('E1546',#1198,#1260,#3906,.T.);
#3908=ORIENTED_EDGE('',*,*,#3907,.F.);
#3909=ORIENTED_EDGE('',*,*,#1199,.F.);
#3910=DIRECTION('',(0.,-0.707106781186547,0.707106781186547));
#3911=VECTOR('',#3910,1.);
#3912=CARTESIAN_POINT('',(90.,60.,69.5));
#3913=LINE('',#3912,#3911);
#3914=EDGE_CURVE('E166',#1268,#1190,#3913,.T.);
#3915=ORIENTED_EDGE('',*,*,#3914,.F.);
#3916=ORIENTED_EDGE('',*,*,#1269,.F.);
#3917=EDGE_LOOP('',(#3908,#3909,#3915,#3916));
#3918=FACE_BOUND('',#3917,.T.);
#3919=ADVANCED_FACE('F167',(#3918),#3902,.T.);
#3920=CARTESIAN_POINT('',(90.,60.,65.));
#3921=DIRECTION('',(0.,-1.,0.));
#3922=DIRECTION('',(0.,0.,-1.));
#3923=AXIS2_PLACEMENT_3D('',#3920,#3921,#3922);
#3924=CONICAL_SURFACE('',#3923,4.5,0.785398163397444);
#3925=ORIENTED_EDGE('',*,*,#3914,.T.);
#3926=ORIENTED_EDGE('',*,*,#1602,.F.);
#3927=DIRECTION('',(0.707106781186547,-0.707106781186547,0.));
#3928=VECTOR('',#3927,1.);
#3929=CARTESIAN_POINT('',(94.5,60.,65.));
#3930=LINE('',#3929,#3928);
#3931=EDGE_CURVE('E1542',#1277,#863,#3930,.T.);
#3932=ORIENTED_EDGE('',*,*,#3931,.F.);
#3933=ORIENTED_EDGE('',*,*,#1278,.F.);
#3934=EDGE_LOOP('',(#3925,#3926,#3932,#3933));
#3935=FACE_BOUND('',#3934,.T.);
#3936=ADVANCED_FACE('F1557',(#3935),#3924,.T.);
#3937=CARTESIAN_POINT('',(-90.,60.,65.));
#3938=DIRECTION('',(0.,-1.,0.));
#3939=DIRECTION('',(0.,0.,-1.));
#3940=AXIS2_PLACEMENT_3D('',#3937,#3938,#3939);
#3941=CONICAL_SURFACE('',#3940,4.5,0.785398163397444);
#3942=ORIENTED_EDGE('',*,*,#3907,.T.);
#3943=ORIENTED_EDGE('',*,*,#1261,.F.);
#3944=DIRECTION('',(0.707106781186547,0.707106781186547,0.));
#3945=VECTOR('',#3944,1.);
#3946=CARTESIAN_POINT('',(-95.,59.5,65.));
#3947=LINE('',#3946,#3945);
#3948=EDGE_CURVE('E1541',#1150,#1251,#3947,.T.);
#3949=ORIENTED_EDGE('',*,*,#3948,.F.);
#3950=ORIENTED_EDGE('',*,*,#1530,.F.);
#3951=EDGE_LOOP('',(#3942,#3943,#3949,#3950));
#3952=FACE_BOUND('',#3951,.T.);
#3953=ADVANCED_FACE('F1564',(#3952),#3941,.T.);
#3954=CARTESIAN_POINT('',(94.5,60.,0.));
#3955=DIRECTION('',(0.707106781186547,0.707106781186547,0.));
#3956=DIRECTION('',(0.,0.,1.));
#3957=AXIS2_PLACEMENT_3D('',#3954,#3955,#3956);
#3958=PLANE('',#3957);
#3959=ORIENTED_EDGE('',*,*,#3931,.T.);
#3960=ORIENTED_EDGE('',*,*,#864,.F.);
#3961=DIRECTION('',(0.707106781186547,-0.707106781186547,0.));
#3962=VECTOR('',#3961,1.);
#3963=CARTESIAN_POINT('',(94.5,60.,-65.));
#3964=LINE('',#3963,#3962);
#3965=EDGE_CURVE('E1536',#1224,#855,#3964,.T.);
#3966=ORIENTED_EDGE('',*,*,#3965,.F.);
#3967=ORIENTED_EDGE('',*,*,#1284,.F.);
#3968=EDGE_LOOP('',(#3959,#3960,#3966,#3967));
#3969=FACE_BOUND('',#3968,.T.);
#3970=ADVANCED_FACE('F2796',(#3969),#3958,.T.);
#3971=CARTESIAN_POINT('',(-94.5,60.,0.));
#3972=DIRECTION('',(-0.707106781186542,0.707106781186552,0.));
#3973=DIRECTION('',(0.,0.,-1.));
#3974=AXIS2_PLACEMENT_3D('',#3971,#3972,#3973);
#3975=PLANE('',#3974);
#3976=ORIENTED_EDGE('',*,*,#3948,.T.);
#3977=ORIENTED_EDGE('',*,*,#1252,.F.);
#3978=DIRECTION('',(0.707106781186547,0.707106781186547,0.));
#3979=VECTOR('',#3978,1.);
#3980=CARTESIAN_POINT('',(-95.,59.5,-65.));
#3981=LINE('',#3980,#3979);
#3982=EDGE_CURVE('E1534',#1158,#1243,#3981,.T.);
#3983=ORIENTED_EDGE('',*,*,#3982,.F.);
#3984=ORIENTED_EDGE('',*,*,#1159,.F.);
#3985=EDGE_LOOP('',(#3976,#3977,#3983,#3984));
#3986=FACE_BOUND('',#3985,.T.);
#3987=ADVANCED_FACE('F2807',(#3986),#3975,.T.);
#3988=CARTESIAN_POINT('',(90.,60.,-65.));
#3989=DIRECTION('',(0.,-1.,0.));
#3990=DIRECTION('',(0.,0.,-1.));
#3991=AXIS2_PLACEMENT_3D('',#3988,#3989,#3990);
#3992=CONICAL_SURFACE('',#3991,4.5,0.785398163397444);
#3993=ORIENTED_EDGE('',*,*,#3965,.T.);
#3994=ORIENTED_EDGE('',*,*,#1578,.F.);
#3995=DIRECTION('',(0.,-0.707106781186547,-0.707106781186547));
#3996=VECTOR('',#3995,1.);
#3997=CARTESIAN_POINT('',(90.,60.,-69.5));
#3998=LINE('',#3997,#3996);
#3999=EDGE_CURVE('E1531',#1226,#983,#3998,.T.);
#4000=ORIENTED_EDGE('',*,*,#3999,.F.);
#4001=ORIENTED_EDGE('',*,*,#1227,.F.);
#4002=EDGE_LOOP('',(#3993,#3994,#4000,#4001));
#4003=FACE_BOUND('',#4002,.T.);
#4004=ADVANCED_FACE('F2816',(#4003),#3992,.T.);
#4005=CARTESIAN_POINT('',(-90.,60.,-65.));
#4006=DIRECTION('',(0.,-1.,0.));
#4007=DIRECTION('',(0.,0.,-1.));
#4008=AXIS2_PLACEMENT_3D('',#4005,#4006,#4007);
#4009=CONICAL_SURFACE('',#4008,4.5,0.785398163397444);
#4010=ORIENTED_EDGE('',*,*,#3982,.T.);
#4011=ORIENTED_EDGE('',*,*,#1244,.F.);
#4012=DIRECTION('',(0.,0.707106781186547,0.707106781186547));
#4013=VECTOR('',#4012,1.);
#4014=CARTESIAN_POINT('',(-90.,59.5,-70.));
#4015=LINE('',#4014,#4013);
#4016=EDGE_CURVE('E1533',#975,#1234,#4015,.T.);
#4017=ORIENTED_EDGE('',*,*,#4016,.F.);
#4018=ORIENTED_EDGE('',*,*,#1554,.F.);
#4019=EDGE_LOOP('',(#4010,#4011,#4017,#4018));
#4020=FACE_BOUND('',#4019,.T.);
#4021=ADVANCED_FACE('F2824',(#4020),#4009,.T.);
#4022=CARTESIAN_POINT('',(0.,60.,-69.5));
#4023=DIRECTION('',(0.,0.707106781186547,-0.707106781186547));
#4024=DIRECTION('',(1.,0.,0.));
#4025=AXIS2_PLACEMENT_3D('',#4022,#4023,#4024);
#4026=PLANE('',#4025);
#4027=ORIENTED_EDGE('',*,*,#3999,.T.);
#4028=ORIENTED_EDGE('',*,*,#984,.F.);
#4029=ORIENTED_EDGE('',*,*,#4016,.T.);
#4030=ORIENTED_EDGE('',*,*,#1235,.F.);
#4031=EDGE_LOOP('',(#4027,#4028,#4029,#4030));
#4032=FACE_BOUND('',#4031,.T.);
#4033=ADVANCED_FACE('F2831',(#4032),#4026,.T.);
#4034=CLOSED_SHELL('',(#58,#89,#330,#541,#571,#604,#637,#662,#772,#882,#922,#962,#1002,#1177,
#1217,#1398,#1518,#1542,#1566,#1590,#1614,#1642,#1662,#1682,#1686,#1714,#1734,#1754,#1758,#1786,
#1806,#1826,#1830,#1858,#1878,#1898,#1902,#1930,#1950,#1970,#1974,#1996,#2018,#2040,#2062,#2090,
#2102,#2130,#2142,#2170,#2182,#2210,#2222,#2234,#2246,#2258,#2270,#2292,#2309,#2326,#2343,#2355,
#2372,#2384,#2416,#2440,#2465,#2489,#2514,#2538,#2563,#2580,#2592,#2604,#2616,#2648,#2674,#2691,
#2712,#2724,#2736,#2748,#2770,#2787,#2804,#2816,#2838,#2855,#2872,#2889,#2906,#2923,#2940,#2952,
#2994,#3036,#3078,#3120,#3169,#3218,#3235,#3257,#3274,#3291,#3303,#3315,#3327,#3339,#3351,#3363,
#3375,#3387,#3469,#3491,#3508,#3525,#3542,#3559,#3576,#3593,#3605,#3622,#3641,#3653,#3670,#3689,
#3701,#3718,#3737,#3749,#3771,#3788,#3805,#3822,#3839,#3856,#3873,#3885,#3897,#3919,#3936,#3953,
#3970,#3987,#4004,#4021,#4033));
#4035=MANIFOLD_SOLID_BREP('B2',#4034);
#4036=ADVANCED_BREP_SHAPE_REPRESENTATION('',(#18,#4035),#14);
#4037=SHAPE_DEFINITION_REPRESENTATION(#9,#4036);
ENDSEC;
END-ISO-10303-21;
